VERSION 5.8 ;
BUSBITCHARS "[]" ;
DIVIDERCHAR "/" ;
UNITS
    DATABASE MICRONS 1000 ;
END UNITS

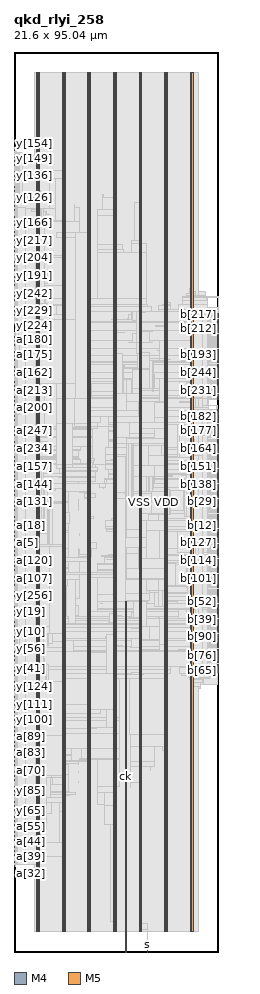
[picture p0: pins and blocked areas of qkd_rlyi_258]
MACRO qkd_rlyi_258
  FOREIGN qkd_rlyi_258 0 0 ;
  CLASS BLOCK ;
  SIZE 21.6 BY 95.04 ;
  PIN a[0]
    DIRECTION INPUT ;
    USE SIGNAL ;
    PORT
      LAYER M4 ;
        RECT  0 42.48 0.084 42.504 ;
    END
  END a[0]
  PIN a[100]
    DIRECTION INPUT ;
    USE SIGNAL ;
    PORT
      LAYER M4 ;
        RECT  0 38.448 0.084 38.472 ;
    END
  END a[100]
  PIN a[101]
    DIRECTION INPUT ;
    USE SIGNAL ;
    PORT
      LAYER M4 ;
        RECT  0 38.592 0.084 38.616 ;
    END
  END a[101]
  PIN a[102]
    DIRECTION INPUT ;
    USE SIGNAL ;
    PORT
      LAYER M4 ;
        RECT  0 38.736 0.084 38.76 ;
    END
  END a[102]
  PIN a[103]
    DIRECTION INPUT ;
    USE SIGNAL ;
    PORT
      LAYER M4 ;
        RECT  0 38.88 0.084 38.904 ;
    END
  END a[103]
  PIN a[104]
    DIRECTION INPUT ;
    USE SIGNAL ;
    PORT
      LAYER M4 ;
        RECT  0 39.024 0.084 39.048 ;
    END
  END a[104]
  PIN a[105]
    DIRECTION INPUT ;
    USE SIGNAL ;
    PORT
      LAYER M4 ;
        RECT  0 39.168 0.084 39.192 ;
    END
  END a[105]
  PIN a[106]
    DIRECTION INPUT ;
    USE SIGNAL ;
    PORT
      LAYER M4 ;
        RECT  0 39.312 0.084 39.336 ;
    END
  END a[106]
  PIN a[107]
    DIRECTION INPUT ;
    USE SIGNAL ;
    PORT
      LAYER M4 ;
        RECT  0 39.456 0.084 39.48 ;
    END
  END a[107]
  PIN a[108]
    DIRECTION INPUT ;
    USE SIGNAL ;
    PORT
      LAYER M4 ;
        RECT  0 39.6 0.084 39.624 ;
    END
  END a[108]
  PIN a[109]
    DIRECTION INPUT ;
    USE SIGNAL ;
    PORT
      LAYER M4 ;
        RECT  0 39.744 0.084 39.768 ;
    END
  END a[109]
  PIN a[10]
    DIRECTION INPUT ;
    USE SIGNAL ;
    PORT
      LAYER M4 ;
        RECT  0 43.92 0.084 43.944 ;
    END
  END a[10]
  PIN a[110]
    DIRECTION INPUT ;
    USE SIGNAL ;
    PORT
      LAYER M4 ;
        RECT  0 39.888 0.084 39.912 ;
    END
  END a[110]
  PIN a[111]
    DIRECTION INPUT ;
    USE SIGNAL ;
    PORT
      LAYER M4 ;
        RECT  0 40.032 0.084 40.056 ;
    END
  END a[111]
  PIN a[112]
    DIRECTION INPUT ;
    USE SIGNAL ;
    PORT
      LAYER M4 ;
        RECT  0 40.176 0.084 40.2 ;
    END
  END a[112]
  PIN a[113]
    DIRECTION INPUT ;
    USE SIGNAL ;
    PORT
      LAYER M4 ;
        RECT  0 40.32 0.084 40.344 ;
    END
  END a[113]
  PIN a[114]
    DIRECTION INPUT ;
    USE SIGNAL ;
    PORT
      LAYER M4 ;
        RECT  0 40.464 0.084 40.488 ;
    END
  END a[114]
  PIN a[115]
    DIRECTION INPUT ;
    USE SIGNAL ;
    PORT
      LAYER M4 ;
        RECT  0 40.608 0.084 40.632 ;
    END
  END a[115]
  PIN a[116]
    DIRECTION INPUT ;
    USE SIGNAL ;
    PORT
      LAYER M4 ;
        RECT  0 40.752 0.084 40.776 ;
    END
  END a[116]
  PIN a[117]
    DIRECTION INPUT ;
    USE SIGNAL ;
    PORT
      LAYER M4 ;
        RECT  0 40.896 0.084 40.92 ;
    END
  END a[117]
  PIN a[118]
    DIRECTION INPUT ;
    USE SIGNAL ;
    PORT
      LAYER M4 ;
        RECT  0 41.04 0.084 41.064 ;
    END
  END a[118]
  PIN a[119]
    DIRECTION INPUT ;
    USE SIGNAL ;
    PORT
      LAYER M4 ;
        RECT  0 41.184 0.084 41.208 ;
    END
  END a[119]
  PIN a[11]
    DIRECTION INPUT ;
    USE SIGNAL ;
    PORT
      LAYER M4 ;
        RECT  0 44.064 0.084 44.088 ;
    END
  END a[11]
  PIN a[120]
    DIRECTION INPUT ;
    USE SIGNAL ;
    PORT
      LAYER M4 ;
        RECT  0 41.328 0.084 41.352 ;
    END
  END a[120]
  PIN a[121]
    DIRECTION INPUT ;
    USE SIGNAL ;
    PORT
      LAYER M4 ;
        RECT  0 41.472 0.084 41.496 ;
    END
  END a[121]
  PIN a[122]
    DIRECTION INPUT ;
    USE SIGNAL ;
    PORT
      LAYER M4 ;
        RECT  0 41.616 0.084 41.64 ;
    END
  END a[122]
  PIN a[123]
    DIRECTION INPUT ;
    USE SIGNAL ;
    PORT
      LAYER M4 ;
        RECT  0 41.76 0.084 41.784 ;
    END
  END a[123]
  PIN a[124]
    DIRECTION INPUT ;
    USE SIGNAL ;
    PORT
      LAYER M4 ;
        RECT  0 41.904 0.084 41.928 ;
    END
  END a[124]
  PIN a[125]
    DIRECTION INPUT ;
    USE SIGNAL ;
    PORT
      LAYER M4 ;
        RECT  0 42.048 0.084 42.072 ;
    END
  END a[125]
  PIN a[126]
    DIRECTION INPUT ;
    USE SIGNAL ;
    PORT
      LAYER M4 ;
        RECT  0 42.192 0.084 42.216 ;
    END
  END a[126]
  PIN a[127]
    DIRECTION INPUT ;
    USE SIGNAL ;
    PORT
      LAYER M4 ;
        RECT  0 42.336 0.084 42.36 ;
    END
  END a[127]
  PIN a[128]
    DIRECTION INPUT ;
    USE SIGNAL ;
    PORT
      LAYER M4 ;
        RECT  0 47.088 0.084 47.112 ;
    END
  END a[128]
  PIN a[129]
    DIRECTION INPUT ;
    USE SIGNAL ;
    PORT
      LAYER M4 ;
        RECT  0 47.232 0.084 47.256 ;
    END
  END a[129]
  PIN a[12]
    DIRECTION INPUT ;
    USE SIGNAL ;
    PORT
      LAYER M4 ;
        RECT  0 44.208 0.084 44.232 ;
    END
  END a[12]
  PIN a[130]
    DIRECTION INPUT ;
    USE SIGNAL ;
    PORT
      LAYER M4 ;
        RECT  0 47.376 0.084 47.4 ;
    END
  END a[130]
  PIN a[131]
    DIRECTION INPUT ;
    USE SIGNAL ;
    PORT
      LAYER M4 ;
        RECT  0 47.52 0.084 47.544 ;
    END
  END a[131]
  PIN a[132]
    DIRECTION INPUT ;
    USE SIGNAL ;
    PORT
      LAYER M4 ;
        RECT  0 47.664 0.084 47.688 ;
    END
  END a[132]
  PIN a[133]
    DIRECTION INPUT ;
    USE SIGNAL ;
    PORT
      LAYER M4 ;
        RECT  0 47.808 0.084 47.832 ;
    END
  END a[133]
  PIN a[134]
    DIRECTION INPUT ;
    USE SIGNAL ;
    PORT
      LAYER M4 ;
        RECT  0 47.952 0.084 47.976 ;
    END
  END a[134]
  PIN a[135]
    DIRECTION INPUT ;
    USE SIGNAL ;
    PORT
      LAYER M4 ;
        RECT  0 48.096 0.084 48.12 ;
    END
  END a[135]
  PIN a[136]
    DIRECTION INPUT ;
    USE SIGNAL ;
    PORT
      LAYER M4 ;
        RECT  0 48.24 0.084 48.264 ;
    END
  END a[136]
  PIN a[137]
    DIRECTION INPUT ;
    USE SIGNAL ;
    PORT
      LAYER M4 ;
        RECT  0 48.384 0.084 48.408 ;
    END
  END a[137]
  PIN a[138]
    DIRECTION INPUT ;
    USE SIGNAL ;
    PORT
      LAYER M4 ;
        RECT  0 48.528 0.084 48.552 ;
    END
  END a[138]
  PIN a[139]
    DIRECTION INPUT ;
    USE SIGNAL ;
    PORT
      LAYER M4 ;
        RECT  0 48.672 0.084 48.696 ;
    END
  END a[139]
  PIN a[13]
    DIRECTION INPUT ;
    USE SIGNAL ;
    PORT
      LAYER M4 ;
        RECT  0 44.352 0.084 44.376 ;
    END
  END a[13]
  PIN a[140]
    DIRECTION INPUT ;
    USE SIGNAL ;
    PORT
      LAYER M4 ;
        RECT  0 48.816 0.084 48.84 ;
    END
  END a[140]
  PIN a[141]
    DIRECTION INPUT ;
    USE SIGNAL ;
    PORT
      LAYER M4 ;
        RECT  0 48.96 0.084 48.984 ;
    END
  END a[141]
  PIN a[142]
    DIRECTION INPUT ;
    USE SIGNAL ;
    PORT
      LAYER M4 ;
        RECT  0 49.104 0.084 49.128 ;
    END
  END a[142]
  PIN a[143]
    DIRECTION INPUT ;
    USE SIGNAL ;
    PORT
      LAYER M4 ;
        RECT  0 49.248 0.084 49.272 ;
    END
  END a[143]
  PIN a[144]
    DIRECTION INPUT ;
    USE SIGNAL ;
    PORT
      LAYER M4 ;
        RECT  0 49.392 0.084 49.416 ;
    END
  END a[144]
  PIN a[145]
    DIRECTION INPUT ;
    USE SIGNAL ;
    PORT
      LAYER M4 ;
        RECT  0 49.536 0.084 49.56 ;
    END
  END a[145]
  PIN a[146]
    DIRECTION INPUT ;
    USE SIGNAL ;
    PORT
      LAYER M4 ;
        RECT  0 49.68 0.084 49.704 ;
    END
  END a[146]
  PIN a[147]
    DIRECTION INPUT ;
    USE SIGNAL ;
    PORT
      LAYER M4 ;
        RECT  0 49.824 0.084 49.848 ;
    END
  END a[147]
  PIN a[148]
    DIRECTION INPUT ;
    USE SIGNAL ;
    PORT
      LAYER M4 ;
        RECT  0 49.968 0.084 49.992 ;
    END
  END a[148]
  PIN a[149]
    DIRECTION INPUT ;
    USE SIGNAL ;
    PORT
      LAYER M4 ;
        RECT  0 50.112 0.084 50.136 ;
    END
  END a[149]
  PIN a[14]
    DIRECTION INPUT ;
    USE SIGNAL ;
    PORT
      LAYER M4 ;
        RECT  0 44.496 0.084 44.52 ;
    END
  END a[14]
  PIN a[150]
    DIRECTION INPUT ;
    USE SIGNAL ;
    PORT
      LAYER M4 ;
        RECT  0 50.256 0.084 50.28 ;
    END
  END a[150]
  PIN a[151]
    DIRECTION INPUT ;
    USE SIGNAL ;
    PORT
      LAYER M4 ;
        RECT  0 50.4 0.084 50.424 ;
    END
  END a[151]
  PIN a[152]
    DIRECTION INPUT ;
    USE SIGNAL ;
    PORT
      LAYER M4 ;
        RECT  0 50.544 0.084 50.568 ;
    END
  END a[152]
  PIN a[153]
    DIRECTION INPUT ;
    USE SIGNAL ;
    PORT
      LAYER M4 ;
        RECT  0 50.688 0.084 50.712 ;
    END
  END a[153]
  PIN a[154]
    DIRECTION INPUT ;
    USE SIGNAL ;
    PORT
      LAYER M4 ;
        RECT  0 50.832 0.084 50.856 ;
    END
  END a[154]
  PIN a[155]
    DIRECTION INPUT ;
    USE SIGNAL ;
    PORT
      LAYER M4 ;
        RECT  0 50.976 0.084 51 ;
    END
  END a[155]
  PIN a[156]
    DIRECTION INPUT ;
    USE SIGNAL ;
    PORT
      LAYER M4 ;
        RECT  0 51.12 0.084 51.144 ;
    END
  END a[156]
  PIN a[157]
    DIRECTION INPUT ;
    USE SIGNAL ;
    PORT
      LAYER M4 ;
        RECT  0 51.264 0.084 51.288 ;
    END
  END a[157]
  PIN a[158]
    DIRECTION INPUT ;
    USE SIGNAL ;
    PORT
      LAYER M4 ;
        RECT  0 51.408 0.084 51.432 ;
    END
  END a[158]
  PIN a[159]
    DIRECTION INPUT ;
    USE SIGNAL ;
    PORT
      LAYER M4 ;
        RECT  0 51.552 0.084 51.576 ;
    END
  END a[159]
  PIN a[15]
    DIRECTION INPUT ;
    USE SIGNAL ;
    PORT
      LAYER M4 ;
        RECT  0 44.64 0.084 44.664 ;
    END
  END a[15]
  PIN a[160]
    DIRECTION INPUT ;
    USE SIGNAL ;
    PORT
      LAYER M4 ;
        RECT  0 60.912 0.084 60.936 ;
    END
  END a[160]
  PIN a[161]
    DIRECTION INPUT ;
    USE SIGNAL ;
    PORT
      LAYER M4 ;
        RECT  0 61.056 0.084 61.08 ;
    END
  END a[161]
  PIN a[162]
    DIRECTION INPUT ;
    USE SIGNAL ;
    PORT
      LAYER M4 ;
        RECT  0 61.2 0.084 61.224 ;
    END
  END a[162]
  PIN a[163]
    DIRECTION INPUT ;
    USE SIGNAL ;
    PORT
      LAYER M4 ;
        RECT  0 61.344 0.084 61.368 ;
    END
  END a[163]
  PIN a[164]
    DIRECTION INPUT ;
    USE SIGNAL ;
    PORT
      LAYER M4 ;
        RECT  0 61.488 0.084 61.512 ;
    END
  END a[164]
  PIN a[165]
    DIRECTION INPUT ;
    USE SIGNAL ;
    PORT
      LAYER M4 ;
        RECT  0 61.632 0.084 61.656 ;
    END
  END a[165]
  PIN a[166]
    DIRECTION INPUT ;
    USE SIGNAL ;
    PORT
      LAYER M4 ;
        RECT  0 61.776 0.084 61.8 ;
    END
  END a[166]
  PIN a[167]
    DIRECTION INPUT ;
    USE SIGNAL ;
    PORT
      LAYER M4 ;
        RECT  0 61.92 0.084 61.944 ;
    END
  END a[167]
  PIN a[168]
    DIRECTION INPUT ;
    USE SIGNAL ;
    PORT
      LAYER M4 ;
        RECT  0 62.064 0.084 62.088 ;
    END
  END a[168]
  PIN a[169]
    DIRECTION INPUT ;
    USE SIGNAL ;
    PORT
      LAYER M4 ;
        RECT  0 62.208 0.084 62.232 ;
    END
  END a[169]
  PIN a[16]
    DIRECTION INPUT ;
    USE SIGNAL ;
    PORT
      LAYER M4 ;
        RECT  0 44.784 0.084 44.808 ;
    END
  END a[16]
  PIN a[170]
    DIRECTION INPUT ;
    USE SIGNAL ;
    PORT
      LAYER M4 ;
        RECT  0 62.352 0.084 62.376 ;
    END
  END a[170]
  PIN a[171]
    DIRECTION INPUT ;
    USE SIGNAL ;
    PORT
      LAYER M4 ;
        RECT  0 62.496 0.084 62.52 ;
    END
  END a[171]
  PIN a[172]
    DIRECTION INPUT ;
    USE SIGNAL ;
    PORT
      LAYER M4 ;
        RECT  0 62.64 0.084 62.664 ;
    END
  END a[172]
  PIN a[173]
    DIRECTION INPUT ;
    USE SIGNAL ;
    PORT
      LAYER M4 ;
        RECT  0 62.784 0.084 62.808 ;
    END
  END a[173]
  PIN a[174]
    DIRECTION INPUT ;
    USE SIGNAL ;
    PORT
      LAYER M4 ;
        RECT  0 62.928 0.084 62.952 ;
    END
  END a[174]
  PIN a[175]
    DIRECTION INPUT ;
    USE SIGNAL ;
    PORT
      LAYER M4 ;
        RECT  0 63.072 0.084 63.096 ;
    END
  END a[175]
  PIN a[176]
    DIRECTION INPUT ;
    USE SIGNAL ;
    PORT
      LAYER M4 ;
        RECT  0 63.216 0.084 63.24 ;
    END
  END a[176]
  PIN a[177]
    DIRECTION INPUT ;
    USE SIGNAL ;
    PORT
      LAYER M4 ;
        RECT  0 63.36 0.084 63.384 ;
    END
  END a[177]
  PIN a[178]
    DIRECTION INPUT ;
    USE SIGNAL ;
    PORT
      LAYER M4 ;
        RECT  0 63.504 0.084 63.528 ;
    END
  END a[178]
  PIN a[179]
    DIRECTION INPUT ;
    USE SIGNAL ;
    PORT
      LAYER M4 ;
        RECT  0 63.648 0.084 63.672 ;
    END
  END a[179]
  PIN a[17]
    DIRECTION INPUT ;
    USE SIGNAL ;
    PORT
      LAYER M4 ;
        RECT  0 44.928 0.084 44.952 ;
    END
  END a[17]
  PIN a[180]
    DIRECTION INPUT ;
    USE SIGNAL ;
    PORT
      LAYER M4 ;
        RECT  0 63.792 0.084 63.816 ;
    END
  END a[180]
  PIN a[181]
    DIRECTION INPUT ;
    USE SIGNAL ;
    PORT
      LAYER M4 ;
        RECT  0 63.936 0.084 63.96 ;
    END
  END a[181]
  PIN a[182]
    DIRECTION INPUT ;
    USE SIGNAL ;
    PORT
      LAYER M4 ;
        RECT  0 64.08 0.084 64.104 ;
    END
  END a[182]
  PIN a[183]
    DIRECTION INPUT ;
    USE SIGNAL ;
    PORT
      LAYER M4 ;
        RECT  0 64.224 0.084 64.248 ;
    END
  END a[183]
  PIN a[184]
    DIRECTION INPUT ;
    USE SIGNAL ;
    PORT
      LAYER M4 ;
        RECT  0 64.368 0.084 64.392 ;
    END
  END a[184]
  PIN a[185]
    DIRECTION INPUT ;
    USE SIGNAL ;
    PORT
      LAYER M4 ;
        RECT  0 64.512 0.084 64.536 ;
    END
  END a[185]
  PIN a[186]
    DIRECTION INPUT ;
    USE SIGNAL ;
    PORT
      LAYER M4 ;
        RECT  0 64.656 0.084 64.68 ;
    END
  END a[186]
  PIN a[187]
    DIRECTION INPUT ;
    USE SIGNAL ;
    PORT
      LAYER M4 ;
        RECT  0 64.8 0.084 64.824 ;
    END
  END a[187]
  PIN a[188]
    DIRECTION INPUT ;
    USE SIGNAL ;
    PORT
      LAYER M4 ;
        RECT  0 64.944 0.084 64.968 ;
    END
  END a[188]
  PIN a[189]
    DIRECTION INPUT ;
    USE SIGNAL ;
    PORT
      LAYER M4 ;
        RECT  0 65.088 0.084 65.112 ;
    END
  END a[189]
  PIN a[18]
    DIRECTION INPUT ;
    USE SIGNAL ;
    PORT
      LAYER M4 ;
        RECT  0 45.072 0.084 45.096 ;
    END
  END a[18]
  PIN a[190]
    DIRECTION INPUT ;
    USE SIGNAL ;
    PORT
      LAYER M4 ;
        RECT  0 65.232 0.084 65.256 ;
    END
  END a[190]
  PIN a[191]
    DIRECTION INPUT ;
    USE SIGNAL ;
    PORT
      LAYER M4 ;
        RECT  0 65.376 0.084 65.4 ;
    END
  END a[191]
  PIN a[192]
    DIRECTION INPUT ;
    USE SIGNAL ;
    PORT
      LAYER M4 ;
        RECT  0 56.304 0.084 56.328 ;
    END
  END a[192]
  PIN a[193]
    DIRECTION INPUT ;
    USE SIGNAL ;
    PORT
      LAYER M4 ;
        RECT  0 56.448 0.084 56.472 ;
    END
  END a[193]
  PIN a[194]
    DIRECTION INPUT ;
    USE SIGNAL ;
    PORT
      LAYER M4 ;
        RECT  0 56.592 0.084 56.616 ;
    END
  END a[194]
  PIN a[195]
    DIRECTION INPUT ;
    USE SIGNAL ;
    PORT
      LAYER M4 ;
        RECT  0 56.736 0.084 56.76 ;
    END
  END a[195]
  PIN a[196]
    DIRECTION INPUT ;
    USE SIGNAL ;
    PORT
      LAYER M4 ;
        RECT  0 56.88 0.084 56.904 ;
    END
  END a[196]
  PIN a[197]
    DIRECTION INPUT ;
    USE SIGNAL ;
    PORT
      LAYER M4 ;
        RECT  0 57.024 0.084 57.048 ;
    END
  END a[197]
  PIN a[198]
    DIRECTION INPUT ;
    USE SIGNAL ;
    PORT
      LAYER M4 ;
        RECT  0 57.168 0.084 57.192 ;
    END
  END a[198]
  PIN a[199]
    DIRECTION INPUT ;
    USE SIGNAL ;
    PORT
      LAYER M4 ;
        RECT  0 57.312 0.084 57.336 ;
    END
  END a[199]
  PIN a[19]
    DIRECTION INPUT ;
    USE SIGNAL ;
    PORT
      LAYER M4 ;
        RECT  0 45.216 0.084 45.24 ;
    END
  END a[19]
  PIN a[1]
    DIRECTION INPUT ;
    USE SIGNAL ;
    PORT
      LAYER M4 ;
        RECT  0 42.624 0.084 42.648 ;
    END
  END a[1]
  PIN a[200]
    DIRECTION INPUT ;
    USE SIGNAL ;
    PORT
      LAYER M4 ;
        RECT  0 57.456 0.084 57.48 ;
    END
  END a[200]
  PIN a[201]
    DIRECTION INPUT ;
    USE SIGNAL ;
    PORT
      LAYER M4 ;
        RECT  0 57.6 0.084 57.624 ;
    END
  END a[201]
  PIN a[202]
    DIRECTION INPUT ;
    USE SIGNAL ;
    PORT
      LAYER M4 ;
        RECT  0 57.744 0.084 57.768 ;
    END
  END a[202]
  PIN a[203]
    DIRECTION INPUT ;
    USE SIGNAL ;
    PORT
      LAYER M4 ;
        RECT  0 57.888 0.084 57.912 ;
    END
  END a[203]
  PIN a[204]
    DIRECTION INPUT ;
    USE SIGNAL ;
    PORT
      LAYER M4 ;
        RECT  0 58.032 0.084 58.056 ;
    END
  END a[204]
  PIN a[205]
    DIRECTION INPUT ;
    USE SIGNAL ;
    PORT
      LAYER M4 ;
        RECT  0 58.176 0.084 58.2 ;
    END
  END a[205]
  PIN a[206]
    DIRECTION INPUT ;
    USE SIGNAL ;
    PORT
      LAYER M4 ;
        RECT  0 58.32 0.084 58.344 ;
    END
  END a[206]
  PIN a[207]
    DIRECTION INPUT ;
    USE SIGNAL ;
    PORT
      LAYER M4 ;
        RECT  0 58.464 0.084 58.488 ;
    END
  END a[207]
  PIN a[208]
    DIRECTION INPUT ;
    USE SIGNAL ;
    PORT
      LAYER M4 ;
        RECT  0 58.608 0.084 58.632 ;
    END
  END a[208]
  PIN a[209]
    DIRECTION INPUT ;
    USE SIGNAL ;
    PORT
      LAYER M4 ;
        RECT  0 58.752 0.084 58.776 ;
    END
  END a[209]
  PIN a[20]
    DIRECTION INPUT ;
    USE SIGNAL ;
    PORT
      LAYER M4 ;
        RECT  0 45.36 0.084 45.384 ;
    END
  END a[20]
  PIN a[210]
    DIRECTION INPUT ;
    USE SIGNAL ;
    PORT
      LAYER M4 ;
        RECT  0 58.896 0.084 58.92 ;
    END
  END a[210]
  PIN a[211]
    DIRECTION INPUT ;
    USE SIGNAL ;
    PORT
      LAYER M4 ;
        RECT  0 59.04 0.084 59.064 ;
    END
  END a[211]
  PIN a[212]
    DIRECTION INPUT ;
    USE SIGNAL ;
    PORT
      LAYER M4 ;
        RECT  0 59.184 0.084 59.208 ;
    END
  END a[212]
  PIN a[213]
    DIRECTION INPUT ;
    USE SIGNAL ;
    PORT
      LAYER M4 ;
        RECT  0 59.328 0.084 59.352 ;
    END
  END a[213]
  PIN a[214]
    DIRECTION INPUT ;
    USE SIGNAL ;
    PORT
      LAYER M4 ;
        RECT  0 59.472 0.084 59.496 ;
    END
  END a[214]
  PIN a[215]
    DIRECTION INPUT ;
    USE SIGNAL ;
    PORT
      LAYER M4 ;
        RECT  0 59.616 0.084 59.64 ;
    END
  END a[215]
  PIN a[216]
    DIRECTION INPUT ;
    USE SIGNAL ;
    PORT
      LAYER M4 ;
        RECT  0 59.76 0.084 59.784 ;
    END
  END a[216]
  PIN a[217]
    DIRECTION INPUT ;
    USE SIGNAL ;
    PORT
      LAYER M4 ;
        RECT  0 59.904 0.084 59.928 ;
    END
  END a[217]
  PIN a[218]
    DIRECTION INPUT ;
    USE SIGNAL ;
    PORT
      LAYER M4 ;
        RECT  0 60.048 0.084 60.072 ;
    END
  END a[218]
  PIN a[219]
    DIRECTION INPUT ;
    USE SIGNAL ;
    PORT
      LAYER M4 ;
        RECT  0 60.192 0.084 60.216 ;
    END
  END a[219]
  PIN a[21]
    DIRECTION INPUT ;
    USE SIGNAL ;
    PORT
      LAYER M4 ;
        RECT  0 45.504 0.084 45.528 ;
    END
  END a[21]
  PIN a[220]
    DIRECTION INPUT ;
    USE SIGNAL ;
    PORT
      LAYER M4 ;
        RECT  0 60.336 0.084 60.36 ;
    END
  END a[220]
  PIN a[221]
    DIRECTION INPUT ;
    USE SIGNAL ;
    PORT
      LAYER M4 ;
        RECT  0 60.48 0.084 60.504 ;
    END
  END a[221]
  PIN a[222]
    DIRECTION INPUT ;
    USE SIGNAL ;
    PORT
      LAYER M4 ;
        RECT  0 60.624 0.084 60.648 ;
    END
  END a[222]
  PIN a[223]
    DIRECTION INPUT ;
    USE SIGNAL ;
    PORT
      LAYER M4 ;
        RECT  0 60.768 0.084 60.792 ;
    END
  END a[223]
  PIN a[224]
    DIRECTION INPUT ;
    USE SIGNAL ;
    PORT
      LAYER M4 ;
        RECT  0 51.696 0.084 51.72 ;
    END
  END a[224]
  PIN a[225]
    DIRECTION INPUT ;
    USE SIGNAL ;
    PORT
      LAYER M4 ;
        RECT  0 51.84 0.084 51.864 ;
    END
  END a[225]
  PIN a[226]
    DIRECTION INPUT ;
    USE SIGNAL ;
    PORT
      LAYER M4 ;
        RECT  0 51.984 0.084 52.008 ;
    END
  END a[226]
  PIN a[227]
    DIRECTION INPUT ;
    USE SIGNAL ;
    PORT
      LAYER M4 ;
        RECT  0 52.128 0.084 52.152 ;
    END
  END a[227]
  PIN a[228]
    DIRECTION INPUT ;
    USE SIGNAL ;
    PORT
      LAYER M4 ;
        RECT  0 52.272 0.084 52.296 ;
    END
  END a[228]
  PIN a[229]
    DIRECTION INPUT ;
    USE SIGNAL ;
    PORT
      LAYER M4 ;
        RECT  0 52.416 0.084 52.44 ;
    END
  END a[229]
  PIN a[22]
    DIRECTION INPUT ;
    USE SIGNAL ;
    PORT
      LAYER M4 ;
        RECT  0 45.648 0.084 45.672 ;
    END
  END a[22]
  PIN a[230]
    DIRECTION INPUT ;
    USE SIGNAL ;
    PORT
      LAYER M4 ;
        RECT  0 52.56 0.084 52.584 ;
    END
  END a[230]
  PIN a[231]
    DIRECTION INPUT ;
    USE SIGNAL ;
    PORT
      LAYER M4 ;
        RECT  0 52.704 0.084 52.728 ;
    END
  END a[231]
  PIN a[232]
    DIRECTION INPUT ;
    USE SIGNAL ;
    PORT
      LAYER M4 ;
        RECT  0 52.848 0.084 52.872 ;
    END
  END a[232]
  PIN a[233]
    DIRECTION INPUT ;
    USE SIGNAL ;
    PORT
      LAYER M4 ;
        RECT  0 52.992 0.084 53.016 ;
    END
  END a[233]
  PIN a[234]
    DIRECTION INPUT ;
    USE SIGNAL ;
    PORT
      LAYER M4 ;
        RECT  0 53.136 0.084 53.16 ;
    END
  END a[234]
  PIN a[235]
    DIRECTION INPUT ;
    USE SIGNAL ;
    PORT
      LAYER M4 ;
        RECT  0 53.28 0.084 53.304 ;
    END
  END a[235]
  PIN a[236]
    DIRECTION INPUT ;
    USE SIGNAL ;
    PORT
      LAYER M4 ;
        RECT  0 53.424 0.084 53.448 ;
    END
  END a[236]
  PIN a[237]
    DIRECTION INPUT ;
    USE SIGNAL ;
    PORT
      LAYER M4 ;
        RECT  0 53.568 0.084 53.592 ;
    END
  END a[237]
  PIN a[238]
    DIRECTION INPUT ;
    USE SIGNAL ;
    PORT
      LAYER M4 ;
        RECT  0 53.712 0.084 53.736 ;
    END
  END a[238]
  PIN a[239]
    DIRECTION INPUT ;
    USE SIGNAL ;
    PORT
      LAYER M4 ;
        RECT  0 53.856 0.084 53.88 ;
    END
  END a[239]
  PIN a[23]
    DIRECTION INPUT ;
    USE SIGNAL ;
    PORT
      LAYER M4 ;
        RECT  0 45.792 0.084 45.816 ;
    END
  END a[23]
  PIN a[240]
    DIRECTION INPUT ;
    USE SIGNAL ;
    PORT
      LAYER M4 ;
        RECT  0 54 0.084 54.024 ;
    END
  END a[240]
  PIN a[241]
    DIRECTION INPUT ;
    USE SIGNAL ;
    PORT
      LAYER M4 ;
        RECT  0 54.144 0.084 54.168 ;
    END
  END a[241]
  PIN a[242]
    DIRECTION INPUT ;
    USE SIGNAL ;
    PORT
      LAYER M4 ;
        RECT  0 54.288 0.084 54.312 ;
    END
  END a[242]
  PIN a[243]
    DIRECTION INPUT ;
    USE SIGNAL ;
    PORT
      LAYER M4 ;
        RECT  0 54.432 0.084 54.456 ;
    END
  END a[243]
  PIN a[244]
    DIRECTION INPUT ;
    USE SIGNAL ;
    PORT
      LAYER M4 ;
        RECT  0 54.576 0.084 54.6 ;
    END
  END a[244]
  PIN a[245]
    DIRECTION INPUT ;
    USE SIGNAL ;
    PORT
      LAYER M4 ;
        RECT  0 54.72 0.084 54.744 ;
    END
  END a[245]
  PIN a[246]
    DIRECTION INPUT ;
    USE SIGNAL ;
    PORT
      LAYER M4 ;
        RECT  0 54.864 0.084 54.888 ;
    END
  END a[246]
  PIN a[247]
    DIRECTION INPUT ;
    USE SIGNAL ;
    PORT
      LAYER M4 ;
        RECT  0 55.008 0.084 55.032 ;
    END
  END a[247]
  PIN a[248]
    DIRECTION INPUT ;
    USE SIGNAL ;
    PORT
      LAYER M4 ;
        RECT  0 55.152 0.084 55.176 ;
    END
  END a[248]
  PIN a[249]
    DIRECTION INPUT ;
    USE SIGNAL ;
    PORT
      LAYER M4 ;
        RECT  0 55.296 0.084 55.32 ;
    END
  END a[249]
  PIN a[24]
    DIRECTION INPUT ;
    USE SIGNAL ;
    PORT
      LAYER M4 ;
        RECT  0 45.936 0.084 45.96 ;
    END
  END a[24]
  PIN a[250]
    DIRECTION INPUT ;
    USE SIGNAL ;
    PORT
      LAYER M4 ;
        RECT  0 55.44 0.084 55.464 ;
    END
  END a[250]
  PIN a[251]
    DIRECTION INPUT ;
    USE SIGNAL ;
    PORT
      LAYER M4 ;
        RECT  0 55.584 0.084 55.608 ;
    END
  END a[251]
  PIN a[252]
    DIRECTION INPUT ;
    USE SIGNAL ;
    PORT
      LAYER M4 ;
        RECT  0 55.728 0.084 55.752 ;
    END
  END a[252]
  PIN a[253]
    DIRECTION INPUT ;
    USE SIGNAL ;
    PORT
      LAYER M4 ;
        RECT  0 55.872 0.084 55.896 ;
    END
  END a[253]
  PIN a[254]
    DIRECTION INPUT ;
    USE SIGNAL ;
    PORT
      LAYER M4 ;
        RECT  0 56.016 0.084 56.04 ;
    END
  END a[254]
  PIN a[255]
    DIRECTION INPUT ;
    USE SIGNAL ;
    PORT
      LAYER M4 ;
        RECT  0 56.16 0.084 56.184 ;
    END
  END a[255]
  PIN a[256]
    DIRECTION INPUT ;
    USE SIGNAL ;
    PORT
      LAYER M4 ;
        RECT  0 32.112 0.084 32.136 ;
    END
  END a[256]
  PIN a[257]
    DIRECTION INPUT ;
    USE SIGNAL ;
    PORT
      LAYER M4 ;
        RECT  0 32.256 0.084 32.28 ;
    END
  END a[257]
  PIN a[25]
    DIRECTION INPUT ;
    USE SIGNAL ;
    PORT
      LAYER M4 ;
        RECT  0 46.08 0.084 46.104 ;
    END
  END a[25]
  PIN a[26]
    DIRECTION INPUT ;
    USE SIGNAL ;
    PORT
      LAYER M4 ;
        RECT  0 46.224 0.084 46.248 ;
    END
  END a[26]
  PIN a[27]
    DIRECTION INPUT ;
    USE SIGNAL ;
    PORT
      LAYER M4 ;
        RECT  0 46.368 0.084 46.392 ;
    END
  END a[27]
  PIN a[28]
    DIRECTION INPUT ;
    USE SIGNAL ;
    PORT
      LAYER M4 ;
        RECT  0 46.512 0.084 46.536 ;
    END
  END a[28]
  PIN a[29]
    DIRECTION INPUT ;
    USE SIGNAL ;
    PORT
      LAYER M4 ;
        RECT  0 46.656 0.084 46.68 ;
    END
  END a[29]
  PIN a[2]
    DIRECTION INPUT ;
    USE SIGNAL ;
    PORT
      LAYER M4 ;
        RECT  0 42.768 0.084 42.792 ;
    END
  END a[2]
  PIN a[30]
    DIRECTION INPUT ;
    USE SIGNAL ;
    PORT
      LAYER M4 ;
        RECT  0 46.8 0.084 46.824 ;
    END
  END a[30]
  PIN a[31]
    DIRECTION INPUT ;
    USE SIGNAL ;
    PORT
      LAYER M4 ;
        RECT  0 46.944 0.084 46.968 ;
    END
  END a[31]
  PIN a[32]
    DIRECTION INPUT ;
    USE SIGNAL ;
    PORT
      LAYER M4 ;
        RECT  0 9.072 0.084 9.096 ;
    END
  END a[32]
  PIN a[33]
    DIRECTION INPUT ;
    USE SIGNAL ;
    PORT
      LAYER M4 ;
        RECT  0 9.216 0.084 9.24 ;
    END
  END a[33]
  PIN a[34]
    DIRECTION INPUT ;
    USE SIGNAL ;
    PORT
      LAYER M4 ;
        RECT  0 9.36 0.084 9.384 ;
    END
  END a[34]
  PIN a[35]
    DIRECTION INPUT ;
    USE SIGNAL ;
    PORT
      LAYER M4 ;
        RECT  0 9.504 0.084 9.528 ;
    END
  END a[35]
  PIN a[36]
    DIRECTION INPUT ;
    USE SIGNAL ;
    PORT
      LAYER M4 ;
        RECT  0 9.648 0.084 9.672 ;
    END
  END a[36]
  PIN a[37]
    DIRECTION INPUT ;
    USE SIGNAL ;
    PORT
      LAYER M4 ;
        RECT  0 9.792 0.084 9.816 ;
    END
  END a[37]
  PIN a[38]
    DIRECTION INPUT ;
    USE SIGNAL ;
    PORT
      LAYER M4 ;
        RECT  0 9.936 0.084 9.96 ;
    END
  END a[38]
  PIN a[39]
    DIRECTION INPUT ;
    USE SIGNAL ;
    PORT
      LAYER M4 ;
        RECT  0 10.08 0.084 10.104 ;
    END
  END a[39]
  PIN a[3]
    DIRECTION INPUT ;
    USE SIGNAL ;
    PORT
      LAYER M4 ;
        RECT  0 42.912 0.084 42.936 ;
    END
  END a[3]
  PIN a[40]
    DIRECTION INPUT ;
    USE SIGNAL ;
    PORT
      LAYER M4 ;
        RECT  0 10.224 0.084 10.248 ;
    END
  END a[40]
  PIN a[41]
    DIRECTION INPUT ;
    USE SIGNAL ;
    PORT
      LAYER M4 ;
        RECT  0 10.368 0.084 10.392 ;
    END
  END a[41]
  PIN a[42]
    DIRECTION INPUT ;
    USE SIGNAL ;
    PORT
      LAYER M4 ;
        RECT  0 10.512 0.084 10.536 ;
    END
  END a[42]
  PIN a[43]
    DIRECTION INPUT ;
    USE SIGNAL ;
    PORT
      LAYER M4 ;
        RECT  0 10.656 0.084 10.68 ;
    END
  END a[43]
  PIN a[44]
    DIRECTION INPUT ;
    USE SIGNAL ;
    PORT
      LAYER M4 ;
        RECT  0 10.8 0.084 10.824 ;
    END
  END a[44]
  PIN a[45]
    DIRECTION INPUT ;
    USE SIGNAL ;
    PORT
      LAYER M4 ;
        RECT  0 10.944 0.084 10.968 ;
    END
  END a[45]
  PIN a[46]
    DIRECTION INPUT ;
    USE SIGNAL ;
    PORT
      LAYER M4 ;
        RECT  0 11.088 0.084 11.112 ;
    END
  END a[46]
  PIN a[47]
    DIRECTION INPUT ;
    USE SIGNAL ;
    PORT
      LAYER M4 ;
        RECT  0 11.232 0.084 11.256 ;
    END
  END a[47]
  PIN a[48]
    DIRECTION INPUT ;
    USE SIGNAL ;
    PORT
      LAYER M4 ;
        RECT  0 11.376 0.084 11.4 ;
    END
  END a[48]
  PIN a[49]
    DIRECTION INPUT ;
    USE SIGNAL ;
    PORT
      LAYER M4 ;
        RECT  0 11.52 0.084 11.544 ;
    END
  END a[49]
  PIN a[4]
    DIRECTION INPUT ;
    USE SIGNAL ;
    PORT
      LAYER M4 ;
        RECT  0 43.056 0.084 43.08 ;
    END
  END a[4]
  PIN a[50]
    DIRECTION INPUT ;
    USE SIGNAL ;
    PORT
      LAYER M4 ;
        RECT  0 11.664 0.084 11.688 ;
    END
  END a[50]
  PIN a[51]
    DIRECTION INPUT ;
    USE SIGNAL ;
    PORT
      LAYER M4 ;
        RECT  0 11.808 0.084 11.832 ;
    END
  END a[51]
  PIN a[52]
    DIRECTION INPUT ;
    USE SIGNAL ;
    PORT
      LAYER M4 ;
        RECT  0 11.952 0.084 11.976 ;
    END
  END a[52]
  PIN a[53]
    DIRECTION INPUT ;
    USE SIGNAL ;
    PORT
      LAYER M4 ;
        RECT  0 12.096 0.084 12.12 ;
    END
  END a[53]
  PIN a[54]
    DIRECTION INPUT ;
    USE SIGNAL ;
    PORT
      LAYER M4 ;
        RECT  0 12.24 0.084 12.264 ;
    END
  END a[54]
  PIN a[55]
    DIRECTION INPUT ;
    USE SIGNAL ;
    PORT
      LAYER M4 ;
        RECT  0 12.384 0.084 12.408 ;
    END
  END a[55]
  PIN a[56]
    DIRECTION INPUT ;
    USE SIGNAL ;
    PORT
      LAYER M4 ;
        RECT  0 12.528 0.084 12.552 ;
    END
  END a[56]
  PIN a[57]
    DIRECTION INPUT ;
    USE SIGNAL ;
    PORT
      LAYER M4 ;
        RECT  0 12.672 0.084 12.696 ;
    END
  END a[57]
  PIN a[58]
    DIRECTION INPUT ;
    USE SIGNAL ;
    PORT
      LAYER M4 ;
        RECT  0 12.816 0.084 12.84 ;
    END
  END a[58]
  PIN a[59]
    DIRECTION INPUT ;
    USE SIGNAL ;
    PORT
      LAYER M4 ;
        RECT  0 12.96 0.084 12.984 ;
    END
  END a[59]
  PIN a[5]
    DIRECTION INPUT ;
    USE SIGNAL ;
    PORT
      LAYER M4 ;
        RECT  0 43.2 0.084 43.224 ;
    END
  END a[5]
  PIN a[60]
    DIRECTION INPUT ;
    USE SIGNAL ;
    PORT
      LAYER M4 ;
        RECT  0 13.104 0.084 13.128 ;
    END
  END a[60]
  PIN a[61]
    DIRECTION INPUT ;
    USE SIGNAL ;
    PORT
      LAYER M4 ;
        RECT  0 13.248 0.084 13.272 ;
    END
  END a[61]
  PIN a[62]
    DIRECTION INPUT ;
    USE SIGNAL ;
    PORT
      LAYER M4 ;
        RECT  0 13.392 0.084 13.416 ;
    END
  END a[62]
  PIN a[63]
    DIRECTION INPUT ;
    USE SIGNAL ;
    PORT
      LAYER M4 ;
        RECT  0 13.536 0.084 13.56 ;
    END
  END a[63]
  PIN a[64]
    DIRECTION INPUT ;
    USE SIGNAL ;
    PORT
      LAYER M4 ;
        RECT  0 18.288 0.084 18.312 ;
    END
  END a[64]
  PIN a[65]
    DIRECTION INPUT ;
    USE SIGNAL ;
    PORT
      LAYER M4 ;
        RECT  0 18.432 0.084 18.456 ;
    END
  END a[65]
  PIN a[66]
    DIRECTION INPUT ;
    USE SIGNAL ;
    PORT
      LAYER M4 ;
        RECT  0 18.576 0.084 18.6 ;
    END
  END a[66]
  PIN a[67]
    DIRECTION INPUT ;
    USE SIGNAL ;
    PORT
      LAYER M4 ;
        RECT  0 18.72 0.084 18.744 ;
    END
  END a[67]
  PIN a[68]
    DIRECTION INPUT ;
    USE SIGNAL ;
    PORT
      LAYER M4 ;
        RECT  0 18.864 0.084 18.888 ;
    END
  END a[68]
  PIN a[69]
    DIRECTION INPUT ;
    USE SIGNAL ;
    PORT
      LAYER M4 ;
        RECT  0 19.008 0.084 19.032 ;
    END
  END a[69]
  PIN a[6]
    DIRECTION INPUT ;
    USE SIGNAL ;
    PORT
      LAYER M4 ;
        RECT  0 43.344 0.084 43.368 ;
    END
  END a[6]
  PIN a[70]
    DIRECTION INPUT ;
    USE SIGNAL ;
    PORT
      LAYER M4 ;
        RECT  0 19.152 0.084 19.176 ;
    END
  END a[70]
  PIN a[71]
    DIRECTION INPUT ;
    USE SIGNAL ;
    PORT
      LAYER M4 ;
        RECT  0 19.296 0.084 19.32 ;
    END
  END a[71]
  PIN a[72]
    DIRECTION INPUT ;
    USE SIGNAL ;
    PORT
      LAYER M4 ;
        RECT  0 19.44 0.084 19.464 ;
    END
  END a[72]
  PIN a[73]
    DIRECTION INPUT ;
    USE SIGNAL ;
    PORT
      LAYER M4 ;
        RECT  0 19.584 0.084 19.608 ;
    END
  END a[73]
  PIN a[74]
    DIRECTION INPUT ;
    USE SIGNAL ;
    PORT
      LAYER M4 ;
        RECT  0 19.728 0.084 19.752 ;
    END
  END a[74]
  PIN a[75]
    DIRECTION INPUT ;
    USE SIGNAL ;
    PORT
      LAYER M4 ;
        RECT  0 19.872 0.084 19.896 ;
    END
  END a[75]
  PIN a[76]
    DIRECTION INPUT ;
    USE SIGNAL ;
    PORT
      LAYER M4 ;
        RECT  0 20.016 0.084 20.04 ;
    END
  END a[76]
  PIN a[77]
    DIRECTION INPUT ;
    USE SIGNAL ;
    PORT
      LAYER M4 ;
        RECT  0 20.16 0.084 20.184 ;
    END
  END a[77]
  PIN a[78]
    DIRECTION INPUT ;
    USE SIGNAL ;
    PORT
      LAYER M4 ;
        RECT  0 20.304 0.084 20.328 ;
    END
  END a[78]
  PIN a[79]
    DIRECTION INPUT ;
    USE SIGNAL ;
    PORT
      LAYER M4 ;
        RECT  0 20.448 0.084 20.472 ;
    END
  END a[79]
  PIN a[7]
    DIRECTION INPUT ;
    USE SIGNAL ;
    PORT
      LAYER M4 ;
        RECT  0 43.488 0.084 43.512 ;
    END
  END a[7]
  PIN a[80]
    DIRECTION INPUT ;
    USE SIGNAL ;
    PORT
      LAYER M4 ;
        RECT  0 20.592 0.084 20.616 ;
    END
  END a[80]
  PIN a[81]
    DIRECTION INPUT ;
    USE SIGNAL ;
    PORT
      LAYER M4 ;
        RECT  0 20.736 0.084 20.76 ;
    END
  END a[81]
  PIN a[82]
    DIRECTION INPUT ;
    USE SIGNAL ;
    PORT
      LAYER M4 ;
        RECT  0 20.88 0.084 20.904 ;
    END
  END a[82]
  PIN a[83]
    DIRECTION INPUT ;
    USE SIGNAL ;
    PORT
      LAYER M4 ;
        RECT  0 21.024 0.084 21.048 ;
    END
  END a[83]
  PIN a[84]
    DIRECTION INPUT ;
    USE SIGNAL ;
    PORT
      LAYER M4 ;
        RECT  0 21.168 0.084 21.192 ;
    END
  END a[84]
  PIN a[85]
    DIRECTION INPUT ;
    USE SIGNAL ;
    PORT
      LAYER M4 ;
        RECT  0 21.312 0.084 21.336 ;
    END
  END a[85]
  PIN a[86]
    DIRECTION INPUT ;
    USE SIGNAL ;
    PORT
      LAYER M4 ;
        RECT  0 21.456 0.084 21.48 ;
    END
  END a[86]
  PIN a[87]
    DIRECTION INPUT ;
    USE SIGNAL ;
    PORT
      LAYER M4 ;
        RECT  0 21.6 0.084 21.624 ;
    END
  END a[87]
  PIN a[88]
    DIRECTION INPUT ;
    USE SIGNAL ;
    PORT
      LAYER M4 ;
        RECT  0 21.744 0.084 21.768 ;
    END
  END a[88]
  PIN a[89]
    DIRECTION INPUT ;
    USE SIGNAL ;
    PORT
      LAYER M4 ;
        RECT  0 21.888 0.084 21.912 ;
    END
  END a[89]
  PIN a[8]
    DIRECTION INPUT ;
    USE SIGNAL ;
    PORT
      LAYER M4 ;
        RECT  0 43.632 0.084 43.656 ;
    END
  END a[8]
  PIN a[90]
    DIRECTION INPUT ;
    USE SIGNAL ;
    PORT
      LAYER M4 ;
        RECT  0 22.032 0.084 22.056 ;
    END
  END a[90]
  PIN a[91]
    DIRECTION INPUT ;
    USE SIGNAL ;
    PORT
      LAYER M4 ;
        RECT  0 22.176 0.084 22.2 ;
    END
  END a[91]
  PIN a[92]
    DIRECTION INPUT ;
    USE SIGNAL ;
    PORT
      LAYER M4 ;
        RECT  0 22.32 0.084 22.344 ;
    END
  END a[92]
  PIN a[93]
    DIRECTION INPUT ;
    USE SIGNAL ;
    PORT
      LAYER M4 ;
        RECT  0 22.464 0.084 22.488 ;
    END
  END a[93]
  PIN a[94]
    DIRECTION INPUT ;
    USE SIGNAL ;
    PORT
      LAYER M4 ;
        RECT  0 22.608 0.084 22.632 ;
    END
  END a[94]
  PIN a[95]
    DIRECTION INPUT ;
    USE SIGNAL ;
    PORT
      LAYER M4 ;
        RECT  0 22.752 0.084 22.776 ;
    END
  END a[95]
  PIN a[96]
    DIRECTION INPUT ;
    USE SIGNAL ;
    PORT
      LAYER M4 ;
        RECT  0 37.872 0.084 37.896 ;
    END
  END a[96]
  PIN a[97]
    DIRECTION INPUT ;
    USE SIGNAL ;
    PORT
      LAYER M4 ;
        RECT  0 38.016 0.084 38.04 ;
    END
  END a[97]
  PIN a[98]
    DIRECTION INPUT ;
    USE SIGNAL ;
    PORT
      LAYER M4 ;
        RECT  0 38.16 0.084 38.184 ;
    END
  END a[98]
  PIN a[99]
    DIRECTION INPUT ;
    USE SIGNAL ;
    PORT
      LAYER M4 ;
        RECT  0 38.304 0.084 38.328 ;
    END
  END a[99]
  PIN a[9]
    DIRECTION INPUT ;
    USE SIGNAL ;
    PORT
      LAYER M4 ;
        RECT  0 43.776 0.084 43.8 ;
    END
  END a[9]
  PIN b[0]
    DIRECTION OUTPUT ;
    USE SIGNAL ;
    PORT
      LAYER M4 ;
        RECT  21.516 43.344 21.6 43.368 ;
    END
  END b[0]
  PIN b[100]
    DIRECTION OUTPUT ;
    USE SIGNAL ;
    PORT
      LAYER M4 ;
        RECT  21.516 39.312 21.6 39.336 ;
    END
  END b[100]
  PIN b[101]
    DIRECTION OUTPUT ;
    USE SIGNAL ;
    PORT
      LAYER M4 ;
        RECT  21.516 39.456 21.6 39.48 ;
    END
  END b[101]
  PIN b[102]
    DIRECTION OUTPUT ;
    USE SIGNAL ;
    PORT
      LAYER M4 ;
        RECT  21.516 39.6 21.6 39.624 ;
    END
  END b[102]
  PIN b[103]
    DIRECTION OUTPUT ;
    USE SIGNAL ;
    PORT
      LAYER M4 ;
        RECT  21.516 39.744 21.6 39.768 ;
    END
  END b[103]
  PIN b[104]
    DIRECTION OUTPUT ;
    USE SIGNAL ;
    PORT
      LAYER M4 ;
        RECT  21.516 39.888 21.6 39.912 ;
    END
  END b[104]
  PIN b[105]
    DIRECTION OUTPUT ;
    USE SIGNAL ;
    PORT
      LAYER M4 ;
        RECT  21.516 40.032 21.6 40.056 ;
    END
  END b[105]
  PIN b[106]
    DIRECTION OUTPUT ;
    USE SIGNAL ;
    PORT
      LAYER M4 ;
        RECT  21.516 40.176 21.6 40.2 ;
    END
  END b[106]
  PIN b[107]
    DIRECTION OUTPUT ;
    USE SIGNAL ;
    PORT
      LAYER M4 ;
        RECT  21.516 40.32 21.6 40.344 ;
    END
  END b[107]
  PIN b[108]
    DIRECTION OUTPUT ;
    USE SIGNAL ;
    PORT
      LAYER M4 ;
        RECT  21.516 40.464 21.6 40.488 ;
    END
  END b[108]
  PIN b[109]
    DIRECTION OUTPUT ;
    USE SIGNAL ;
    PORT
      LAYER M4 ;
        RECT  21.516 40.608 21.6 40.632 ;
    END
  END b[109]
  PIN b[10]
    DIRECTION OUTPUT ;
    USE SIGNAL ;
    PORT
      LAYER M4 ;
        RECT  21.516 44.784 21.6 44.808 ;
    END
  END b[10]
  PIN b[110]
    DIRECTION OUTPUT ;
    USE SIGNAL ;
    PORT
      LAYER M4 ;
        RECT  21.516 40.752 21.6 40.776 ;
    END
  END b[110]
  PIN b[111]
    DIRECTION OUTPUT ;
    USE SIGNAL ;
    PORT
      LAYER M4 ;
        RECT  21.516 40.896 21.6 40.92 ;
    END
  END b[111]
  PIN b[112]
    DIRECTION OUTPUT ;
    USE SIGNAL ;
    PORT
      LAYER M4 ;
        RECT  21.516 41.04 21.6 41.064 ;
    END
  END b[112]
  PIN b[113]
    DIRECTION OUTPUT ;
    USE SIGNAL ;
    PORT
      LAYER M4 ;
        RECT  21.516 41.184 21.6 41.208 ;
    END
  END b[113]
  PIN b[114]
    DIRECTION OUTPUT ;
    USE SIGNAL ;
    PORT
      LAYER M4 ;
        RECT  21.516 41.328 21.6 41.352 ;
    END
  END b[114]
  PIN b[115]
    DIRECTION OUTPUT ;
    USE SIGNAL ;
    PORT
      LAYER M4 ;
        RECT  21.516 41.472 21.6 41.496 ;
    END
  END b[115]
  PIN b[116]
    DIRECTION OUTPUT ;
    USE SIGNAL ;
    PORT
      LAYER M4 ;
        RECT  21.516 41.616 21.6 41.64 ;
    END
  END b[116]
  PIN b[117]
    DIRECTION OUTPUT ;
    USE SIGNAL ;
    PORT
      LAYER M4 ;
        RECT  21.516 41.76 21.6 41.784 ;
    END
  END b[117]
  PIN b[118]
    DIRECTION OUTPUT ;
    USE SIGNAL ;
    PORT
      LAYER M4 ;
        RECT  21.516 41.904 21.6 41.928 ;
    END
  END b[118]
  PIN b[119]
    DIRECTION OUTPUT ;
    USE SIGNAL ;
    PORT
      LAYER M4 ;
        RECT  21.516 42.048 21.6 42.072 ;
    END
  END b[119]
  PIN b[11]
    DIRECTION OUTPUT ;
    USE SIGNAL ;
    PORT
      LAYER M4 ;
        RECT  21.516 44.928 21.6 44.952 ;
    END
  END b[11]
  PIN b[120]
    DIRECTION OUTPUT ;
    USE SIGNAL ;
    PORT
      LAYER M4 ;
        RECT  21.516 42.192 21.6 42.216 ;
    END
  END b[120]
  PIN b[121]
    DIRECTION OUTPUT ;
    USE SIGNAL ;
    PORT
      LAYER M4 ;
        RECT  21.516 42.336 21.6 42.36 ;
    END
  END b[121]
  PIN b[122]
    DIRECTION OUTPUT ;
    USE SIGNAL ;
    PORT
      LAYER M4 ;
        RECT  21.516 42.48 21.6 42.504 ;
    END
  END b[122]
  PIN b[123]
    DIRECTION OUTPUT ;
    USE SIGNAL ;
    PORT
      LAYER M4 ;
        RECT  21.516 42.624 21.6 42.648 ;
    END
  END b[123]
  PIN b[124]
    DIRECTION OUTPUT ;
    USE SIGNAL ;
    PORT
      LAYER M4 ;
        RECT  21.516 42.768 21.6 42.792 ;
    END
  END b[124]
  PIN b[125]
    DIRECTION OUTPUT ;
    USE SIGNAL ;
    PORT
      LAYER M4 ;
        RECT  21.516 42.912 21.6 42.936 ;
    END
  END b[125]
  PIN b[126]
    DIRECTION OUTPUT ;
    USE SIGNAL ;
    PORT
      LAYER M4 ;
        RECT  21.516 43.056 21.6 43.08 ;
    END
  END b[126]
  PIN b[127]
    DIRECTION OUTPUT ;
    USE SIGNAL ;
    PORT
      LAYER M4 ;
        RECT  21.516 43.2 21.6 43.224 ;
    END
  END b[127]
  PIN b[128]
    DIRECTION OUTPUT ;
    USE SIGNAL ;
    PORT
      LAYER M4 ;
        RECT  21.516 47.952 21.6 47.976 ;
    END
  END b[128]
  PIN b[129]
    DIRECTION OUTPUT ;
    USE SIGNAL ;
    PORT
      LAYER M4 ;
        RECT  21.516 48.096 21.6 48.12 ;
    END
  END b[129]
  PIN b[12]
    DIRECTION OUTPUT ;
    USE SIGNAL ;
    PORT
      LAYER M4 ;
        RECT  21.516 45.072 21.6 45.096 ;
    END
  END b[12]
  PIN b[130]
    DIRECTION OUTPUT ;
    USE SIGNAL ;
    PORT
      LAYER M4 ;
        RECT  21.516 48.24 21.6 48.264 ;
    END
  END b[130]
  PIN b[131]
    DIRECTION OUTPUT ;
    USE SIGNAL ;
    PORT
      LAYER M4 ;
        RECT  21.516 48.384 21.6 48.408 ;
    END
  END b[131]
  PIN b[132]
    DIRECTION OUTPUT ;
    USE SIGNAL ;
    PORT
      LAYER M4 ;
        RECT  21.516 48.528 21.6 48.552 ;
    END
  END b[132]
  PIN b[133]
    DIRECTION OUTPUT ;
    USE SIGNAL ;
    PORT
      LAYER M4 ;
        RECT  21.516 48.672 21.6 48.696 ;
    END
  END b[133]
  PIN b[134]
    DIRECTION OUTPUT ;
    USE SIGNAL ;
    PORT
      LAYER M4 ;
        RECT  21.516 48.816 21.6 48.84 ;
    END
  END b[134]
  PIN b[135]
    DIRECTION OUTPUT ;
    USE SIGNAL ;
    PORT
      LAYER M4 ;
        RECT  21.516 48.96 21.6 48.984 ;
    END
  END b[135]
  PIN b[136]
    DIRECTION OUTPUT ;
    USE SIGNAL ;
    PORT
      LAYER M4 ;
        RECT  21.516 49.104 21.6 49.128 ;
    END
  END b[136]
  PIN b[137]
    DIRECTION OUTPUT ;
    USE SIGNAL ;
    PORT
      LAYER M4 ;
        RECT  21.516 49.248 21.6 49.272 ;
    END
  END b[137]
  PIN b[138]
    DIRECTION OUTPUT ;
    USE SIGNAL ;
    PORT
      LAYER M4 ;
        RECT  21.516 49.392 21.6 49.416 ;
    END
  END b[138]
  PIN b[139]
    DIRECTION OUTPUT ;
    USE SIGNAL ;
    PORT
      LAYER M4 ;
        RECT  21.516 49.536 21.6 49.56 ;
    END
  END b[139]
  PIN b[13]
    DIRECTION OUTPUT ;
    USE SIGNAL ;
    PORT
      LAYER M4 ;
        RECT  21.516 45.216 21.6 45.24 ;
    END
  END b[13]
  PIN b[140]
    DIRECTION OUTPUT ;
    USE SIGNAL ;
    PORT
      LAYER M4 ;
        RECT  21.516 49.68 21.6 49.704 ;
    END
  END b[140]
  PIN b[141]
    DIRECTION OUTPUT ;
    USE SIGNAL ;
    PORT
      LAYER M4 ;
        RECT  21.516 49.824 21.6 49.848 ;
    END
  END b[141]
  PIN b[142]
    DIRECTION OUTPUT ;
    USE SIGNAL ;
    PORT
      LAYER M4 ;
        RECT  21.516 49.968 21.6 49.992 ;
    END
  END b[142]
  PIN b[143]
    DIRECTION OUTPUT ;
    USE SIGNAL ;
    PORT
      LAYER M4 ;
        RECT  21.516 50.112 21.6 50.136 ;
    END
  END b[143]
  PIN b[144]
    DIRECTION OUTPUT ;
    USE SIGNAL ;
    PORT
      LAYER M4 ;
        RECT  21.516 50.256 21.6 50.28 ;
    END
  END b[144]
  PIN b[145]
    DIRECTION OUTPUT ;
    USE SIGNAL ;
    PORT
      LAYER M4 ;
        RECT  21.516 50.4 21.6 50.424 ;
    END
  END b[145]
  PIN b[146]
    DIRECTION OUTPUT ;
    USE SIGNAL ;
    PORT
      LAYER M4 ;
        RECT  21.516 50.544 21.6 50.568 ;
    END
  END b[146]
  PIN b[147]
    DIRECTION OUTPUT ;
    USE SIGNAL ;
    PORT
      LAYER M4 ;
        RECT  21.516 50.688 21.6 50.712 ;
    END
  END b[147]
  PIN b[148]
    DIRECTION OUTPUT ;
    USE SIGNAL ;
    PORT
      LAYER M4 ;
        RECT  21.516 50.832 21.6 50.856 ;
    END
  END b[148]
  PIN b[149]
    DIRECTION OUTPUT ;
    USE SIGNAL ;
    PORT
      LAYER M4 ;
        RECT  21.516 50.976 21.6 51 ;
    END
  END b[149]
  PIN b[14]
    DIRECTION OUTPUT ;
    USE SIGNAL ;
    PORT
      LAYER M4 ;
        RECT  21.516 45.36 21.6 45.384 ;
    END
  END b[14]
  PIN b[150]
    DIRECTION OUTPUT ;
    USE SIGNAL ;
    PORT
      LAYER M4 ;
        RECT  21.516 51.12 21.6 51.144 ;
    END
  END b[150]
  PIN b[151]
    DIRECTION OUTPUT ;
    USE SIGNAL ;
    PORT
      LAYER M4 ;
        RECT  21.516 51.264 21.6 51.288 ;
    END
  END b[151]
  PIN b[152]
    DIRECTION OUTPUT ;
    USE SIGNAL ;
    PORT
      LAYER M4 ;
        RECT  21.516 51.408 21.6 51.432 ;
    END
  END b[152]
  PIN b[153]
    DIRECTION OUTPUT ;
    USE SIGNAL ;
    PORT
      LAYER M4 ;
        RECT  21.516 51.552 21.6 51.576 ;
    END
  END b[153]
  PIN b[154]
    DIRECTION OUTPUT ;
    USE SIGNAL ;
    PORT
      LAYER M4 ;
        RECT  21.516 51.696 21.6 51.72 ;
    END
  END b[154]
  PIN b[155]
    DIRECTION OUTPUT ;
    USE SIGNAL ;
    PORT
      LAYER M4 ;
        RECT  21.516 51.84 21.6 51.864 ;
    END
  END b[155]
  PIN b[156]
    DIRECTION OUTPUT ;
    USE SIGNAL ;
    PORT
      LAYER M4 ;
        RECT  21.516 51.984 21.6 52.008 ;
    END
  END b[156]
  PIN b[157]
    DIRECTION OUTPUT ;
    USE SIGNAL ;
    PORT
      LAYER M4 ;
        RECT  21.516 52.128 21.6 52.152 ;
    END
  END b[157]
  PIN b[158]
    DIRECTION OUTPUT ;
    USE SIGNAL ;
    PORT
      LAYER M4 ;
        RECT  21.516 52.272 21.6 52.296 ;
    END
  END b[158]
  PIN b[159]
    DIRECTION OUTPUT ;
    USE SIGNAL ;
    PORT
      LAYER M4 ;
        RECT  21.516 52.416 21.6 52.44 ;
    END
  END b[159]
  PIN b[15]
    DIRECTION OUTPUT ;
    USE SIGNAL ;
    PORT
      LAYER M4 ;
        RECT  21.516 45.504 21.6 45.528 ;
    END
  END b[15]
  PIN b[160]
    DIRECTION OUTPUT ;
    USE SIGNAL ;
    PORT
      LAYER M4 ;
        RECT  21.516 52.56 21.6 52.584 ;
    END
  END b[160]
  PIN b[161]
    DIRECTION OUTPUT ;
    USE SIGNAL ;
    PORT
      LAYER M4 ;
        RECT  21.516 52.704 21.6 52.728 ;
    END
  END b[161]
  PIN b[162]
    DIRECTION OUTPUT ;
    USE SIGNAL ;
    PORT
      LAYER M4 ;
        RECT  21.516 52.848 21.6 52.872 ;
    END
  END b[162]
  PIN b[163]
    DIRECTION OUTPUT ;
    USE SIGNAL ;
    PORT
      LAYER M4 ;
        RECT  21.516 52.992 21.6 53.016 ;
    END
  END b[163]
  PIN b[164]
    DIRECTION OUTPUT ;
    USE SIGNAL ;
    PORT
      LAYER M4 ;
        RECT  21.516 53.136 21.6 53.16 ;
    END
  END b[164]
  PIN b[165]
    DIRECTION OUTPUT ;
    USE SIGNAL ;
    PORT
      LAYER M4 ;
        RECT  21.516 53.28 21.6 53.304 ;
    END
  END b[165]
  PIN b[166]
    DIRECTION OUTPUT ;
    USE SIGNAL ;
    PORT
      LAYER M4 ;
        RECT  21.516 53.424 21.6 53.448 ;
    END
  END b[166]
  PIN b[167]
    DIRECTION OUTPUT ;
    USE SIGNAL ;
    PORT
      LAYER M4 ;
        RECT  21.516 53.568 21.6 53.592 ;
    END
  END b[167]
  PIN b[168]
    DIRECTION OUTPUT ;
    USE SIGNAL ;
    PORT
      LAYER M4 ;
        RECT  21.516 53.712 21.6 53.736 ;
    END
  END b[168]
  PIN b[169]
    DIRECTION OUTPUT ;
    USE SIGNAL ;
    PORT
      LAYER M4 ;
        RECT  21.516 53.856 21.6 53.88 ;
    END
  END b[169]
  PIN b[16]
    DIRECTION OUTPUT ;
    USE SIGNAL ;
    PORT
      LAYER M4 ;
        RECT  21.516 45.648 21.6 45.672 ;
    END
  END b[16]
  PIN b[170]
    DIRECTION OUTPUT ;
    USE SIGNAL ;
    PORT
      LAYER M4 ;
        RECT  21.516 54 21.6 54.024 ;
    END
  END b[170]
  PIN b[171]
    DIRECTION OUTPUT ;
    USE SIGNAL ;
    PORT
      LAYER M4 ;
        RECT  21.516 54.144 21.6 54.168 ;
    END
  END b[171]
  PIN b[172]
    DIRECTION OUTPUT ;
    USE SIGNAL ;
    PORT
      LAYER M4 ;
        RECT  21.516 54.288 21.6 54.312 ;
    END
  END b[172]
  PIN b[173]
    DIRECTION OUTPUT ;
    USE SIGNAL ;
    PORT
      LAYER M4 ;
        RECT  21.516 54.432 21.6 54.456 ;
    END
  END b[173]
  PIN b[174]
    DIRECTION OUTPUT ;
    USE SIGNAL ;
    PORT
      LAYER M4 ;
        RECT  21.516 54.576 21.6 54.6 ;
    END
  END b[174]
  PIN b[175]
    DIRECTION OUTPUT ;
    USE SIGNAL ;
    PORT
      LAYER M4 ;
        RECT  21.516 54.72 21.6 54.744 ;
    END
  END b[175]
  PIN b[176]
    DIRECTION OUTPUT ;
    USE SIGNAL ;
    PORT
      LAYER M4 ;
        RECT  21.516 54.864 21.6 54.888 ;
    END
  END b[176]
  PIN b[177]
    DIRECTION OUTPUT ;
    USE SIGNAL ;
    PORT
      LAYER M4 ;
        RECT  21.516 55.008 21.6 55.032 ;
    END
  END b[177]
  PIN b[178]
    DIRECTION OUTPUT ;
    USE SIGNAL ;
    PORT
      LAYER M4 ;
        RECT  21.516 55.152 21.6 55.176 ;
    END
  END b[178]
  PIN b[179]
    DIRECTION OUTPUT ;
    USE SIGNAL ;
    PORT
      LAYER M4 ;
        RECT  21.516 55.296 21.6 55.32 ;
    END
  END b[179]
  PIN b[17]
    DIRECTION OUTPUT ;
    USE SIGNAL ;
    PORT
      LAYER M4 ;
        RECT  21.516 45.792 21.6 45.816 ;
    END
  END b[17]
  PIN b[180]
    DIRECTION OUTPUT ;
    USE SIGNAL ;
    PORT
      LAYER M4 ;
        RECT  21.516 55.44 21.6 55.464 ;
    END
  END b[180]
  PIN b[181]
    DIRECTION OUTPUT ;
    USE SIGNAL ;
    PORT
      LAYER M4 ;
        RECT  21.516 55.584 21.6 55.608 ;
    END
  END b[181]
  PIN b[182]
    DIRECTION OUTPUT ;
    USE SIGNAL ;
    PORT
      LAYER M4 ;
        RECT  21.516 55.728 21.6 55.752 ;
    END
  END b[182]
  PIN b[183]
    DIRECTION OUTPUT ;
    USE SIGNAL ;
    PORT
      LAYER M4 ;
        RECT  21.516 55.872 21.6 55.896 ;
    END
  END b[183]
  PIN b[184]
    DIRECTION OUTPUT ;
    USE SIGNAL ;
    PORT
      LAYER M4 ;
        RECT  21.516 56.016 21.6 56.04 ;
    END
  END b[184]
  PIN b[185]
    DIRECTION OUTPUT ;
    USE SIGNAL ;
    PORT
      LAYER M4 ;
        RECT  21.516 56.16 21.6 56.184 ;
    END
  END b[185]
  PIN b[186]
    DIRECTION OUTPUT ;
    USE SIGNAL ;
    PORT
      LAYER M4 ;
        RECT  21.516 56.304 21.6 56.328 ;
    END
  END b[186]
  PIN b[187]
    DIRECTION OUTPUT ;
    USE SIGNAL ;
    PORT
      LAYER M4 ;
        RECT  21.516 56.448 21.6 56.472 ;
    END
  END b[187]
  PIN b[188]
    DIRECTION OUTPUT ;
    USE SIGNAL ;
    PORT
      LAYER M4 ;
        RECT  21.516 56.592 21.6 56.616 ;
    END
  END b[188]
  PIN b[189]
    DIRECTION OUTPUT ;
    USE SIGNAL ;
    PORT
      LAYER M4 ;
        RECT  21.516 56.736 21.6 56.76 ;
    END
  END b[189]
  PIN b[18]
    DIRECTION OUTPUT ;
    USE SIGNAL ;
    PORT
      LAYER M4 ;
        RECT  21.516 45.936 21.6 45.96 ;
    END
  END b[18]
  PIN b[190]
    DIRECTION OUTPUT ;
    USE SIGNAL ;
    PORT
      LAYER M4 ;
        RECT  21.516 56.88 21.6 56.904 ;
    END
  END b[190]
  PIN b[191]
    DIRECTION OUTPUT ;
    USE SIGNAL ;
    PORT
      LAYER M4 ;
        RECT  21.516 57.024 21.6 57.048 ;
    END
  END b[191]
  PIN b[192]
    DIRECTION OUTPUT ;
    USE SIGNAL ;
    PORT
      LAYER M4 ;
        RECT  21.516 62.928 21.6 62.952 ;
    END
  END b[192]
  PIN b[193]
    DIRECTION OUTPUT ;
    USE SIGNAL ;
    PORT
      LAYER M4 ;
        RECT  21.516 63.072 21.6 63.096 ;
    END
  END b[193]
  PIN b[194]
    DIRECTION OUTPUT ;
    USE SIGNAL ;
    PORT
      LAYER M4 ;
        RECT  21.516 63.216 21.6 63.24 ;
    END
  END b[194]
  PIN b[195]
    DIRECTION OUTPUT ;
    USE SIGNAL ;
    PORT
      LAYER M4 ;
        RECT  21.516 63.36 21.6 63.384 ;
    END
  END b[195]
  PIN b[196]
    DIRECTION OUTPUT ;
    USE SIGNAL ;
    PORT
      LAYER M4 ;
        RECT  21.516 63.504 21.6 63.528 ;
    END
  END b[196]
  PIN b[197]
    DIRECTION OUTPUT ;
    USE SIGNAL ;
    PORT
      LAYER M4 ;
        RECT  21.516 63.648 21.6 63.672 ;
    END
  END b[197]
  PIN b[198]
    DIRECTION OUTPUT ;
    USE SIGNAL ;
    PORT
      LAYER M4 ;
        RECT  21.516 63.792 21.6 63.816 ;
    END
  END b[198]
  PIN b[199]
    DIRECTION OUTPUT ;
    USE SIGNAL ;
    PORT
      LAYER M4 ;
        RECT  21.516 63.936 21.6 63.96 ;
    END
  END b[199]
  PIN b[19]
    DIRECTION OUTPUT ;
    USE SIGNAL ;
    PORT
      LAYER M4 ;
        RECT  21.516 46.08 21.6 46.104 ;
    END
  END b[19]
  PIN b[1]
    DIRECTION OUTPUT ;
    USE SIGNAL ;
    PORT
      LAYER M4 ;
        RECT  21.516 43.488 21.6 43.512 ;
    END
  END b[1]
  PIN b[200]
    DIRECTION OUTPUT ;
    USE SIGNAL ;
    PORT
      LAYER M4 ;
        RECT  21.516 64.08 21.6 64.104 ;
    END
  END b[200]
  PIN b[201]
    DIRECTION OUTPUT ;
    USE SIGNAL ;
    PORT
      LAYER M4 ;
        RECT  21.516 64.224 21.6 64.248 ;
    END
  END b[201]
  PIN b[202]
    DIRECTION OUTPUT ;
    USE SIGNAL ;
    PORT
      LAYER M4 ;
        RECT  21.516 64.368 21.6 64.392 ;
    END
  END b[202]
  PIN b[203]
    DIRECTION OUTPUT ;
    USE SIGNAL ;
    PORT
      LAYER M4 ;
        RECT  21.516 64.512 21.6 64.536 ;
    END
  END b[203]
  PIN b[204]
    DIRECTION OUTPUT ;
    USE SIGNAL ;
    PORT
      LAYER M4 ;
        RECT  21.516 64.656 21.6 64.68 ;
    END
  END b[204]
  PIN b[205]
    DIRECTION OUTPUT ;
    USE SIGNAL ;
    PORT
      LAYER M4 ;
        RECT  21.516 64.8 21.6 64.824 ;
    END
  END b[205]
  PIN b[206]
    DIRECTION OUTPUT ;
    USE SIGNAL ;
    PORT
      LAYER M4 ;
        RECT  21.516 64.944 21.6 64.968 ;
    END
  END b[206]
  PIN b[207]
    DIRECTION OUTPUT ;
    USE SIGNAL ;
    PORT
      LAYER M4 ;
        RECT  21.516 65.088 21.6 65.112 ;
    END
  END b[207]
  PIN b[208]
    DIRECTION OUTPUT ;
    USE SIGNAL ;
    PORT
      LAYER M4 ;
        RECT  21.516 65.232 21.6 65.256 ;
    END
  END b[208]
  PIN b[209]
    DIRECTION OUTPUT ;
    USE SIGNAL ;
    PORT
      LAYER M4 ;
        RECT  21.516 65.376 21.6 65.4 ;
    END
  END b[209]
  PIN b[20]
    DIRECTION OUTPUT ;
    USE SIGNAL ;
    PORT
      LAYER M4 ;
        RECT  21.516 46.224 21.6 46.248 ;
    END
  END b[20]
  PIN b[210]
    DIRECTION OUTPUT ;
    USE SIGNAL ;
    PORT
      LAYER M4 ;
        RECT  21.516 65.52 21.6 65.544 ;
    END
  END b[210]
  PIN b[211]
    DIRECTION OUTPUT ;
    USE SIGNAL ;
    PORT
      LAYER M4 ;
        RECT  21.516 65.664 21.6 65.688 ;
    END
  END b[211]
  PIN b[212]
    DIRECTION OUTPUT ;
    USE SIGNAL ;
    PORT
      LAYER M4 ;
        RECT  21.516 65.808 21.6 65.832 ;
    END
  END b[212]
  PIN b[213]
    DIRECTION OUTPUT ;
    USE SIGNAL ;
    PORT
      LAYER M4 ;
        RECT  21.516 65.952 21.6 65.976 ;
    END
  END b[213]
  PIN b[214]
    DIRECTION OUTPUT ;
    USE SIGNAL ;
    PORT
      LAYER M4 ;
        RECT  21.516 66.096 21.6 66.12 ;
    END
  END b[214]
  PIN b[215]
    DIRECTION OUTPUT ;
    USE SIGNAL ;
    PORT
      LAYER M4 ;
        RECT  21.516 66.24 21.6 66.264 ;
    END
  END b[215]
  PIN b[216]
    DIRECTION OUTPUT ;
    USE SIGNAL ;
    PORT
      LAYER M4 ;
        RECT  21.516 66.384 21.6 66.408 ;
    END
  END b[216]
  PIN b[217]
    DIRECTION OUTPUT ;
    USE SIGNAL ;
    PORT
      LAYER M4 ;
        RECT  21.516 66.528 21.6 66.552 ;
    END
  END b[217]
  PIN b[218]
    DIRECTION OUTPUT ;
    USE SIGNAL ;
    PORT
      LAYER M4 ;
        RECT  21.516 66.672 21.6 66.696 ;
    END
  END b[218]
  PIN b[219]
    DIRECTION OUTPUT ;
    USE SIGNAL ;
    PORT
      LAYER M4 ;
        RECT  21.516 66.816 21.6 66.84 ;
    END
  END b[219]
  PIN b[21]
    DIRECTION OUTPUT ;
    USE SIGNAL ;
    PORT
      LAYER M4 ;
        RECT  21.516 46.368 21.6 46.392 ;
    END
  END b[21]
  PIN b[220]
    DIRECTION OUTPUT ;
    USE SIGNAL ;
    PORT
      LAYER M4 ;
        RECT  21.516 66.96 21.6 66.984 ;
    END
  END b[220]
  PIN b[221]
    DIRECTION OUTPUT ;
    USE SIGNAL ;
    PORT
      LAYER M4 ;
        RECT  21.516 67.104 21.6 67.128 ;
    END
  END b[221]
  PIN b[222]
    DIRECTION OUTPUT ;
    USE SIGNAL ;
    PORT
      LAYER M4 ;
        RECT  21.516 67.248 21.6 67.272 ;
    END
  END b[222]
  PIN b[223]
    DIRECTION OUTPUT ;
    USE SIGNAL ;
    PORT
      LAYER M4 ;
        RECT  21.516 67.392 21.6 67.416 ;
    END
  END b[223]
  PIN b[224]
    DIRECTION OUTPUT ;
    USE SIGNAL ;
    PORT
      LAYER M4 ;
        RECT  21.516 58.32 21.6 58.344 ;
    END
  END b[224]
  PIN b[225]
    DIRECTION OUTPUT ;
    USE SIGNAL ;
    PORT
      LAYER M4 ;
        RECT  21.516 58.464 21.6 58.488 ;
    END
  END b[225]
  PIN b[226]
    DIRECTION OUTPUT ;
    USE SIGNAL ;
    PORT
      LAYER M4 ;
        RECT  21.516 58.608 21.6 58.632 ;
    END
  END b[226]
  PIN b[227]
    DIRECTION OUTPUT ;
    USE SIGNAL ;
    PORT
      LAYER M4 ;
        RECT  21.516 58.752 21.6 58.776 ;
    END
  END b[227]
  PIN b[228]
    DIRECTION OUTPUT ;
    USE SIGNAL ;
    PORT
      LAYER M4 ;
        RECT  21.516 58.896 21.6 58.92 ;
    END
  END b[228]
  PIN b[229]
    DIRECTION OUTPUT ;
    USE SIGNAL ;
    PORT
      LAYER M4 ;
        RECT  21.516 59.04 21.6 59.064 ;
    END
  END b[229]
  PIN b[22]
    DIRECTION OUTPUT ;
    USE SIGNAL ;
    PORT
      LAYER M4 ;
        RECT  21.516 46.512 21.6 46.536 ;
    END
  END b[22]
  PIN b[230]
    DIRECTION OUTPUT ;
    USE SIGNAL ;
    PORT
      LAYER M4 ;
        RECT  21.516 59.184 21.6 59.208 ;
    END
  END b[230]
  PIN b[231]
    DIRECTION OUTPUT ;
    USE SIGNAL ;
    PORT
      LAYER M4 ;
        RECT  21.516 59.328 21.6 59.352 ;
    END
  END b[231]
  PIN b[232]
    DIRECTION OUTPUT ;
    USE SIGNAL ;
    PORT
      LAYER M4 ;
        RECT  21.516 59.472 21.6 59.496 ;
    END
  END b[232]
  PIN b[233]
    DIRECTION OUTPUT ;
    USE SIGNAL ;
    PORT
      LAYER M4 ;
        RECT  21.516 59.616 21.6 59.64 ;
    END
  END b[233]
  PIN b[234]
    DIRECTION OUTPUT ;
    USE SIGNAL ;
    PORT
      LAYER M4 ;
        RECT  21.516 59.76 21.6 59.784 ;
    END
  END b[234]
  PIN b[235]
    DIRECTION OUTPUT ;
    USE SIGNAL ;
    PORT
      LAYER M4 ;
        RECT  21.516 59.904 21.6 59.928 ;
    END
  END b[235]
  PIN b[236]
    DIRECTION OUTPUT ;
    USE SIGNAL ;
    PORT
      LAYER M4 ;
        RECT  21.516 60.048 21.6 60.072 ;
    END
  END b[236]
  PIN b[237]
    DIRECTION OUTPUT ;
    USE SIGNAL ;
    PORT
      LAYER M4 ;
        RECT  21.516 60.192 21.6 60.216 ;
    END
  END b[237]
  PIN b[238]
    DIRECTION OUTPUT ;
    USE SIGNAL ;
    PORT
      LAYER M4 ;
        RECT  21.516 60.336 21.6 60.36 ;
    END
  END b[238]
  PIN b[239]
    DIRECTION OUTPUT ;
    USE SIGNAL ;
    PORT
      LAYER M4 ;
        RECT  21.516 60.48 21.6 60.504 ;
    END
  END b[239]
  PIN b[23]
    DIRECTION OUTPUT ;
    USE SIGNAL ;
    PORT
      LAYER M4 ;
        RECT  21.516 46.656 21.6 46.68 ;
    END
  END b[23]
  PIN b[240]
    DIRECTION OUTPUT ;
    USE SIGNAL ;
    PORT
      LAYER M4 ;
        RECT  21.516 60.624 21.6 60.648 ;
    END
  END b[240]
  PIN b[241]
    DIRECTION OUTPUT ;
    USE SIGNAL ;
    PORT
      LAYER M4 ;
        RECT  21.516 60.768 21.6 60.792 ;
    END
  END b[241]
  PIN b[242]
    DIRECTION OUTPUT ;
    USE SIGNAL ;
    PORT
      LAYER M4 ;
        RECT  21.516 60.912 21.6 60.936 ;
    END
  END b[242]
  PIN b[243]
    DIRECTION OUTPUT ;
    USE SIGNAL ;
    PORT
      LAYER M4 ;
        RECT  21.516 61.056 21.6 61.08 ;
    END
  END b[243]
  PIN b[244]
    DIRECTION OUTPUT ;
    USE SIGNAL ;
    PORT
      LAYER M4 ;
        RECT  21.516 61.2 21.6 61.224 ;
    END
  END b[244]
  PIN b[245]
    DIRECTION OUTPUT ;
    USE SIGNAL ;
    PORT
      LAYER M4 ;
        RECT  21.516 61.344 21.6 61.368 ;
    END
  END b[245]
  PIN b[246]
    DIRECTION OUTPUT ;
    USE SIGNAL ;
    PORT
      LAYER M4 ;
        RECT  21.516 61.488 21.6 61.512 ;
    END
  END b[246]
  PIN b[247]
    DIRECTION OUTPUT ;
    USE SIGNAL ;
    PORT
      LAYER M4 ;
        RECT  21.516 61.632 21.6 61.656 ;
    END
  END b[247]
  PIN b[248]
    DIRECTION OUTPUT ;
    USE SIGNAL ;
    PORT
      LAYER M4 ;
        RECT  21.516 61.776 21.6 61.8 ;
    END
  END b[248]
  PIN b[249]
    DIRECTION OUTPUT ;
    USE SIGNAL ;
    PORT
      LAYER M4 ;
        RECT  21.516 61.92 21.6 61.944 ;
    END
  END b[249]
  PIN b[24]
    DIRECTION OUTPUT ;
    USE SIGNAL ;
    PORT
      LAYER M4 ;
        RECT  21.516 46.8 21.6 46.824 ;
    END
  END b[24]
  PIN b[250]
    DIRECTION OUTPUT ;
    USE SIGNAL ;
    PORT
      LAYER M4 ;
        RECT  21.516 62.064 21.6 62.088 ;
    END
  END b[250]
  PIN b[251]
    DIRECTION OUTPUT ;
    USE SIGNAL ;
    PORT
      LAYER M4 ;
        RECT  21.516 62.208 21.6 62.232 ;
    END
  END b[251]
  PIN b[252]
    DIRECTION OUTPUT ;
    USE SIGNAL ;
    PORT
      LAYER M4 ;
        RECT  21.516 62.352 21.6 62.376 ;
    END
  END b[252]
  PIN b[253]
    DIRECTION OUTPUT ;
    USE SIGNAL ;
    PORT
      LAYER M4 ;
        RECT  21.516 62.496 21.6 62.52 ;
    END
  END b[253]
  PIN b[254]
    DIRECTION OUTPUT ;
    USE SIGNAL ;
    PORT
      LAYER M4 ;
        RECT  21.516 62.64 21.6 62.664 ;
    END
  END b[254]
  PIN b[255]
    DIRECTION OUTPUT ;
    USE SIGNAL ;
    PORT
      LAYER M4 ;
        RECT  21.516 62.784 21.6 62.808 ;
    END
  END b[255]
  PIN b[256]
    DIRECTION OUTPUT ;
    USE SIGNAL ;
    PORT
      LAYER M4 ;
        RECT  21.516 57.168 21.6 57.192 ;
    END
  END b[256]
  PIN b[257]
    DIRECTION OUTPUT ;
    USE SIGNAL ;
    PORT
      LAYER M4 ;
        RECT  21.516 57.312 21.6 57.336 ;
    END
  END b[257]
  PIN b[25]
    DIRECTION OUTPUT ;
    USE SIGNAL ;
    PORT
      LAYER M4 ;
        RECT  21.516 46.944 21.6 46.968 ;
    END
  END b[25]
  PIN b[26]
    DIRECTION OUTPUT ;
    USE SIGNAL ;
    PORT
      LAYER M4 ;
        RECT  21.516 47.088 21.6 47.112 ;
    END
  END b[26]
  PIN b[27]
    DIRECTION OUTPUT ;
    USE SIGNAL ;
    PORT
      LAYER M4 ;
        RECT  21.516 47.232 21.6 47.256 ;
    END
  END b[27]
  PIN b[28]
    DIRECTION OUTPUT ;
    USE SIGNAL ;
    PORT
      LAYER M4 ;
        RECT  21.516 47.376 21.6 47.4 ;
    END
  END b[28]
  PIN b[29]
    DIRECTION OUTPUT ;
    USE SIGNAL ;
    PORT
      LAYER M4 ;
        RECT  21.516 47.52 21.6 47.544 ;
    END
  END b[29]
  PIN b[2]
    DIRECTION OUTPUT ;
    USE SIGNAL ;
    PORT
      LAYER M4 ;
        RECT  21.516 43.632 21.6 43.656 ;
    END
  END b[2]
  PIN b[30]
    DIRECTION OUTPUT ;
    USE SIGNAL ;
    PORT
      LAYER M4 ;
        RECT  21.516 47.664 21.6 47.688 ;
    END
  END b[30]
  PIN b[31]
    DIRECTION OUTPUT ;
    USE SIGNAL ;
    PORT
      LAYER M4 ;
        RECT  21.516 47.808 21.6 47.832 ;
    END
  END b[31]
  PIN b[32]
    DIRECTION OUTPUT ;
    USE SIGNAL ;
    PORT
      LAYER M4 ;
        RECT  21.516 34.128 21.6 34.152 ;
    END
  END b[32]
  PIN b[33]
    DIRECTION OUTPUT ;
    USE SIGNAL ;
    PORT
      LAYER M4 ;
        RECT  21.516 34.272 21.6 34.296 ;
    END
  END b[33]
  PIN b[34]
    DIRECTION OUTPUT ;
    USE SIGNAL ;
    PORT
      LAYER M4 ;
        RECT  21.516 34.416 21.6 34.44 ;
    END
  END b[34]
  PIN b[35]
    DIRECTION OUTPUT ;
    USE SIGNAL ;
    PORT
      LAYER M4 ;
        RECT  21.516 34.56 21.6 34.584 ;
    END
  END b[35]
  PIN b[36]
    DIRECTION OUTPUT ;
    USE SIGNAL ;
    PORT
      LAYER M4 ;
        RECT  21.516 34.704 21.6 34.728 ;
    END
  END b[36]
  PIN b[37]
    DIRECTION OUTPUT ;
    USE SIGNAL ;
    PORT
      LAYER M4 ;
        RECT  21.516 34.848 21.6 34.872 ;
    END
  END b[37]
  PIN b[38]
    DIRECTION OUTPUT ;
    USE SIGNAL ;
    PORT
      LAYER M4 ;
        RECT  21.516 34.992 21.6 35.016 ;
    END
  END b[38]
  PIN b[39]
    DIRECTION OUTPUT ;
    USE SIGNAL ;
    PORT
      LAYER M4 ;
        RECT  21.516 35.136 21.6 35.16 ;
    END
  END b[39]
  PIN b[3]
    DIRECTION OUTPUT ;
    USE SIGNAL ;
    PORT
      LAYER M4 ;
        RECT  21.516 43.776 21.6 43.8 ;
    END
  END b[3]
  PIN b[40]
    DIRECTION OUTPUT ;
    USE SIGNAL ;
    PORT
      LAYER M4 ;
        RECT  21.516 35.28 21.6 35.304 ;
    END
  END b[40]
  PIN b[41]
    DIRECTION OUTPUT ;
    USE SIGNAL ;
    PORT
      LAYER M4 ;
        RECT  21.516 35.424 21.6 35.448 ;
    END
  END b[41]
  PIN b[42]
    DIRECTION OUTPUT ;
    USE SIGNAL ;
    PORT
      LAYER M4 ;
        RECT  21.516 35.568 21.6 35.592 ;
    END
  END b[42]
  PIN b[43]
    DIRECTION OUTPUT ;
    USE SIGNAL ;
    PORT
      LAYER M4 ;
        RECT  21.516 35.712 21.6 35.736 ;
    END
  END b[43]
  PIN b[44]
    DIRECTION OUTPUT ;
    USE SIGNAL ;
    PORT
      LAYER M4 ;
        RECT  21.516 35.856 21.6 35.88 ;
    END
  END b[44]
  PIN b[45]
    DIRECTION OUTPUT ;
    USE SIGNAL ;
    PORT
      LAYER M4 ;
        RECT  21.516 36 21.6 36.024 ;
    END
  END b[45]
  PIN b[46]
    DIRECTION OUTPUT ;
    USE SIGNAL ;
    PORT
      LAYER M4 ;
        RECT  21.516 36.144 21.6 36.168 ;
    END
  END b[46]
  PIN b[47]
    DIRECTION OUTPUT ;
    USE SIGNAL ;
    PORT
      LAYER M4 ;
        RECT  21.516 36.288 21.6 36.312 ;
    END
  END b[47]
  PIN b[48]
    DIRECTION OUTPUT ;
    USE SIGNAL ;
    PORT
      LAYER M4 ;
        RECT  21.516 36.432 21.6 36.456 ;
    END
  END b[48]
  PIN b[49]
    DIRECTION OUTPUT ;
    USE SIGNAL ;
    PORT
      LAYER M4 ;
        RECT  21.516 36.576 21.6 36.6 ;
    END
  END b[49]
  PIN b[4]
    DIRECTION OUTPUT ;
    USE SIGNAL ;
    PORT
      LAYER M4 ;
        RECT  21.516 43.92 21.6 43.944 ;
    END
  END b[4]
  PIN b[50]
    DIRECTION OUTPUT ;
    USE SIGNAL ;
    PORT
      LAYER M4 ;
        RECT  21.516 36.72 21.6 36.744 ;
    END
  END b[50]
  PIN b[51]
    DIRECTION OUTPUT ;
    USE SIGNAL ;
    PORT
      LAYER M4 ;
        RECT  21.516 36.864 21.6 36.888 ;
    END
  END b[51]
  PIN b[52]
    DIRECTION OUTPUT ;
    USE SIGNAL ;
    PORT
      LAYER M4 ;
        RECT  21.516 37.008 21.6 37.032 ;
    END
  END b[52]
  PIN b[53]
    DIRECTION OUTPUT ;
    USE SIGNAL ;
    PORT
      LAYER M4 ;
        RECT  21.516 37.152 21.6 37.176 ;
    END
  END b[53]
  PIN b[54]
    DIRECTION OUTPUT ;
    USE SIGNAL ;
    PORT
      LAYER M4 ;
        RECT  21.516 37.296 21.6 37.32 ;
    END
  END b[54]
  PIN b[55]
    DIRECTION OUTPUT ;
    USE SIGNAL ;
    PORT
      LAYER M4 ;
        RECT  21.516 37.44 21.6 37.464 ;
    END
  END b[55]
  PIN b[56]
    DIRECTION OUTPUT ;
    USE SIGNAL ;
    PORT
      LAYER M4 ;
        RECT  21.516 37.584 21.6 37.608 ;
    END
  END b[56]
  PIN b[57]
    DIRECTION OUTPUT ;
    USE SIGNAL ;
    PORT
      LAYER M4 ;
        RECT  21.516 37.728 21.6 37.752 ;
    END
  END b[57]
  PIN b[58]
    DIRECTION OUTPUT ;
    USE SIGNAL ;
    PORT
      LAYER M4 ;
        RECT  21.516 37.872 21.6 37.896 ;
    END
  END b[58]
  PIN b[59]
    DIRECTION OUTPUT ;
    USE SIGNAL ;
    PORT
      LAYER M4 ;
        RECT  21.516 38.016 21.6 38.04 ;
    END
  END b[59]
  PIN b[5]
    DIRECTION OUTPUT ;
    USE SIGNAL ;
    PORT
      LAYER M4 ;
        RECT  21.516 44.064 21.6 44.088 ;
    END
  END b[5]
  PIN b[60]
    DIRECTION OUTPUT ;
    USE SIGNAL ;
    PORT
      LAYER M4 ;
        RECT  21.516 38.16 21.6 38.184 ;
    END
  END b[60]
  PIN b[61]
    DIRECTION OUTPUT ;
    USE SIGNAL ;
    PORT
      LAYER M4 ;
        RECT  21.516 38.304 21.6 38.328 ;
    END
  END b[61]
  PIN b[62]
    DIRECTION OUTPUT ;
    USE SIGNAL ;
    PORT
      LAYER M4 ;
        RECT  21.516 38.448 21.6 38.472 ;
    END
  END b[62]
  PIN b[63]
    DIRECTION OUTPUT ;
    USE SIGNAL ;
    PORT
      LAYER M4 ;
        RECT  21.516 38.592 21.6 38.616 ;
    END
  END b[63]
  PIN b[64]
    DIRECTION OUTPUT ;
    USE SIGNAL ;
    PORT
      LAYER M4 ;
        RECT  21.516 29.52 21.6 29.544 ;
    END
  END b[64]
  PIN b[65]
    DIRECTION OUTPUT ;
    USE SIGNAL ;
    PORT
      LAYER M4 ;
        RECT  21.516 29.664 21.6 29.688 ;
    END
  END b[65]
  PIN b[66]
    DIRECTION OUTPUT ;
    USE SIGNAL ;
    PORT
      LAYER M4 ;
        RECT  21.516 29.808 21.6 29.832 ;
    END
  END b[66]
  PIN b[67]
    DIRECTION OUTPUT ;
    USE SIGNAL ;
    PORT
      LAYER M4 ;
        RECT  21.516 29.952 21.6 29.976 ;
    END
  END b[67]
  PIN b[68]
    DIRECTION OUTPUT ;
    USE SIGNAL ;
    PORT
      LAYER M4 ;
        RECT  21.516 30.096 21.6 30.12 ;
    END
  END b[68]
  PIN b[69]
    DIRECTION OUTPUT ;
    USE SIGNAL ;
    PORT
      LAYER M4 ;
        RECT  21.516 30.24 21.6 30.264 ;
    END
  END b[69]
  PIN b[6]
    DIRECTION OUTPUT ;
    USE SIGNAL ;
    PORT
      LAYER M4 ;
        RECT  21.516 44.208 21.6 44.232 ;
    END
  END b[6]
  PIN b[70]
    DIRECTION OUTPUT ;
    USE SIGNAL ;
    PORT
      LAYER M4 ;
        RECT  21.516 30.384 21.6 30.408 ;
    END
  END b[70]
  PIN b[71]
    DIRECTION OUTPUT ;
    USE SIGNAL ;
    PORT
      LAYER M4 ;
        RECT  21.516 30.528 21.6 30.552 ;
    END
  END b[71]
  PIN b[72]
    DIRECTION OUTPUT ;
    USE SIGNAL ;
    PORT
      LAYER M4 ;
        RECT  21.516 30.672 21.6 30.696 ;
    END
  END b[72]
  PIN b[73]
    DIRECTION OUTPUT ;
    USE SIGNAL ;
    PORT
      LAYER M4 ;
        RECT  21.516 30.816 21.6 30.84 ;
    END
  END b[73]
  PIN b[74]
    DIRECTION OUTPUT ;
    USE SIGNAL ;
    PORT
      LAYER M4 ;
        RECT  21.516 30.96 21.6 30.984 ;
    END
  END b[74]
  PIN b[75]
    DIRECTION OUTPUT ;
    USE SIGNAL ;
    PORT
      LAYER M4 ;
        RECT  21.516 31.104 21.6 31.128 ;
    END
  END b[75]
  PIN b[76]
    DIRECTION OUTPUT ;
    USE SIGNAL ;
    PORT
      LAYER M4 ;
        RECT  21.516 31.248 21.6 31.272 ;
    END
  END b[76]
  PIN b[77]
    DIRECTION OUTPUT ;
    USE SIGNAL ;
    PORT
      LAYER M4 ;
        RECT  21.516 31.392 21.6 31.416 ;
    END
  END b[77]
  PIN b[78]
    DIRECTION OUTPUT ;
    USE SIGNAL ;
    PORT
      LAYER M4 ;
        RECT  21.516 31.536 21.6 31.56 ;
    END
  END b[78]
  PIN b[79]
    DIRECTION OUTPUT ;
    USE SIGNAL ;
    PORT
      LAYER M4 ;
        RECT  21.516 31.68 21.6 31.704 ;
    END
  END b[79]
  PIN b[7]
    DIRECTION OUTPUT ;
    USE SIGNAL ;
    PORT
      LAYER M4 ;
        RECT  21.516 44.352 21.6 44.376 ;
    END
  END b[7]
  PIN b[80]
    DIRECTION OUTPUT ;
    USE SIGNAL ;
    PORT
      LAYER M4 ;
        RECT  21.516 31.824 21.6 31.848 ;
    END
  END b[80]
  PIN b[81]
    DIRECTION OUTPUT ;
    USE SIGNAL ;
    PORT
      LAYER M4 ;
        RECT  21.516 31.968 21.6 31.992 ;
    END
  END b[81]
  PIN b[82]
    DIRECTION OUTPUT ;
    USE SIGNAL ;
    PORT
      LAYER M4 ;
        RECT  21.516 32.112 21.6 32.136 ;
    END
  END b[82]
  PIN b[83]
    DIRECTION OUTPUT ;
    USE SIGNAL ;
    PORT
      LAYER M4 ;
        RECT  21.516 32.256 21.6 32.28 ;
    END
  END b[83]
  PIN b[84]
    DIRECTION OUTPUT ;
    USE SIGNAL ;
    PORT
      LAYER M4 ;
        RECT  21.516 32.4 21.6 32.424 ;
    END
  END b[84]
  PIN b[85]
    DIRECTION OUTPUT ;
    USE SIGNAL ;
    PORT
      LAYER M4 ;
        RECT  21.516 32.544 21.6 32.568 ;
    END
  END b[85]
  PIN b[86]
    DIRECTION OUTPUT ;
    USE SIGNAL ;
    PORT
      LAYER M4 ;
        RECT  21.516 32.688 21.6 32.712 ;
    END
  END b[86]
  PIN b[87]
    DIRECTION OUTPUT ;
    USE SIGNAL ;
    PORT
      LAYER M4 ;
        RECT  21.516 32.832 21.6 32.856 ;
    END
  END b[87]
  PIN b[88]
    DIRECTION OUTPUT ;
    USE SIGNAL ;
    PORT
      LAYER M4 ;
        RECT  21.516 32.976 21.6 33 ;
    END
  END b[88]
  PIN b[89]
    DIRECTION OUTPUT ;
    USE SIGNAL ;
    PORT
      LAYER M4 ;
        RECT  21.516 33.12 21.6 33.144 ;
    END
  END b[89]
  PIN b[8]
    DIRECTION OUTPUT ;
    USE SIGNAL ;
    PORT
      LAYER M4 ;
        RECT  21.516 44.496 21.6 44.52 ;
    END
  END b[8]
  PIN b[90]
    DIRECTION OUTPUT ;
    USE SIGNAL ;
    PORT
      LAYER M4 ;
        RECT  21.516 33.264 21.6 33.288 ;
    END
  END b[90]
  PIN b[91]
    DIRECTION OUTPUT ;
    USE SIGNAL ;
    PORT
      LAYER M4 ;
        RECT  21.516 33.408 21.6 33.432 ;
    END
  END b[91]
  PIN b[92]
    DIRECTION OUTPUT ;
    USE SIGNAL ;
    PORT
      LAYER M4 ;
        RECT  21.516 33.552 21.6 33.576 ;
    END
  END b[92]
  PIN b[93]
    DIRECTION OUTPUT ;
    USE SIGNAL ;
    PORT
      LAYER M4 ;
        RECT  21.516 33.696 21.6 33.72 ;
    END
  END b[93]
  PIN b[94]
    DIRECTION OUTPUT ;
    USE SIGNAL ;
    PORT
      LAYER M4 ;
        RECT  21.516 33.84 21.6 33.864 ;
    END
  END b[94]
  PIN b[95]
    DIRECTION OUTPUT ;
    USE SIGNAL ;
    PORT
      LAYER M4 ;
        RECT  21.516 33.984 21.6 34.008 ;
    END
  END b[95]
  PIN b[96]
    DIRECTION OUTPUT ;
    USE SIGNAL ;
    PORT
      LAYER M4 ;
        RECT  21.516 38.736 21.6 38.76 ;
    END
  END b[96]
  PIN b[97]
    DIRECTION OUTPUT ;
    USE SIGNAL ;
    PORT
      LAYER M4 ;
        RECT  21.516 38.88 21.6 38.904 ;
    END
  END b[97]
  PIN b[98]
    DIRECTION OUTPUT ;
    USE SIGNAL ;
    PORT
      LAYER M4 ;
        RECT  21.516 39.024 21.6 39.048 ;
    END
  END b[98]
  PIN b[99]
    DIRECTION OUTPUT ;
    USE SIGNAL ;
    PORT
      LAYER M4 ;
        RECT  21.516 39.168 21.6 39.192 ;
    END
  END b[99]
  PIN b[9]
    DIRECTION OUTPUT ;
    USE SIGNAL ;
    PORT
      LAYER M4 ;
        RECT  21.516 44.64 21.6 44.664 ;
    END
  END b[9]
  PIN ck
    DIRECTION INPUT ;
    USE SIGNAL ;
    PORT
      LAYER M5 ;
        RECT  11.808 0 11.832 0.084 ;
    END
    PORT
      LAYER M5 ;
        RECT  11.808 0.016 11.832 36.997 ;
    END
  END ck
  PIN s
    DIRECTION INPUT ;
    USE SIGNAL ;
    PORT
      LAYER M5 ;
        RECT  14.112 0 14.136 0.084 ;
    END
    PORT
      LAYER M5 ;
        RECT  14.112 0.016 14.136 0.563 ;
    END
  END s
  PIN y[0]
    DIRECTION INPUT ;
    USE SIGNAL ;
    PORT
      LAYER M4 ;
        RECT  0 32.4 0.084 32.424 ;
    END
  END y[0]
  PIN y[100]
    DIRECTION INPUT ;
    USE SIGNAL ;
    PORT
      LAYER M4 ;
        RECT  0 23.76 0.084 23.784 ;
    END
  END y[100]
  PIN y[101]
    DIRECTION INPUT ;
    USE SIGNAL ;
    PORT
      LAYER M4 ;
        RECT  0 23.904 0.084 23.928 ;
    END
  END y[101]
  PIN y[102]
    DIRECTION INPUT ;
    USE SIGNAL ;
    PORT
      LAYER M4 ;
        RECT  0 24.048 0.084 24.072 ;
    END
  END y[102]
  PIN y[103]
    DIRECTION INPUT ;
    USE SIGNAL ;
    PORT
      LAYER M4 ;
        RECT  0 24.192 0.084 24.216 ;
    END
  END y[103]
  PIN y[104]
    DIRECTION INPUT ;
    USE SIGNAL ;
    PORT
      LAYER M4 ;
        RECT  0 24.336 0.084 24.36 ;
    END
  END y[104]
  PIN y[105]
    DIRECTION INPUT ;
    USE SIGNAL ;
    PORT
      LAYER M4 ;
        RECT  0 24.48 0.084 24.504 ;
    END
  END y[105]
  PIN y[106]
    DIRECTION INPUT ;
    USE SIGNAL ;
    PORT
      LAYER M4 ;
        RECT  0 24.624 0.084 24.648 ;
    END
  END y[106]
  PIN y[107]
    DIRECTION INPUT ;
    USE SIGNAL ;
    PORT
      LAYER M4 ;
        RECT  0 24.768 0.084 24.792 ;
    END
  END y[107]
  PIN y[108]
    DIRECTION INPUT ;
    USE SIGNAL ;
    PORT
      LAYER M4 ;
        RECT  0 24.912 0.084 24.936 ;
    END
  END y[108]
  PIN y[109]
    DIRECTION INPUT ;
    USE SIGNAL ;
    PORT
      LAYER M4 ;
        RECT  0 25.056 0.084 25.08 ;
    END
  END y[109]
  PIN y[10]
    DIRECTION INPUT ;
    USE SIGNAL ;
    PORT
      LAYER M4 ;
        RECT  0 33.84 0.084 33.864 ;
    END
  END y[10]
  PIN y[110]
    DIRECTION INPUT ;
    USE SIGNAL ;
    PORT
      LAYER M4 ;
        RECT  0 25.2 0.084 25.224 ;
    END
  END y[110]
  PIN y[111]
    DIRECTION INPUT ;
    USE SIGNAL ;
    PORT
      LAYER M4 ;
        RECT  0 25.344 0.084 25.368 ;
    END
  END y[111]
  PIN y[112]
    DIRECTION INPUT ;
    USE SIGNAL ;
    PORT
      LAYER M4 ;
        RECT  0 25.488 0.084 25.512 ;
    END
  END y[112]
  PIN y[113]
    DIRECTION INPUT ;
    USE SIGNAL ;
    PORT
      LAYER M4 ;
        RECT  0 25.632 0.084 25.656 ;
    END
  END y[113]
  PIN y[114]
    DIRECTION INPUT ;
    USE SIGNAL ;
    PORT
      LAYER M4 ;
        RECT  0 25.776 0.084 25.8 ;
    END
  END y[114]
  PIN y[115]
    DIRECTION INPUT ;
    USE SIGNAL ;
    PORT
      LAYER M4 ;
        RECT  0 25.92 0.084 25.944 ;
    END
  END y[115]
  PIN y[116]
    DIRECTION INPUT ;
    USE SIGNAL ;
    PORT
      LAYER M4 ;
        RECT  0 26.064 0.084 26.088 ;
    END
  END y[116]
  PIN y[117]
    DIRECTION INPUT ;
    USE SIGNAL ;
    PORT
      LAYER M4 ;
        RECT  0 26.208 0.084 26.232 ;
    END
  END y[117]
  PIN y[118]
    DIRECTION INPUT ;
    USE SIGNAL ;
    PORT
      LAYER M4 ;
        RECT  0 26.352 0.084 26.376 ;
    END
  END y[118]
  PIN y[119]
    DIRECTION INPUT ;
    USE SIGNAL ;
    PORT
      LAYER M4 ;
        RECT  0 26.496 0.084 26.52 ;
    END
  END y[119]
  PIN y[11]
    DIRECTION INPUT ;
    USE SIGNAL ;
    PORT
      LAYER M4 ;
        RECT  0 33.984 0.084 34.008 ;
    END
  END y[11]
  PIN y[120]
    DIRECTION INPUT ;
    USE SIGNAL ;
    PORT
      LAYER M4 ;
        RECT  0 26.64 0.084 26.664 ;
    END
  END y[120]
  PIN y[121]
    DIRECTION INPUT ;
    USE SIGNAL ;
    PORT
      LAYER M4 ;
        RECT  0 26.784 0.084 26.808 ;
    END
  END y[121]
  PIN y[122]
    DIRECTION INPUT ;
    USE SIGNAL ;
    PORT
      LAYER M4 ;
        RECT  0 26.928 0.084 26.952 ;
    END
  END y[122]
  PIN y[123]
    DIRECTION INPUT ;
    USE SIGNAL ;
    PORT
      LAYER M4 ;
        RECT  0 27.072 0.084 27.096 ;
    END
  END y[123]
  PIN y[124]
    DIRECTION INPUT ;
    USE SIGNAL ;
    PORT
      LAYER M4 ;
        RECT  0 27.216 0.084 27.24 ;
    END
  END y[124]
  PIN y[125]
    DIRECTION INPUT ;
    USE SIGNAL ;
    PORT
      LAYER M4 ;
        RECT  0 27.36 0.084 27.384 ;
    END
  END y[125]
  PIN y[126]
    DIRECTION INPUT ;
    USE SIGNAL ;
    PORT
      LAYER M4 ;
        RECT  0 80.496 0.084 80.52 ;
    END
  END y[126]
  PIN y[127]
    DIRECTION INPUT ;
    USE SIGNAL ;
    PORT
      LAYER M4 ;
        RECT  0 80.64 0.084 80.664 ;
    END
  END y[127]
  PIN y[128]
    DIRECTION INPUT ;
    USE SIGNAL ;
    PORT
      LAYER M4 ;
        RECT  0 80.784 0.084 80.808 ;
    END
  END y[128]
  PIN y[129]
    DIRECTION INPUT ;
    USE SIGNAL ;
    PORT
      LAYER M4 ;
        RECT  0 80.928 0.084 80.952 ;
    END
  END y[129]
  PIN y[12]
    DIRECTION INPUT ;
    USE SIGNAL ;
    PORT
      LAYER M4 ;
        RECT  0 34.128 0.084 34.152 ;
    END
  END y[12]
  PIN y[130]
    DIRECTION INPUT ;
    USE SIGNAL ;
    PORT
      LAYER M4 ;
        RECT  0 81.072 0.084 81.096 ;
    END
  END y[130]
  PIN y[131]
    DIRECTION INPUT ;
    USE SIGNAL ;
    PORT
      LAYER M4 ;
        RECT  0 81.216 0.084 81.24 ;
    END
  END y[131]
  PIN y[132]
    DIRECTION INPUT ;
    USE SIGNAL ;
    PORT
      LAYER M4 ;
        RECT  0 81.36 0.084 81.384 ;
    END
  END y[132]
  PIN y[133]
    DIRECTION INPUT ;
    USE SIGNAL ;
    PORT
      LAYER M4 ;
        RECT  0 81.504 0.084 81.528 ;
    END
  END y[133]
  PIN y[134]
    DIRECTION INPUT ;
    USE SIGNAL ;
    PORT
      LAYER M4 ;
        RECT  0 81.648 0.084 81.672 ;
    END
  END y[134]
  PIN y[135]
    DIRECTION INPUT ;
    USE SIGNAL ;
    PORT
      LAYER M4 ;
        RECT  0 81.792 0.084 81.816 ;
    END
  END y[135]
  PIN y[136]
    DIRECTION INPUT ;
    USE SIGNAL ;
    PORT
      LAYER M4 ;
        RECT  0 81.936 0.084 81.96 ;
    END
  END y[136]
  PIN y[137]
    DIRECTION INPUT ;
    USE SIGNAL ;
    PORT
      LAYER M4 ;
        RECT  0 82.08 0.084 82.104 ;
    END
  END y[137]
  PIN y[138]
    DIRECTION INPUT ;
    USE SIGNAL ;
    PORT
      LAYER M4 ;
        RECT  0 82.224 0.084 82.248 ;
    END
  END y[138]
  PIN y[139]
    DIRECTION INPUT ;
    USE SIGNAL ;
    PORT
      LAYER M4 ;
        RECT  0 82.368 0.084 82.392 ;
    END
  END y[139]
  PIN y[13]
    DIRECTION INPUT ;
    USE SIGNAL ;
    PORT
      LAYER M4 ;
        RECT  0 34.272 0.084 34.296 ;
    END
  END y[13]
  PIN y[140]
    DIRECTION INPUT ;
    USE SIGNAL ;
    PORT
      LAYER M4 ;
        RECT  0 82.512 0.084 82.536 ;
    END
  END y[140]
  PIN y[141]
    DIRECTION INPUT ;
    USE SIGNAL ;
    PORT
      LAYER M4 ;
        RECT  0 82.656 0.084 82.68 ;
    END
  END y[141]
  PIN y[142]
    DIRECTION INPUT ;
    USE SIGNAL ;
    PORT
      LAYER M4 ;
        RECT  0 82.8 0.084 82.824 ;
    END
  END y[142]
  PIN y[143]
    DIRECTION INPUT ;
    USE SIGNAL ;
    PORT
      LAYER M4 ;
        RECT  0 82.944 0.084 82.968 ;
    END
  END y[143]
  PIN y[144]
    DIRECTION INPUT ;
    USE SIGNAL ;
    PORT
      LAYER M4 ;
        RECT  0 83.088 0.084 83.112 ;
    END
  END y[144]
  PIN y[145]
    DIRECTION INPUT ;
    USE SIGNAL ;
    PORT
      LAYER M4 ;
        RECT  0 83.232 0.084 83.256 ;
    END
  END y[145]
  PIN y[146]
    DIRECTION INPUT ;
    USE SIGNAL ;
    PORT
      LAYER M4 ;
        RECT  0 83.376 0.084 83.4 ;
    END
  END y[146]
  PIN y[147]
    DIRECTION INPUT ;
    USE SIGNAL ;
    PORT
      LAYER M4 ;
        RECT  0 83.52 0.084 83.544 ;
    END
  END y[147]
  PIN y[148]
    DIRECTION INPUT ;
    USE SIGNAL ;
    PORT
      LAYER M4 ;
        RECT  0 83.664 0.084 83.688 ;
    END
  END y[148]
  PIN y[149]
    DIRECTION INPUT ;
    USE SIGNAL ;
    PORT
      LAYER M4 ;
        RECT  0 83.808 0.084 83.832 ;
    END
  END y[149]
  PIN y[14]
    DIRECTION INPUT ;
    USE SIGNAL ;
    PORT
      LAYER M4 ;
        RECT  0 34.416 0.084 34.44 ;
    END
  END y[14]
  PIN y[150]
    DIRECTION INPUT ;
    USE SIGNAL ;
    PORT
      LAYER M4 ;
        RECT  0 83.952 0.084 83.976 ;
    END
  END y[150]
  PIN y[151]
    DIRECTION INPUT ;
    USE SIGNAL ;
    PORT
      LAYER M4 ;
        RECT  0 84.096 0.084 84.12 ;
    END
  END y[151]
  PIN y[152]
    DIRECTION INPUT ;
    USE SIGNAL ;
    PORT
      LAYER M4 ;
        RECT  0 84.24 0.084 84.264 ;
    END
  END y[152]
  PIN y[153]
    DIRECTION INPUT ;
    USE SIGNAL ;
    PORT
      LAYER M4 ;
        RECT  0 84.384 0.084 84.408 ;
    END
  END y[153]
  PIN y[154]
    DIRECTION INPUT ;
    USE SIGNAL ;
    PORT
      LAYER M4 ;
        RECT  0 84.528 0.084 84.552 ;
    END
  END y[154]
  PIN y[155]
    DIRECTION INPUT ;
    USE SIGNAL ;
    PORT
      LAYER M4 ;
        RECT  0 84.672 0.084 84.696 ;
    END
  END y[155]
  PIN y[156]
    DIRECTION INPUT ;
    USE SIGNAL ;
    PORT
      LAYER M4 ;
        RECT  0 84.816 0.084 84.84 ;
    END
  END y[156]
  PIN y[157]
    DIRECTION INPUT ;
    USE SIGNAL ;
    PORT
      LAYER M4 ;
        RECT  0 84.96 0.084 84.984 ;
    END
  END y[157]
  PIN y[158]
    DIRECTION INPUT ;
    USE SIGNAL ;
    PORT
      LAYER M4 ;
        RECT  0 75.888 0.084 75.912 ;
    END
  END y[158]
  PIN y[159]
    DIRECTION INPUT ;
    USE SIGNAL ;
    PORT
      LAYER M4 ;
        RECT  0 76.032 0.084 76.056 ;
    END
  END y[159]
  PIN y[15]
    DIRECTION INPUT ;
    USE SIGNAL ;
    PORT
      LAYER M4 ;
        RECT  0 34.56 0.084 34.584 ;
    END
  END y[15]
  PIN y[160]
    DIRECTION INPUT ;
    USE SIGNAL ;
    PORT
      LAYER M4 ;
        RECT  0 76.176 0.084 76.2 ;
    END
  END y[160]
  PIN y[161]
    DIRECTION INPUT ;
    USE SIGNAL ;
    PORT
      LAYER M4 ;
        RECT  0 76.32 0.084 76.344 ;
    END
  END y[161]
  PIN y[162]
    DIRECTION INPUT ;
    USE SIGNAL ;
    PORT
      LAYER M4 ;
        RECT  0 76.464 0.084 76.488 ;
    END
  END y[162]
  PIN y[163]
    DIRECTION INPUT ;
    USE SIGNAL ;
    PORT
      LAYER M4 ;
        RECT  0 76.608 0.084 76.632 ;
    END
  END y[163]
  PIN y[164]
    DIRECTION INPUT ;
    USE SIGNAL ;
    PORT
      LAYER M4 ;
        RECT  0 76.752 0.084 76.776 ;
    END
  END y[164]
  PIN y[165]
    DIRECTION INPUT ;
    USE SIGNAL ;
    PORT
      LAYER M4 ;
        RECT  0 76.896 0.084 76.92 ;
    END
  END y[165]
  PIN y[166]
    DIRECTION INPUT ;
    USE SIGNAL ;
    PORT
      LAYER M4 ;
        RECT  0 77.04 0.084 77.064 ;
    END
  END y[166]
  PIN y[167]
    DIRECTION INPUT ;
    USE SIGNAL ;
    PORT
      LAYER M4 ;
        RECT  0 77.184 0.084 77.208 ;
    END
  END y[167]
  PIN y[168]
    DIRECTION INPUT ;
    USE SIGNAL ;
    PORT
      LAYER M4 ;
        RECT  0 77.328 0.084 77.352 ;
    END
  END y[168]
  PIN y[169]
    DIRECTION INPUT ;
    USE SIGNAL ;
    PORT
      LAYER M4 ;
        RECT  0 77.472 0.084 77.496 ;
    END
  END y[169]
  PIN y[16]
    DIRECTION INPUT ;
    USE SIGNAL ;
    PORT
      LAYER M4 ;
        RECT  0 34.704 0.084 34.728 ;
    END
  END y[16]
  PIN y[170]
    DIRECTION INPUT ;
    USE SIGNAL ;
    PORT
      LAYER M4 ;
        RECT  0 77.616 0.084 77.64 ;
    END
  END y[170]
  PIN y[171]
    DIRECTION INPUT ;
    USE SIGNAL ;
    PORT
      LAYER M4 ;
        RECT  0 77.76 0.084 77.784 ;
    END
  END y[171]
  PIN y[172]
    DIRECTION INPUT ;
    USE SIGNAL ;
    PORT
      LAYER M4 ;
        RECT  0 77.904 0.084 77.928 ;
    END
  END y[172]
  PIN y[173]
    DIRECTION INPUT ;
    USE SIGNAL ;
    PORT
      LAYER M4 ;
        RECT  0 78.048 0.084 78.072 ;
    END
  END y[173]
  PIN y[174]
    DIRECTION INPUT ;
    USE SIGNAL ;
    PORT
      LAYER M4 ;
        RECT  0 78.192 0.084 78.216 ;
    END
  END y[174]
  PIN y[175]
    DIRECTION INPUT ;
    USE SIGNAL ;
    PORT
      LAYER M4 ;
        RECT  0 78.336 0.084 78.36 ;
    END
  END y[175]
  PIN y[176]
    DIRECTION INPUT ;
    USE SIGNAL ;
    PORT
      LAYER M4 ;
        RECT  0 78.48 0.084 78.504 ;
    END
  END y[176]
  PIN y[177]
    DIRECTION INPUT ;
    USE SIGNAL ;
    PORT
      LAYER M4 ;
        RECT  0 78.624 0.084 78.648 ;
    END
  END y[177]
  PIN y[178]
    DIRECTION INPUT ;
    USE SIGNAL ;
    PORT
      LAYER M4 ;
        RECT  0 78.768 0.084 78.792 ;
    END
  END y[178]
  PIN y[179]
    DIRECTION INPUT ;
    USE SIGNAL ;
    PORT
      LAYER M4 ;
        RECT  0 78.912 0.084 78.936 ;
    END
  END y[179]
  PIN y[17]
    DIRECTION INPUT ;
    USE SIGNAL ;
    PORT
      LAYER M4 ;
        RECT  0 34.848 0.084 34.872 ;
    END
  END y[17]
  PIN y[180]
    DIRECTION INPUT ;
    USE SIGNAL ;
    PORT
      LAYER M4 ;
        RECT  0 79.056 0.084 79.08 ;
    END
  END y[180]
  PIN y[181]
    DIRECTION INPUT ;
    USE SIGNAL ;
    PORT
      LAYER M4 ;
        RECT  0 79.2 0.084 79.224 ;
    END
  END y[181]
  PIN y[182]
    DIRECTION INPUT ;
    USE SIGNAL ;
    PORT
      LAYER M4 ;
        RECT  0 79.344 0.084 79.368 ;
    END
  END y[182]
  PIN y[183]
    DIRECTION INPUT ;
    USE SIGNAL ;
    PORT
      LAYER M4 ;
        RECT  0 79.488 0.084 79.512 ;
    END
  END y[183]
  PIN y[184]
    DIRECTION INPUT ;
    USE SIGNAL ;
    PORT
      LAYER M4 ;
        RECT  0 79.632 0.084 79.656 ;
    END
  END y[184]
  PIN y[185]
    DIRECTION INPUT ;
    USE SIGNAL ;
    PORT
      LAYER M4 ;
        RECT  0 79.776 0.084 79.8 ;
    END
  END y[185]
  PIN y[186]
    DIRECTION INPUT ;
    USE SIGNAL ;
    PORT
      LAYER M4 ;
        RECT  0 79.92 0.084 79.944 ;
    END
  END y[186]
  PIN y[187]
    DIRECTION INPUT ;
    USE SIGNAL ;
    PORT
      LAYER M4 ;
        RECT  0 80.064 0.084 80.088 ;
    END
  END y[187]
  PIN y[188]
    DIRECTION INPUT ;
    USE SIGNAL ;
    PORT
      LAYER M4 ;
        RECT  0 80.208 0.084 80.232 ;
    END
  END y[188]
  PIN y[189]
    DIRECTION INPUT ;
    USE SIGNAL ;
    PORT
      LAYER M4 ;
        RECT  0 80.352 0.084 80.376 ;
    END
  END y[189]
  PIN y[18]
    DIRECTION INPUT ;
    USE SIGNAL ;
    PORT
      LAYER M4 ;
        RECT  0 34.992 0.084 35.016 ;
    END
  END y[18]
  PIN y[190]
    DIRECTION INPUT ;
    USE SIGNAL ;
    PORT
      LAYER M4 ;
        RECT  0 71.28 0.084 71.304 ;
    END
  END y[190]
  PIN y[191]
    DIRECTION INPUT ;
    USE SIGNAL ;
    PORT
      LAYER M4 ;
        RECT  0 71.424 0.084 71.448 ;
    END
  END y[191]
  PIN y[192]
    DIRECTION INPUT ;
    USE SIGNAL ;
    PORT
      LAYER M4 ;
        RECT  0 71.568 0.084 71.592 ;
    END
  END y[192]
  PIN y[193]
    DIRECTION INPUT ;
    USE SIGNAL ;
    PORT
      LAYER M4 ;
        RECT  0 71.712 0.084 71.736 ;
    END
  END y[193]
  PIN y[194]
    DIRECTION INPUT ;
    USE SIGNAL ;
    PORT
      LAYER M4 ;
        RECT  0 71.856 0.084 71.88 ;
    END
  END y[194]
  PIN y[195]
    DIRECTION INPUT ;
    USE SIGNAL ;
    PORT
      LAYER M4 ;
        RECT  0 72 0.084 72.024 ;
    END
  END y[195]
  PIN y[196]
    DIRECTION INPUT ;
    USE SIGNAL ;
    PORT
      LAYER M4 ;
        RECT  0 72.144 0.084 72.168 ;
    END
  END y[196]
  PIN y[197]
    DIRECTION INPUT ;
    USE SIGNAL ;
    PORT
      LAYER M4 ;
        RECT  0 72.288 0.084 72.312 ;
    END
  END y[197]
  PIN y[198]
    DIRECTION INPUT ;
    USE SIGNAL ;
    PORT
      LAYER M4 ;
        RECT  0 72.432 0.084 72.456 ;
    END
  END y[198]
  PIN y[199]
    DIRECTION INPUT ;
    USE SIGNAL ;
    PORT
      LAYER M4 ;
        RECT  0 72.576 0.084 72.6 ;
    END
  END y[199]
  PIN y[19]
    DIRECTION INPUT ;
    USE SIGNAL ;
    PORT
      LAYER M4 ;
        RECT  0 35.136 0.084 35.16 ;
    END
  END y[19]
  PIN y[1]
    DIRECTION INPUT ;
    USE SIGNAL ;
    PORT
      LAYER M4 ;
        RECT  0 32.544 0.084 32.568 ;
    END
  END y[1]
  PIN y[200]
    DIRECTION INPUT ;
    USE SIGNAL ;
    PORT
      LAYER M4 ;
        RECT  0 72.72 0.084 72.744 ;
    END
  END y[200]
  PIN y[201]
    DIRECTION INPUT ;
    USE SIGNAL ;
    PORT
      LAYER M4 ;
        RECT  0 72.864 0.084 72.888 ;
    END
  END y[201]
  PIN y[202]
    DIRECTION INPUT ;
    USE SIGNAL ;
    PORT
      LAYER M4 ;
        RECT  0 73.008 0.084 73.032 ;
    END
  END y[202]
  PIN y[203]
    DIRECTION INPUT ;
    USE SIGNAL ;
    PORT
      LAYER M4 ;
        RECT  0 73.152 0.084 73.176 ;
    END
  END y[203]
  PIN y[204]
    DIRECTION INPUT ;
    USE SIGNAL ;
    PORT
      LAYER M4 ;
        RECT  0 73.296 0.084 73.32 ;
    END
  END y[204]
  PIN y[205]
    DIRECTION INPUT ;
    USE SIGNAL ;
    PORT
      LAYER M4 ;
        RECT  0 73.44 0.084 73.464 ;
    END
  END y[205]
  PIN y[206]
    DIRECTION INPUT ;
    USE SIGNAL ;
    PORT
      LAYER M4 ;
        RECT  0 73.584 0.084 73.608 ;
    END
  END y[206]
  PIN y[207]
    DIRECTION INPUT ;
    USE SIGNAL ;
    PORT
      LAYER M4 ;
        RECT  0 73.728 0.084 73.752 ;
    END
  END y[207]
  PIN y[208]
    DIRECTION INPUT ;
    USE SIGNAL ;
    PORT
      LAYER M4 ;
        RECT  0 73.872 0.084 73.896 ;
    END
  END y[208]
  PIN y[209]
    DIRECTION INPUT ;
    USE SIGNAL ;
    PORT
      LAYER M4 ;
        RECT  0 74.016 0.084 74.04 ;
    END
  END y[209]
  PIN y[20]
    DIRECTION INPUT ;
    USE SIGNAL ;
    PORT
      LAYER M4 ;
        RECT  0 35.28 0.084 35.304 ;
    END
  END y[20]
  PIN y[210]
    DIRECTION INPUT ;
    USE SIGNAL ;
    PORT
      LAYER M4 ;
        RECT  0 74.16 0.084 74.184 ;
    END
  END y[210]
  PIN y[211]
    DIRECTION INPUT ;
    USE SIGNAL ;
    PORT
      LAYER M4 ;
        RECT  0 74.304 0.084 74.328 ;
    END
  END y[211]
  PIN y[212]
    DIRECTION INPUT ;
    USE SIGNAL ;
    PORT
      LAYER M4 ;
        RECT  0 74.448 0.084 74.472 ;
    END
  END y[212]
  PIN y[213]
    DIRECTION INPUT ;
    USE SIGNAL ;
    PORT
      LAYER M4 ;
        RECT  0 74.592 0.084 74.616 ;
    END
  END y[213]
  PIN y[214]
    DIRECTION INPUT ;
    USE SIGNAL ;
    PORT
      LAYER M4 ;
        RECT  0 74.736 0.084 74.76 ;
    END
  END y[214]
  PIN y[215]
    DIRECTION INPUT ;
    USE SIGNAL ;
    PORT
      LAYER M4 ;
        RECT  0 74.88 0.084 74.904 ;
    END
  END y[215]
  PIN y[216]
    DIRECTION INPUT ;
    USE SIGNAL ;
    PORT
      LAYER M4 ;
        RECT  0 75.024 0.084 75.048 ;
    END
  END y[216]
  PIN y[217]
    DIRECTION INPUT ;
    USE SIGNAL ;
    PORT
      LAYER M4 ;
        RECT  0 75.168 0.084 75.192 ;
    END
  END y[217]
  PIN y[218]
    DIRECTION INPUT ;
    USE SIGNAL ;
    PORT
      LAYER M4 ;
        RECT  0 75.312 0.084 75.336 ;
    END
  END y[218]
  PIN y[219]
    DIRECTION INPUT ;
    USE SIGNAL ;
    PORT
      LAYER M4 ;
        RECT  0 75.456 0.084 75.48 ;
    END
  END y[219]
  PIN y[21]
    DIRECTION INPUT ;
    USE SIGNAL ;
    PORT
      LAYER M4 ;
        RECT  0 35.424 0.084 35.448 ;
    END
  END y[21]
  PIN y[220]
    DIRECTION INPUT ;
    USE SIGNAL ;
    PORT
      LAYER M4 ;
        RECT  0 75.6 0.084 75.624 ;
    END
  END y[220]
  PIN y[221]
    DIRECTION INPUT ;
    USE SIGNAL ;
    PORT
      LAYER M4 ;
        RECT  0 75.744 0.084 75.768 ;
    END
  END y[221]
  PIN y[222]
    DIRECTION INPUT ;
    USE SIGNAL ;
    PORT
      LAYER M4 ;
        RECT  0 66.672 0.084 66.696 ;
    END
  END y[222]
  PIN y[223]
    DIRECTION INPUT ;
    USE SIGNAL ;
    PORT
      LAYER M4 ;
        RECT  0 66.816 0.084 66.84 ;
    END
  END y[223]
  PIN y[224]
    DIRECTION INPUT ;
    USE SIGNAL ;
    PORT
      LAYER M4 ;
        RECT  0 66.96 0.084 66.984 ;
    END
  END y[224]
  PIN y[225]
    DIRECTION INPUT ;
    USE SIGNAL ;
    PORT
      LAYER M4 ;
        RECT  0 67.104 0.084 67.128 ;
    END
  END y[225]
  PIN y[226]
    DIRECTION INPUT ;
    USE SIGNAL ;
    PORT
      LAYER M4 ;
        RECT  0 67.248 0.084 67.272 ;
    END
  END y[226]
  PIN y[227]
    DIRECTION INPUT ;
    USE SIGNAL ;
    PORT
      LAYER M4 ;
        RECT  0 67.392 0.084 67.416 ;
    END
  END y[227]
  PIN y[228]
    DIRECTION INPUT ;
    USE SIGNAL ;
    PORT
      LAYER M4 ;
        RECT  0 67.536 0.084 67.56 ;
    END
  END y[228]
  PIN y[229]
    DIRECTION INPUT ;
    USE SIGNAL ;
    PORT
      LAYER M4 ;
        RECT  0 67.68 0.084 67.704 ;
    END
  END y[229]
  PIN y[22]
    DIRECTION INPUT ;
    USE SIGNAL ;
    PORT
      LAYER M4 ;
        RECT  0 35.568 0.084 35.592 ;
    END
  END y[22]
  PIN y[230]
    DIRECTION INPUT ;
    USE SIGNAL ;
    PORT
      LAYER M4 ;
        RECT  0 67.824 0.084 67.848 ;
    END
  END y[230]
  PIN y[231]
    DIRECTION INPUT ;
    USE SIGNAL ;
    PORT
      LAYER M4 ;
        RECT  0 67.968 0.084 67.992 ;
    END
  END y[231]
  PIN y[232]
    DIRECTION INPUT ;
    USE SIGNAL ;
    PORT
      LAYER M4 ;
        RECT  0 68.112 0.084 68.136 ;
    END
  END y[232]
  PIN y[233]
    DIRECTION INPUT ;
    USE SIGNAL ;
    PORT
      LAYER M4 ;
        RECT  0 68.256 0.084 68.28 ;
    END
  END y[233]
  PIN y[234]
    DIRECTION INPUT ;
    USE SIGNAL ;
    PORT
      LAYER M4 ;
        RECT  0 68.4 0.084 68.424 ;
    END
  END y[234]
  PIN y[235]
    DIRECTION INPUT ;
    USE SIGNAL ;
    PORT
      LAYER M4 ;
        RECT  0 68.544 0.084 68.568 ;
    END
  END y[235]
  PIN y[236]
    DIRECTION INPUT ;
    USE SIGNAL ;
    PORT
      LAYER M4 ;
        RECT  0 68.688 0.084 68.712 ;
    END
  END y[236]
  PIN y[237]
    DIRECTION INPUT ;
    USE SIGNAL ;
    PORT
      LAYER M4 ;
        RECT  0 68.832 0.084 68.856 ;
    END
  END y[237]
  PIN y[238]
    DIRECTION INPUT ;
    USE SIGNAL ;
    PORT
      LAYER M4 ;
        RECT  0 68.976 0.084 69 ;
    END
  END y[238]
  PIN y[239]
    DIRECTION INPUT ;
    USE SIGNAL ;
    PORT
      LAYER M4 ;
        RECT  0 69.12 0.084 69.144 ;
    END
  END y[239]
  PIN y[23]
    DIRECTION INPUT ;
    USE SIGNAL ;
    PORT
      LAYER M4 ;
        RECT  0 35.712 0.084 35.736 ;
    END
  END y[23]
  PIN y[240]
    DIRECTION INPUT ;
    USE SIGNAL ;
    PORT
      LAYER M4 ;
        RECT  0 69.264 0.084 69.288 ;
    END
  END y[240]
  PIN y[241]
    DIRECTION INPUT ;
    USE SIGNAL ;
    PORT
      LAYER M4 ;
        RECT  0 69.408 0.084 69.432 ;
    END
  END y[241]
  PIN y[242]
    DIRECTION INPUT ;
    USE SIGNAL ;
    PORT
      LAYER M4 ;
        RECT  0 69.552 0.084 69.576 ;
    END
  END y[242]
  PIN y[243]
    DIRECTION INPUT ;
    USE SIGNAL ;
    PORT
      LAYER M4 ;
        RECT  0 69.696 0.084 69.72 ;
    END
  END y[243]
  PIN y[244]
    DIRECTION INPUT ;
    USE SIGNAL ;
    PORT
      LAYER M4 ;
        RECT  0 69.84 0.084 69.864 ;
    END
  END y[244]
  PIN y[245]
    DIRECTION INPUT ;
    USE SIGNAL ;
    PORT
      LAYER M4 ;
        RECT  0 69.984 0.084 70.008 ;
    END
  END y[245]
  PIN y[246]
    DIRECTION INPUT ;
    USE SIGNAL ;
    PORT
      LAYER M4 ;
        RECT  0 70.128 0.084 70.152 ;
    END
  END y[246]
  PIN y[247]
    DIRECTION INPUT ;
    USE SIGNAL ;
    PORT
      LAYER M4 ;
        RECT  0 70.272 0.084 70.296 ;
    END
  END y[247]
  PIN y[248]
    DIRECTION INPUT ;
    USE SIGNAL ;
    PORT
      LAYER M4 ;
        RECT  0 70.416 0.084 70.44 ;
    END
  END y[248]
  PIN y[249]
    DIRECTION INPUT ;
    USE SIGNAL ;
    PORT
      LAYER M4 ;
        RECT  0 70.56 0.084 70.584 ;
    END
  END y[249]
  PIN y[24]
    DIRECTION INPUT ;
    USE SIGNAL ;
    PORT
      LAYER M4 ;
        RECT  0 35.856 0.084 35.88 ;
    END
  END y[24]
  PIN y[250]
    DIRECTION INPUT ;
    USE SIGNAL ;
    PORT
      LAYER M4 ;
        RECT  0 70.704 0.084 70.728 ;
    END
  END y[250]
  PIN y[251]
    DIRECTION INPUT ;
    USE SIGNAL ;
    PORT
      LAYER M4 ;
        RECT  0 70.848 0.084 70.872 ;
    END
  END y[251]
  PIN y[252]
    DIRECTION INPUT ;
    USE SIGNAL ;
    PORT
      LAYER M4 ;
        RECT  0 70.992 0.084 71.016 ;
    END
  END y[252]
  PIN y[253]
    DIRECTION INPUT ;
    USE SIGNAL ;
    PORT
      LAYER M4 ;
        RECT  0 71.136 0.084 71.16 ;
    END
  END y[253]
  PIN y[254]
    DIRECTION INPUT ;
    USE SIGNAL ;
    PORT
      LAYER M4 ;
        RECT  0 37.296 0.084 37.32 ;
    END
  END y[254]
  PIN y[255]
    DIRECTION INPUT ;
    USE SIGNAL ;
    PORT
      LAYER M4 ;
        RECT  0 37.44 0.084 37.464 ;
    END
  END y[255]
  PIN y[256]
    DIRECTION INPUT ;
    USE SIGNAL ;
    PORT
      LAYER M4 ;
        RECT  0 37.584 0.084 37.608 ;
    END
  END y[256]
  PIN y[257]
    DIRECTION INPUT ;
    USE SIGNAL ;
    PORT
      LAYER M4 ;
        RECT  0 37.728 0.084 37.752 ;
    END
  END y[257]
  PIN y[25]
    DIRECTION INPUT ;
    USE SIGNAL ;
    PORT
      LAYER M4 ;
        RECT  0 36 0.084 36.024 ;
    END
  END y[25]
  PIN y[26]
    DIRECTION INPUT ;
    USE SIGNAL ;
    PORT
      LAYER M4 ;
        RECT  0 36.144 0.084 36.168 ;
    END
  END y[26]
  PIN y[27]
    DIRECTION INPUT ;
    USE SIGNAL ;
    PORT
      LAYER M4 ;
        RECT  0 36.288 0.084 36.312 ;
    END
  END y[27]
  PIN y[28]
    DIRECTION INPUT ;
    USE SIGNAL ;
    PORT
      LAYER M4 ;
        RECT  0 36.432 0.084 36.456 ;
    END
  END y[28]
  PIN y[29]
    DIRECTION INPUT ;
    USE SIGNAL ;
    PORT
      LAYER M4 ;
        RECT  0 36.576 0.084 36.6 ;
    END
  END y[29]
  PIN y[2]
    DIRECTION INPUT ;
    USE SIGNAL ;
    PORT
      LAYER M4 ;
        RECT  0 32.688 0.084 32.712 ;
    END
  END y[2]
  PIN y[30]
    DIRECTION INPUT ;
    USE SIGNAL ;
    PORT
      LAYER M4 ;
        RECT  0 27.504 0.084 27.528 ;
    END
  END y[30]
  PIN y[31]
    DIRECTION INPUT ;
    USE SIGNAL ;
    PORT
      LAYER M4 ;
        RECT  0 27.648 0.084 27.672 ;
    END
  END y[31]
  PIN y[32]
    DIRECTION INPUT ;
    USE SIGNAL ;
    PORT
      LAYER M4 ;
        RECT  0 27.792 0.084 27.816 ;
    END
  END y[32]
  PIN y[33]
    DIRECTION INPUT ;
    USE SIGNAL ;
    PORT
      LAYER M4 ;
        RECT  0 27.936 0.084 27.96 ;
    END
  END y[33]
  PIN y[34]
    DIRECTION INPUT ;
    USE SIGNAL ;
    PORT
      LAYER M4 ;
        RECT  0 28.08 0.084 28.104 ;
    END
  END y[34]
  PIN y[35]
    DIRECTION INPUT ;
    USE SIGNAL ;
    PORT
      LAYER M4 ;
        RECT  0 28.224 0.084 28.248 ;
    END
  END y[35]
  PIN y[36]
    DIRECTION INPUT ;
    USE SIGNAL ;
    PORT
      LAYER M4 ;
        RECT  0 28.368 0.084 28.392 ;
    END
  END y[36]
  PIN y[37]
    DIRECTION INPUT ;
    USE SIGNAL ;
    PORT
      LAYER M4 ;
        RECT  0 28.512 0.084 28.536 ;
    END
  END y[37]
  PIN y[38]
    DIRECTION INPUT ;
    USE SIGNAL ;
    PORT
      LAYER M4 ;
        RECT  0 28.656 0.084 28.68 ;
    END
  END y[38]
  PIN y[39]
    DIRECTION INPUT ;
    USE SIGNAL ;
    PORT
      LAYER M4 ;
        RECT  0 28.8 0.084 28.824 ;
    END
  END y[39]
  PIN y[3]
    DIRECTION INPUT ;
    USE SIGNAL ;
    PORT
      LAYER M4 ;
        RECT  0 32.832 0.084 32.856 ;
    END
  END y[3]
  PIN y[40]
    DIRECTION INPUT ;
    USE SIGNAL ;
    PORT
      LAYER M4 ;
        RECT  0 28.944 0.084 28.968 ;
    END
  END y[40]
  PIN y[41]
    DIRECTION INPUT ;
    USE SIGNAL ;
    PORT
      LAYER M4 ;
        RECT  0 29.088 0.084 29.112 ;
    END
  END y[41]
  PIN y[42]
    DIRECTION INPUT ;
    USE SIGNAL ;
    PORT
      LAYER M4 ;
        RECT  0 29.232 0.084 29.256 ;
    END
  END y[42]
  PIN y[43]
    DIRECTION INPUT ;
    USE SIGNAL ;
    PORT
      LAYER M4 ;
        RECT  0 29.376 0.084 29.4 ;
    END
  END y[43]
  PIN y[44]
    DIRECTION INPUT ;
    USE SIGNAL ;
    PORT
      LAYER M4 ;
        RECT  0 29.52 0.084 29.544 ;
    END
  END y[44]
  PIN y[45]
    DIRECTION INPUT ;
    USE SIGNAL ;
    PORT
      LAYER M4 ;
        RECT  0 29.664 0.084 29.688 ;
    END
  END y[45]
  PIN y[46]
    DIRECTION INPUT ;
    USE SIGNAL ;
    PORT
      LAYER M4 ;
        RECT  0 29.808 0.084 29.832 ;
    END
  END y[46]
  PIN y[47]
    DIRECTION INPUT ;
    USE SIGNAL ;
    PORT
      LAYER M4 ;
        RECT  0 29.952 0.084 29.976 ;
    END
  END y[47]
  PIN y[48]
    DIRECTION INPUT ;
    USE SIGNAL ;
    PORT
      LAYER M4 ;
        RECT  0 30.096 0.084 30.12 ;
    END
  END y[48]
  PIN y[49]
    DIRECTION INPUT ;
    USE SIGNAL ;
    PORT
      LAYER M4 ;
        RECT  0 30.24 0.084 30.264 ;
    END
  END y[49]
  PIN y[4]
    DIRECTION INPUT ;
    USE SIGNAL ;
    PORT
      LAYER M4 ;
        RECT  0 32.976 0.084 33 ;
    END
  END y[4]
  PIN y[50]
    DIRECTION INPUT ;
    USE SIGNAL ;
    PORT
      LAYER M4 ;
        RECT  0 30.384 0.084 30.408 ;
    END
  END y[50]
  PIN y[51]
    DIRECTION INPUT ;
    USE SIGNAL ;
    PORT
      LAYER M4 ;
        RECT  0 30.528 0.084 30.552 ;
    END
  END y[51]
  PIN y[52]
    DIRECTION INPUT ;
    USE SIGNAL ;
    PORT
      LAYER M4 ;
        RECT  0 30.672 0.084 30.696 ;
    END
  END y[52]
  PIN y[53]
    DIRECTION INPUT ;
    USE SIGNAL ;
    PORT
      LAYER M4 ;
        RECT  0 30.816 0.084 30.84 ;
    END
  END y[53]
  PIN y[54]
    DIRECTION INPUT ;
    USE SIGNAL ;
    PORT
      LAYER M4 ;
        RECT  0 30.96 0.084 30.984 ;
    END
  END y[54]
  PIN y[55]
    DIRECTION INPUT ;
    USE SIGNAL ;
    PORT
      LAYER M4 ;
        RECT  0 31.104 0.084 31.128 ;
    END
  END y[55]
  PIN y[56]
    DIRECTION INPUT ;
    USE SIGNAL ;
    PORT
      LAYER M4 ;
        RECT  0 31.248 0.084 31.272 ;
    END
  END y[56]
  PIN y[57]
    DIRECTION INPUT ;
    USE SIGNAL ;
    PORT
      LAYER M4 ;
        RECT  0 31.392 0.084 31.416 ;
    END
  END y[57]
  PIN y[58]
    DIRECTION INPUT ;
    USE SIGNAL ;
    PORT
      LAYER M4 ;
        RECT  0 31.536 0.084 31.56 ;
    END
  END y[58]
  PIN y[59]
    DIRECTION INPUT ;
    USE SIGNAL ;
    PORT
      LAYER M4 ;
        RECT  0 31.68 0.084 31.704 ;
    END
  END y[59]
  PIN y[5]
    DIRECTION INPUT ;
    USE SIGNAL ;
    PORT
      LAYER M4 ;
        RECT  0 33.12 0.084 33.144 ;
    END
  END y[5]
  PIN y[60]
    DIRECTION INPUT ;
    USE SIGNAL ;
    PORT
      LAYER M4 ;
        RECT  0 31.824 0.084 31.848 ;
    END
  END y[60]
  PIN y[61]
    DIRECTION INPUT ;
    USE SIGNAL ;
    PORT
      LAYER M4 ;
        RECT  0 31.968 0.084 31.992 ;
    END
  END y[61]
  PIN y[62]
    DIRECTION INPUT ;
    USE SIGNAL ;
    PORT
      LAYER M4 ;
        RECT  0 13.68 0.084 13.704 ;
    END
  END y[62]
  PIN y[63]
    DIRECTION INPUT ;
    USE SIGNAL ;
    PORT
      LAYER M4 ;
        RECT  0 13.824 0.084 13.848 ;
    END
  END y[63]
  PIN y[64]
    DIRECTION INPUT ;
    USE SIGNAL ;
    PORT
      LAYER M4 ;
        RECT  0 13.968 0.084 13.992 ;
    END
  END y[64]
  PIN y[65]
    DIRECTION INPUT ;
    USE SIGNAL ;
    PORT
      LAYER M4 ;
        RECT  0 14.112 0.084 14.136 ;
    END
  END y[65]
  PIN y[66]
    DIRECTION INPUT ;
    USE SIGNAL ;
    PORT
      LAYER M4 ;
        RECT  0 14.256 0.084 14.28 ;
    END
  END y[66]
  PIN y[67]
    DIRECTION INPUT ;
    USE SIGNAL ;
    PORT
      LAYER M4 ;
        RECT  0 14.4 0.084 14.424 ;
    END
  END y[67]
  PIN y[68]
    DIRECTION INPUT ;
    USE SIGNAL ;
    PORT
      LAYER M4 ;
        RECT  0 14.544 0.084 14.568 ;
    END
  END y[68]
  PIN y[69]
    DIRECTION INPUT ;
    USE SIGNAL ;
    PORT
      LAYER M4 ;
        RECT  0 14.688 0.084 14.712 ;
    END
  END y[69]
  PIN y[6]
    DIRECTION INPUT ;
    USE SIGNAL ;
    PORT
      LAYER M4 ;
        RECT  0 33.264 0.084 33.288 ;
    END
  END y[6]
  PIN y[70]
    DIRECTION INPUT ;
    USE SIGNAL ;
    PORT
      LAYER M4 ;
        RECT  0 14.832 0.084 14.856 ;
    END
  END y[70]
  PIN y[71]
    DIRECTION INPUT ;
    USE SIGNAL ;
    PORT
      LAYER M4 ;
        RECT  0 14.976 0.084 15 ;
    END
  END y[71]
  PIN y[72]
    DIRECTION INPUT ;
    USE SIGNAL ;
    PORT
      LAYER M4 ;
        RECT  0 15.12 0.084 15.144 ;
    END
  END y[72]
  PIN y[73]
    DIRECTION INPUT ;
    USE SIGNAL ;
    PORT
      LAYER M4 ;
        RECT  0 15.264 0.084 15.288 ;
    END
  END y[73]
  PIN y[74]
    DIRECTION INPUT ;
    USE SIGNAL ;
    PORT
      LAYER M4 ;
        RECT  0 15.408 0.084 15.432 ;
    END
  END y[74]
  PIN y[75]
    DIRECTION INPUT ;
    USE SIGNAL ;
    PORT
      LAYER M4 ;
        RECT  0 15.552 0.084 15.576 ;
    END
  END y[75]
  PIN y[76]
    DIRECTION INPUT ;
    USE SIGNAL ;
    PORT
      LAYER M4 ;
        RECT  0 15.696 0.084 15.72 ;
    END
  END y[76]
  PIN y[77]
    DIRECTION INPUT ;
    USE SIGNAL ;
    PORT
      LAYER M4 ;
        RECT  0 15.84 0.084 15.864 ;
    END
  END y[77]
  PIN y[78]
    DIRECTION INPUT ;
    USE SIGNAL ;
    PORT
      LAYER M4 ;
        RECT  0 15.984 0.084 16.008 ;
    END
  END y[78]
  PIN y[79]
    DIRECTION INPUT ;
    USE SIGNAL ;
    PORT
      LAYER M4 ;
        RECT  0 16.128 0.084 16.152 ;
    END
  END y[79]
  PIN y[7]
    DIRECTION INPUT ;
    USE SIGNAL ;
    PORT
      LAYER M4 ;
        RECT  0 33.408 0.084 33.432 ;
    END
  END y[7]
  PIN y[80]
    DIRECTION INPUT ;
    USE SIGNAL ;
    PORT
      LAYER M4 ;
        RECT  0 16.272 0.084 16.296 ;
    END
  END y[80]
  PIN y[81]
    DIRECTION INPUT ;
    USE SIGNAL ;
    PORT
      LAYER M4 ;
        RECT  0 16.416 0.084 16.44 ;
    END
  END y[81]
  PIN y[82]
    DIRECTION INPUT ;
    USE SIGNAL ;
    PORT
      LAYER M4 ;
        RECT  0 16.56 0.084 16.584 ;
    END
  END y[82]
  PIN y[83]
    DIRECTION INPUT ;
    USE SIGNAL ;
    PORT
      LAYER M4 ;
        RECT  0 16.704 0.084 16.728 ;
    END
  END y[83]
  PIN y[84]
    DIRECTION INPUT ;
    USE SIGNAL ;
    PORT
      LAYER M4 ;
        RECT  0 16.848 0.084 16.872 ;
    END
  END y[84]
  PIN y[85]
    DIRECTION INPUT ;
    USE SIGNAL ;
    PORT
      LAYER M4 ;
        RECT  0 16.992 0.084 17.016 ;
    END
  END y[85]
  PIN y[86]
    DIRECTION INPUT ;
    USE SIGNAL ;
    PORT
      LAYER M4 ;
        RECT  0 17.136 0.084 17.16 ;
    END
  END y[86]
  PIN y[87]
    DIRECTION INPUT ;
    USE SIGNAL ;
    PORT
      LAYER M4 ;
        RECT  0 17.28 0.084 17.304 ;
    END
  END y[87]
  PIN y[88]
    DIRECTION INPUT ;
    USE SIGNAL ;
    PORT
      LAYER M4 ;
        RECT  0 17.424 0.084 17.448 ;
    END
  END y[88]
  PIN y[89]
    DIRECTION INPUT ;
    USE SIGNAL ;
    PORT
      LAYER M4 ;
        RECT  0 17.568 0.084 17.592 ;
    END
  END y[89]
  PIN y[8]
    DIRECTION INPUT ;
    USE SIGNAL ;
    PORT
      LAYER M4 ;
        RECT  0 33.552 0.084 33.576 ;
    END
  END y[8]
  PIN y[90]
    DIRECTION INPUT ;
    USE SIGNAL ;
    PORT
      LAYER M4 ;
        RECT  0 17.712 0.084 17.736 ;
    END
  END y[90]
  PIN y[91]
    DIRECTION INPUT ;
    USE SIGNAL ;
    PORT
      LAYER M4 ;
        RECT  0 17.856 0.084 17.88 ;
    END
  END y[91]
  PIN y[92]
    DIRECTION INPUT ;
    USE SIGNAL ;
    PORT
      LAYER M4 ;
        RECT  0 18 0.084 18.024 ;
    END
  END y[92]
  PIN y[93]
    DIRECTION INPUT ;
    USE SIGNAL ;
    PORT
      LAYER M4 ;
        RECT  0 18.144 0.084 18.168 ;
    END
  END y[93]
  PIN y[94]
    DIRECTION INPUT ;
    USE SIGNAL ;
    PORT
      LAYER M4 ;
        RECT  0 22.896 0.084 22.92 ;
    END
  END y[94]
  PIN y[95]
    DIRECTION INPUT ;
    USE SIGNAL ;
    PORT
      LAYER M4 ;
        RECT  0 23.04 0.084 23.064 ;
    END
  END y[95]
  PIN y[96]
    DIRECTION INPUT ;
    USE SIGNAL ;
    PORT
      LAYER M4 ;
        RECT  0 23.184 0.084 23.208 ;
    END
  END y[96]
  PIN y[97]
    DIRECTION INPUT ;
    USE SIGNAL ;
    PORT
      LAYER M4 ;
        RECT  0 23.328 0.084 23.352 ;
    END
  END y[97]
  PIN y[98]
    DIRECTION INPUT ;
    USE SIGNAL ;
    PORT
      LAYER M4 ;
        RECT  0 23.472 0.084 23.496 ;
    END
  END y[98]
  PIN y[99]
    DIRECTION INPUT ;
    USE SIGNAL ;
    PORT
      LAYER M4 ;
        RECT  0 23.616 0.084 23.64 ;
    END
  END y[99]
  PIN y[9]
    DIRECTION INPUT ;
    USE SIGNAL ;
    PORT
      LAYER M4 ;
        RECT  0 33.696 0.084 33.72 ;
    END
  END y[9]
  PIN VDD
    DIRECTION INOUT ;
    USE POWER ;
    PORT
      LAYER M5 ;
        RECT  18.792 2.151 18.912 92.889 ;
        RECT  16.092 2.151 16.212 92.889 ;
        RECT  13.392 2.151 13.512 92.889 ;
        RECT  10.692 2.151 10.812 92.889 ;
        RECT  7.992 2.151 8.112 92.889 ;
        RECT  5.292 2.151 5.412 92.889 ;
        RECT  2.592 2.151 2.712 92.889 ;
    END
  END VDD
  PIN VSS
    DIRECTION INOUT ;
    USE GROUND ;
    PORT
      LAYER M5 ;
        RECT  18.6 2.137 18.72 92.903 ;
        RECT  15.9 2.137 16.02 92.903 ;
        RECT  13.2 2.137 13.32 92.903 ;
        RECT  10.5 2.137 10.62 92.903 ;
        RECT  7.8 2.137 7.92 92.903 ;
        RECT  5.1 2.137 5.22 92.903 ;
        RECT  2.4 2.137 2.52 92.903 ;
    END
  END VSS
  # OT_OBS_CLOSED layer=M5 d_um=1.536 added=48
  OBS
    LAYER RVTN ;
     RECT  2.16 2.16 19.44 2.295 ;
     RECT  2.16 2.565 19.44 2.835 ;
     RECT  2.16 3.105 19.44 3.375 ;
     RECT  2.16 3.645 19.44 3.915 ;
     RECT  2.16 4.185 19.44 4.455 ;
     RECT  2.16 4.725 19.44 4.995 ;
     RECT  2.16 5.265 19.44 5.535 ;
     RECT  2.16 5.805 19.44 6.075 ;
     RECT  2.16 6.345 19.44 6.615 ;
     RECT  2.16 6.885 19.44 7.155 ;
     RECT  2.16 7.425 19.44 7.695 ;
     RECT  2.16 7.965 19.44 8.235 ;
     RECT  2.16 8.505 19.44 8.775 ;
     RECT  2.16 9.045 19.44 9.315 ;
     RECT  2.16 9.585 19.44 9.855 ;
     RECT  2.16 10.125 19.44 10.395 ;
     RECT  2.16 10.665 19.44 10.935 ;
     RECT  2.16 11.205 19.44 11.475 ;
     RECT  2.16 11.745 19.44 12.015 ;
     RECT  2.16 12.285 19.44 12.555 ;
     RECT  2.16 12.825 19.44 13.095 ;
     RECT  2.16 13.365 19.44 13.635 ;
     RECT  2.16 13.905 19.44 14.175 ;
     RECT  2.16 14.445 19.44 14.715 ;
     RECT  2.16 14.985 19.44 15.255 ;
     RECT  2.16 15.525 19.44 15.795 ;
     RECT  2.16 16.065 19.44 16.335 ;
     RECT  2.16 16.605 19.44 16.875 ;
     RECT  2.16 17.145 19.44 17.415 ;
     RECT  2.16 17.685 19.44 17.955 ;
     RECT  2.16 18.225 19.44 18.495 ;
     RECT  2.16 18.765 19.44 19.035 ;
     RECT  2.16 19.305 19.44 19.575 ;
     RECT  2.16 19.845 19.44 20.115 ;
     RECT  2.16 20.385 19.44 20.655 ;
     RECT  2.16 20.925 19.44 21.195 ;
     RECT  2.16 21.465 19.44 21.735 ;
     RECT  2.16 22.005 19.44 22.275 ;
     RECT  2.16 22.545 19.44 22.815 ;
     RECT  2.16 23.085 19.44 23.355 ;
     RECT  2.16 23.625 19.44 23.895 ;
     RECT  2.16 24.165 19.44 24.435 ;
     RECT  2.16 24.705 19.44 24.975 ;
     RECT  2.16 25.245 19.44 25.515 ;
     RECT  2.16 25.785 19.44 26.055 ;
     RECT  2.16 26.325 19.44 26.595 ;
     RECT  2.16 26.865 19.44 27.135 ;
     RECT  2.16 27.405 19.44 27.675 ;
     RECT  2.16 27.945 19.44 28.215 ;
     RECT  2.16 28.485 19.44 28.755 ;
     RECT  2.16 29.025 19.44 29.295 ;
     RECT  2.16 29.565 19.44 29.835 ;
     RECT  2.16 30.105 19.44 30.375 ;
     RECT  2.16 30.645 19.44 30.915 ;
     RECT  2.16 31.185 19.44 31.455 ;
     RECT  2.16 31.725 19.44 31.995 ;
     RECT  2.16 32.265 19.44 32.535 ;
     RECT  2.16 32.805 19.44 33.075 ;
     RECT  2.16 33.345 19.44 33.615 ;
     RECT  2.16 33.885 19.44 34.155 ;
     RECT  2.16 34.425 19.44 34.695 ;
     RECT  2.16 34.965 19.44 35.235 ;
     RECT  2.16 35.505 19.44 35.775 ;
     RECT  2.16 36.045 19.44 36.315 ;
     RECT  2.16 36.585 19.44 36.855 ;
     RECT  2.16 37.125 19.44 37.395 ;
     RECT  2.16 37.665 19.44 37.935 ;
     RECT  2.16 38.205 19.44 38.475 ;
     RECT  2.16 38.745 19.44 39.015 ;
     RECT  2.16 39.285 19.44 39.555 ;
     RECT  2.16 39.825 19.44 40.095 ;
     RECT  2.16 40.365 19.44 40.635 ;
     RECT  2.16 40.905 19.44 41.175 ;
     RECT  2.16 41.445 19.44 41.715 ;
     RECT  2.16 41.985 19.44 42.255 ;
     RECT  2.16 42.525 19.44 42.795 ;
     RECT  2.16 43.065 19.44 43.335 ;
     RECT  2.16 43.605 19.44 43.875 ;
     RECT  2.16 44.145 19.44 44.415 ;
     RECT  2.16 44.685 19.44 44.955 ;
     RECT  2.16 45.225 19.44 45.495 ;
     RECT  2.16 45.765 19.44 46.035 ;
     RECT  2.16 46.305 19.44 46.575 ;
     RECT  2.16 46.845 19.44 47.115 ;
     RECT  2.16 47.385 19.44 47.655 ;
     RECT  2.16 47.925 19.44 48.195 ;
     RECT  2.16 48.465 19.44 48.735 ;
     RECT  2.16 49.005 19.44 49.275 ;
     RECT  2.16 49.545 19.44 49.815 ;
     RECT  2.16 50.085 19.44 50.355 ;
     RECT  2.16 50.625 19.44 50.895 ;
     RECT  2.16 51.165 19.44 51.435 ;
     RECT  2.16 51.705 19.44 51.975 ;
     RECT  2.16 52.245 19.44 52.515 ;
     RECT  2.16 52.785 19.44 53.055 ;
     RECT  2.16 53.325 19.44 53.595 ;
     RECT  2.16 53.865 19.44 54.135 ;
     RECT  2.16 54.405 19.44 54.675 ;
     RECT  2.16 54.945 19.44 55.215 ;
     RECT  2.16 55.485 19.44 55.755 ;
     RECT  2.16 56.025 19.44 56.295 ;
     RECT  2.16 56.565 19.44 56.835 ;
     RECT  2.16 57.105 19.44 57.375 ;
     RECT  2.16 57.645 19.44 57.915 ;
     RECT  2.16 58.185 19.44 58.455 ;
     RECT  2.16 58.725 19.44 58.995 ;
     RECT  2.16 59.265 19.44 59.535 ;
     RECT  2.16 59.805 19.44 60.075 ;
     RECT  2.16 60.345 19.44 60.615 ;
     RECT  2.16 60.885 19.44 61.155 ;
     RECT  2.16 61.425 19.44 61.695 ;
     RECT  2.16 61.965 19.44 62.235 ;
     RECT  2.16 62.505 19.44 62.775 ;
     RECT  2.16 63.045 19.44 63.315 ;
     RECT  2.16 63.585 19.44 63.855 ;
     RECT  2.16 64.125 19.44 64.395 ;
     RECT  2.16 64.665 19.44 64.935 ;
     RECT  2.16 65.205 19.44 65.475 ;
     RECT  2.16 65.745 19.44 66.015 ;
     RECT  2.16 66.285 19.44 66.555 ;
     RECT  2.16 66.825 19.44 67.095 ;
     RECT  2.16 67.365 19.44 67.635 ;
     RECT  2.16 67.905 19.44 68.175 ;
     RECT  2.16 68.445 19.44 68.715 ;
     RECT  2.16 68.985 19.44 69.255 ;
     RECT  2.16 69.525 19.44 69.795 ;
     RECT  2.16 70.065 19.44 70.335 ;
     RECT  2.16 70.605 19.44 70.875 ;
     RECT  2.16 71.145 19.44 71.415 ;
     RECT  2.16 71.685 19.44 71.955 ;
     RECT  2.16 72.225 19.44 72.495 ;
     RECT  2.16 72.765 19.44 73.035 ;
     RECT  2.16 73.305 19.44 73.575 ;
     RECT  2.16 73.845 19.44 74.115 ;
     RECT  2.16 74.385 19.44 74.655 ;
     RECT  2.16 74.925 19.44 75.195 ;
     RECT  2.16 75.465 19.44 75.735 ;
     RECT  2.16 76.005 19.44 76.275 ;
     RECT  2.16 76.545 19.44 76.815 ;
     RECT  2.16 77.085 19.44 77.355 ;
     RECT  2.16 77.625 19.44 77.895 ;
     RECT  2.16 78.165 19.44 78.435 ;
     RECT  2.16 78.705 19.44 78.975 ;
     RECT  2.16 79.245 19.44 79.515 ;
     RECT  2.16 79.785 19.44 80.055 ;
     RECT  2.16 80.325 19.44 80.595 ;
     RECT  2.16 80.865 19.44 81.135 ;
     RECT  2.16 81.405 19.44 81.675 ;
     RECT  2.16 81.945 19.44 82.215 ;
     RECT  2.16 82.485 19.44 82.755 ;
     RECT  2.16 83.025 19.44 83.295 ;
     RECT  2.16 83.565 19.44 83.835 ;
     RECT  2.16 84.105 19.44 84.375 ;
     RECT  2.16 84.645 19.44 84.915 ;
     RECT  2.16 85.185 19.44 85.455 ;
     RECT  2.16 85.725 19.44 85.995 ;
     RECT  2.16 86.265 19.44 86.535 ;
     RECT  2.16 86.805 19.44 87.075 ;
     RECT  2.16 87.345 19.44 87.615 ;
     RECT  2.16 87.885 19.44 88.155 ;
     RECT  2.16 88.425 19.44 88.695 ;
     RECT  2.16 88.965 19.44 89.235 ;
     RECT  2.16 89.505 19.44 89.775 ;
     RECT  2.16 90.045 19.44 90.315 ;
     RECT  2.16 90.585 19.44 90.855 ;
     RECT  2.16 91.125 19.44 91.395 ;
     RECT  2.16 91.665 19.44 91.935 ;
     RECT  2.16 92.205 19.44 92.475 ;
     RECT  2.16 92.745 19.44 92.88 ;
    LAYER RVTP ;
     RECT  2.16 2.295 19.44 2.565 ;
     RECT  2.16 2.835 19.44 3.105 ;
     RECT  2.16 3.375 19.44 3.645 ;
     RECT  2.16 3.915 19.44 4.185 ;
     RECT  2.16 4.455 19.44 4.725 ;
     RECT  2.16 4.995 19.44 5.265 ;
     RECT  2.16 5.535 19.44 5.805 ;
     RECT  2.16 6.075 19.44 6.345 ;
     RECT  2.16 6.615 19.44 6.885 ;
     RECT  2.16 7.155 19.44 7.425 ;
     RECT  2.16 7.695 19.44 7.965 ;
     RECT  2.16 8.235 19.44 8.505 ;
     RECT  2.16 8.775 19.44 9.045 ;
     RECT  2.16 9.315 19.44 9.585 ;
     RECT  2.16 9.855 19.44 10.125 ;
     RECT  2.16 10.395 19.44 10.665 ;
     RECT  2.16 10.935 19.44 11.205 ;
     RECT  2.16 11.475 19.44 11.745 ;
     RECT  2.16 12.015 19.44 12.285 ;
     RECT  2.16 12.555 19.44 12.825 ;
     RECT  2.16 13.095 19.44 13.365 ;
     RECT  2.16 13.635 19.44 13.905 ;
     RECT  2.16 14.175 19.44 14.445 ;
     RECT  2.16 14.715 19.44 14.985 ;
     RECT  2.16 15.255 19.44 15.525 ;
     RECT  2.16 15.795 19.44 16.065 ;
     RECT  2.16 16.335 19.44 16.605 ;
     RECT  2.16 16.875 19.44 17.145 ;
     RECT  2.16 17.415 19.44 17.685 ;
     RECT  2.16 17.955 19.44 18.225 ;
     RECT  2.16 18.495 19.44 18.765 ;
     RECT  2.16 19.035 19.44 19.305 ;
     RECT  2.16 19.575 19.44 19.845 ;
     RECT  2.16 20.115 19.44 20.385 ;
     RECT  2.16 20.655 19.44 20.925 ;
     RECT  2.16 21.195 19.44 21.465 ;
     RECT  2.16 21.735 19.44 22.005 ;
     RECT  2.16 22.275 19.44 22.545 ;
     RECT  2.16 22.815 19.44 23.085 ;
     RECT  2.16 23.355 19.44 23.625 ;
     RECT  2.16 23.895 19.44 24.165 ;
     RECT  2.16 24.435 19.44 24.705 ;
     RECT  2.16 24.975 19.44 25.245 ;
     RECT  2.16 25.515 19.44 25.785 ;
     RECT  2.16 26.055 19.44 26.325 ;
     RECT  2.16 26.595 19.44 26.865 ;
     RECT  2.16 27.135 19.44 27.405 ;
     RECT  2.16 27.675 19.44 27.945 ;
     RECT  2.16 28.215 19.44 28.485 ;
     RECT  2.16 28.755 19.44 29.025 ;
     RECT  2.16 29.295 19.44 29.565 ;
     RECT  2.16 29.835 19.44 30.105 ;
     RECT  2.16 30.375 19.44 30.645 ;
     RECT  2.16 30.915 19.44 31.185 ;
     RECT  2.16 31.455 19.44 31.725 ;
     RECT  2.16 31.995 19.44 32.265 ;
     RECT  2.16 32.535 19.44 32.805 ;
     RECT  2.16 33.075 19.44 33.345 ;
     RECT  2.16 33.615 19.44 33.885 ;
     RECT  2.16 34.155 19.44 34.425 ;
     RECT  2.16 34.695 19.44 34.965 ;
     RECT  2.16 35.235 19.44 35.505 ;
     RECT  2.16 35.775 19.44 36.045 ;
     RECT  2.16 36.315 19.44 36.585 ;
     RECT  2.16 36.855 19.44 37.125 ;
     RECT  2.16 37.395 19.44 37.665 ;
     RECT  2.16 37.935 19.44 38.205 ;
     RECT  2.16 38.475 19.44 38.745 ;
     RECT  2.16 39.015 19.44 39.285 ;
     RECT  2.16 39.555 19.44 39.825 ;
     RECT  2.16 40.095 19.44 40.365 ;
     RECT  2.16 40.635 19.44 40.905 ;
     RECT  2.16 41.175 19.44 41.445 ;
     RECT  2.16 41.715 19.44 41.985 ;
     RECT  2.16 42.255 19.44 42.525 ;
     RECT  2.16 42.795 19.44 43.065 ;
     RECT  2.16 43.335 19.44 43.605 ;
     RECT  2.16 43.875 19.44 44.145 ;
     RECT  2.16 44.415 19.44 44.685 ;
     RECT  2.16 44.955 19.44 45.225 ;
     RECT  2.16 45.495 19.44 45.765 ;
     RECT  2.16 46.035 19.44 46.305 ;
     RECT  2.16 46.575 19.44 46.845 ;
     RECT  2.16 47.115 19.44 47.385 ;
     RECT  2.16 47.655 19.44 47.925 ;
     RECT  2.16 48.195 19.44 48.465 ;
     RECT  2.16 48.735 19.44 49.005 ;
     RECT  2.16 49.275 19.44 49.545 ;
     RECT  2.16 49.815 19.44 50.085 ;
     RECT  2.16 50.355 19.44 50.625 ;
     RECT  2.16 50.895 19.44 51.165 ;
     RECT  2.16 51.435 19.44 51.705 ;
     RECT  2.16 51.975 19.44 52.245 ;
     RECT  2.16 52.515 19.44 52.785 ;
     RECT  2.16 53.055 19.44 53.325 ;
     RECT  2.16 53.595 19.44 53.865 ;
     RECT  2.16 54.135 19.44 54.405 ;
     RECT  2.16 54.675 19.44 54.945 ;
     RECT  2.16 55.215 19.44 55.485 ;
     RECT  2.16 55.755 19.44 56.025 ;
     RECT  2.16 56.295 19.44 56.565 ;
     RECT  2.16 56.835 19.44 57.105 ;
     RECT  2.16 57.375 19.44 57.645 ;
     RECT  2.16 57.915 19.44 58.185 ;
     RECT  2.16 58.455 19.44 58.725 ;
     RECT  2.16 58.995 19.44 59.265 ;
     RECT  2.16 59.535 19.44 59.805 ;
     RECT  2.16 60.075 19.44 60.345 ;
     RECT  2.16 60.615 19.44 60.885 ;
     RECT  2.16 61.155 19.44 61.425 ;
     RECT  2.16 61.695 19.44 61.965 ;
     RECT  2.16 62.235 19.44 62.505 ;
     RECT  2.16 62.775 19.44 63.045 ;
     RECT  2.16 63.315 19.44 63.585 ;
     RECT  2.16 63.855 19.44 64.125 ;
     RECT  2.16 64.395 19.44 64.665 ;
     RECT  2.16 64.935 19.44 65.205 ;
     RECT  2.16 65.475 19.44 65.745 ;
     RECT  2.16 66.015 19.44 66.285 ;
     RECT  2.16 66.555 19.44 66.825 ;
     RECT  2.16 67.095 19.44 67.365 ;
     RECT  2.16 67.635 19.44 67.905 ;
     RECT  2.16 68.175 19.44 68.445 ;
     RECT  2.16 68.715 19.44 68.985 ;
     RECT  2.16 69.255 19.44 69.525 ;
     RECT  2.16 69.795 19.44 70.065 ;
     RECT  2.16 70.335 19.44 70.605 ;
     RECT  2.16 70.875 19.44 71.145 ;
     RECT  2.16 71.415 19.44 71.685 ;
     RECT  2.16 71.955 19.44 72.225 ;
     RECT  2.16 72.495 19.44 72.765 ;
     RECT  2.16 73.035 19.44 73.305 ;
     RECT  2.16 73.575 19.44 73.845 ;
     RECT  2.16 74.115 19.44 74.385 ;
     RECT  2.16 74.655 19.44 74.925 ;
     RECT  2.16 75.195 19.44 75.465 ;
     RECT  2.16 75.735 19.44 76.005 ;
     RECT  2.16 76.275 19.44 76.545 ;
     RECT  2.16 76.815 19.44 77.085 ;
     RECT  2.16 77.355 19.44 77.625 ;
     RECT  2.16 77.895 19.44 78.165 ;
     RECT  2.16 78.435 19.44 78.705 ;
     RECT  2.16 78.975 19.44 79.245 ;
     RECT  2.16 79.515 19.44 79.785 ;
     RECT  2.16 80.055 19.44 80.325 ;
     RECT  2.16 80.595 19.44 80.865 ;
     RECT  2.16 81.135 19.44 81.405 ;
     RECT  2.16 81.675 19.44 81.945 ;
     RECT  2.16 82.215 19.44 82.485 ;
     RECT  2.16 82.755 19.44 83.025 ;
     RECT  2.16 83.295 19.44 83.565 ;
     RECT  2.16 83.835 19.44 84.105 ;
     RECT  2.16 84.375 19.44 84.645 ;
     RECT  2.16 84.915 19.44 85.185 ;
     RECT  2.16 85.455 19.44 85.725 ;
     RECT  2.16 85.995 19.44 86.265 ;
     RECT  2.16 86.535 19.44 86.805 ;
     RECT  2.16 87.075 19.44 87.345 ;
     RECT  2.16 87.615 19.44 87.885 ;
     RECT  2.16 88.155 19.44 88.425 ;
     RECT  2.16 88.695 19.44 88.965 ;
     RECT  2.16 89.235 19.44 89.505 ;
     RECT  2.16 89.775 19.44 90.045 ;
     RECT  2.16 90.315 19.44 90.585 ;
     RECT  2.16 90.855 19.44 91.125 ;
     RECT  2.16 91.395 19.44 91.665 ;
     RECT  2.16 91.935 19.44 92.205 ;
     RECT  2.16 92.475 19.44 92.745 ;
    LAYER M1 ;
     RECT  2.16 2.151 19.44 92.889 ;
    LAYER M2 ;
     RECT  0.031 60.552 0.067 60.57 ;
     RECT  0.031 66.636 0.067 66.654 ;
     RECT  0.067 12.996 0.103 13.014 ;
     RECT  0.031 18.774 0.103 18.792 ;
     RECT  0.067 19.656 0.103 19.674 ;
     RECT  0.031 20.862 0.103 20.88 ;
     RECT  0.031 58.734 0.103 58.752 ;
     RECT  0.067 60.471 0.103 60.57 ;
     RECT  0.031 63.756 0.131 63.774 ;
     RECT  0.031 84.618 0.131 84.636 ;
     RECT  0.103 12.636 0.139 13.014 ;
     RECT  0.103 60.39 0.139 61.218 ;
     RECT  0.103 62.982 0.139 63 ;
     RECT  0.067 66.528 0.139 66.654 ;
     RECT  0.139 12.564 0.167 13.014 ;
     RECT  0.067 79.911 0.167 79.929 ;
     RECT  0.139 28.458 0.175 28.476 ;
     RECT  0.103 29.772 0.175 29.79 ;
     RECT  0.067 57.348 0.203 57.366 ;
     RECT  0.139 62.55 0.211 63 ;
     RECT  0.139 66.528 0.211 66.888 ;
     RECT  0.139 75.816 0.211 75.834 ;
     RECT  0.139 76.86 0.211 76.878 ;
     RECT  0.139 78.408 0.211 79.038 ;
     RECT  0.211 74.592 0.239 76.878 ;
     RECT  0.139 82.611 0.239 82.629 ;
     RECT  0.211 69.462 0.247 70.596 ;
     RECT  0.167 12.564 0.275 12.816 ;
     RECT  0.139 60.39 0.283 61.488 ;
     RECT  0.211 65.952 0.283 66.888 ;
     RECT  0.239 76.131 0.311 76.878 ;
     RECT  0.031 55.926 0.319 55.944 ;
     RECT  0.211 62.514 0.319 63 ;
     RECT  0.319 55.926 0.355 56.394 ;
     RECT  0.283 65.952 0.355 67.05 ;
     RECT  0.211 73.08 0.355 73.098 ;
     RECT  0.103 58.734 0.419 58.95 ;
     RECT  0.247 69.066 0.427 70.596 ;
     RECT  0.211 72.234 0.427 72.252 ;
     RECT  0.355 73.044 0.427 73.134 ;
     RECT  0.427 72.234 0.491 73.134 ;
     RECT  0.427 37.566 0.499 37.584 ;
     RECT  0.211 38.682 0.499 38.7 ;
     RECT  0.491 72.234 0.527 73.098 ;
     RECT  0.175 28.458 0.535 29.79 ;
     RECT  0.499 30.69 0.535 30.708 ;
     RECT  0.499 37.566 0.535 38.7 ;
     RECT  0.499 44.352 0.535 44.37 ;
     RECT  0.283 60.354 0.535 61.488 ;
     RECT  0.319 62.514 0.535 63.342 ;
     RECT  0.355 65.952 0.535 67.428 ;
     RECT  0.427 68.724 0.535 70.596 ;
     RECT  0.239 74.592 0.535 75.15 ;
     RECT  0.211 78.408 0.535 79.776 ;
     RECT  0.103 20.781 0.823 20.88 ;
     RECT  0.103 35.172 0.823 35.19 ;
     RECT  0.247 36.252 0.823 36.27 ;
     RECT  0.103 54.45 0.823 54.468 ;
     RECT  0.823 20.781 0.859 21.024 ;
     RECT  0.823 35.172 0.859 36.27 ;
     RECT  0.535 41.22 0.859 41.238 ;
     RECT  0.823 54.45 0.859 54.774 ;
     RECT  0.859 20.781 0.931 21.528 ;
     RECT  0.859 34.506 0.931 36.27 ;
     RECT  0.535 60.354 0.931 63.342 ;
     RECT  0.275 12.564 0.959 12.654 ;
     RECT  0.535 28.458 0.959 30.978 ;
     RECT  0.859 54.306 0.967 54.774 ;
     RECT  0.355 55.926 0.967 56.934 ;
     RECT  0.103 18.162 1.147 19.674 ;
     RECT  0.419 58.932 1.147 58.95 ;
     RECT  0.931 59.814 1.147 63.342 ;
     RECT  0.103 15.966 1.175 15.984 ;
     RECT  0.967 54.306 1.183 56.934 ;
     RECT  1.183 54.306 1.219 57.438 ;
     RECT  1.147 58.392 1.219 63.342 ;
     RECT  0.103 22.788 1.291 22.806 ;
     RECT  1.219 54.306 1.327 63.342 ;
     RECT  1.147 18.162 1.399 19.908 ;
     RECT  0.931 20.664 1.399 21.528 ;
     RECT  0.895 53.37 1.399 53.388 ;
     RECT  0.931 34.506 1.435 36.612 ;
     RECT  0.139 32.544 1.471 32.562 ;
     RECT  0.859 40.572 1.471 41.238 ;
     RECT  0.355 17.118 1.507 17.136 ;
     RECT  1.399 18.162 1.507 21.528 ;
     RECT  1.471 32.544 1.507 33.3 ;
     RECT  1.435 34.47 1.507 36.612 ;
     RECT  1.327 54.306 1.507 63.414 ;
     RECT  1.507 17.118 1.579 21.528 ;
     RECT  0.959 28.458 1.579 28.476 ;
     RECT  1.507 32.544 1.579 36.612 ;
     RECT  0.535 65.952 1.579 70.596 ;
     RECT  1.579 16.812 1.651 21.528 ;
     RECT  1.291 22.788 1.723 23.112 ;
     RECT  0.535 42.57 1.723 43.29 ;
     RECT  0.535 44.19 1.723 44.37 ;
     RECT  0.535 47.862 1.723 47.88 ;
     RECT  0.319 71.352 1.723 71.37 ;
     RECT  0.527 72.234 1.723 72.252 ;
     RECT  0.527 73.08 1.723 73.098 ;
     RECT  0.311 76.86 1.723 76.878 ;
     RECT  1.723 71.352 1.759 72.252 ;
     RECT  1.723 73.08 1.759 73.368 ;
     RECT  0.535 51.48 1.903 51.498 ;
     RECT  1.471 40.302 1.939 41.238 ;
     RECT  1.759 71.352 1.939 73.53 ;
     RECT  0.535 74.43 1.939 75.15 ;
     RECT  1.723 22.788 1.975 23.58 ;
     RECT  1.939 39.834 1.975 41.238 ;
     RECT  1.903 50.904 1.975 51.498 ;
     RECT  0.823 52.254 1.975 52.272 ;
     RECT  1.651 16.542 2.011 21.528 ;
     RECT  1.975 22.626 2.011 23.58 ;
     RECT  2.011 24.786 2.047 24.804 ;
     RECT  1.975 39.834 2.047 41.4 ;
     RECT  0.959 12.564 2.083 12.582 ;
     RECT  0.959 29.772 2.119 30.978 ;
     RECT  2.047 39.834 2.119 41.508 ;
     RECT  1.723 42.57 2.119 44.37 ;
     RECT  2.047 24.516 2.155 24.804 ;
     RECT  2.119 39.834 2.155 44.37 ;
     RECT  1.975 50.904 2.155 52.272 ;
     RECT  1.399 53.1 2.155 53.388 ;
     RECT  2.083 12.564 2.16 12.78 ;
     RECT  2.011 16.542 2.16 23.58 ;
     RECT  2.155 24.444 2.16 24.804 ;
     RECT  0.139 25.641 2.16 25.659 ;
     RECT  1.579 27.882 2.16 28.476 ;
     RECT  2.119 29.502 2.16 30.978 ;
     RECT  1.579 32.04 2.16 36.612 ;
     RECT  0.535 37.44 2.16 39.006 ;
     RECT  2.155 39.834 2.16 44.514 ;
     RECT  1.723 47.394 2.16 47.88 ;
     RECT  1.723 49.752 2.16 49.77 ;
     RECT  2.155 50.904 2.16 53.388 ;
     RECT  1.507 54.306 2.16 64.152 ;
     RECT  1.579 65.682 2.16 70.596 ;
     RECT  1.939 71.352 2.16 75.15 ;
     RECT  1.723 76.482 2.16 76.878 ;
     RECT  0.535 77.67 2.16 79.776 ;
     RECT  2.16 2.151 19.44 92.889 ;
     RECT  19.44 27.846 19.679 30.744 ;
     RECT  19.44 31.77 19.895 65.934 ;
     RECT  19.895 31.77 19.931 59.328 ;
     RECT  19.895 60.156 19.931 65.934 ;
     RECT  19.931 36.594 19.967 56.664 ;
     RECT  19.679 28.296 20.003 30.744 ;
     RECT  19.967 36.594 20.003 44.514 ;
     RECT  20.003 36.594 20.039 41.274 ;
     RECT  19.44 67.608 20.255 69.714 ;
     RECT  19.967 45.396 20.471 56.664 ;
     RECT  19.931 60.624 20.471 64.692 ;
     RECT  20.255 67.608 20.471 69.174 ;
     RECT  20.039 36.594 20.507 37.998 ;
     RECT  20.039 38.754 20.507 41.274 ;
     RECT  20.471 45.396 20.507 52.344 ;
     RECT  20.471 53.406 20.507 56.664 ;
     RECT  20.471 67.608 20.507 68.094 ;
     RECT  19.931 31.77 20.543 35.568 ;
     RECT  20.507 36.594 20.543 37.764 ;
     RECT  20.003 42.156 20.543 44.514 ;
     RECT  20.507 50.166 20.543 50.454 ;
     RECT  20.507 53.406 20.543 53.694 ;
     RECT  19.931 57.726 20.543 59.328 ;
     RECT  20.471 61.776 20.543 64.692 ;
     RECT  20.543 32.076 20.579 32.094 ;
     RECT  20.543 36.594 20.579 37.188 ;
     RECT  20.543 58.698 20.579 59.328 ;
     RECT  20.507 46.62 20.615 48.294 ;
     RECT  20.003 30.006 20.687 30.744 ;
     RECT  20.003 28.296 21.443 29.052 ;
     RECT  20.579 36.594 21.443 36.774 ;
     RECT  20.543 57.726 21.443 57.744 ;
     RECT  20.543 62.046 21.443 62.334 ;
     RECT  21.443 28.296 21.479 28.854 ;
     RECT  21.443 36.63 21.479 36.774 ;
     RECT  20.543 42.606 21.479 43.704 ;
     RECT  20.543 44.46 21.479 44.514 ;
     RECT  20.507 49.086 21.479 49.374 ;
     RECT  20.507 51.246 21.479 52.344 ;
     RECT  20.471 60.624 21.479 60.984 ;
     RECT  21.443 62.316 21.479 62.334 ;
     RECT  20.543 63.09 21.479 64.692 ;
     RECT  19.931 65.916 21.487 65.934 ;
     RECT  21.479 28.836 21.515 28.854 ;
     RECT  20.687 30.078 21.515 30.744 ;
     RECT  20.543 33.426 21.515 34.182 ;
     RECT  20.543 35.046 21.515 35.568 ;
     RECT  21.479 36.756 21.515 36.774 ;
     RECT  20.507 38.754 21.515 39.312 ;
     RECT  20.507 40.446 21.515 41.274 ;
     RECT  21.479 42.606 21.515 43.254 ;
     RECT  21.479 44.46 21.515 44.478 ;
     RECT  20.615 46.62 21.515 48.186 ;
     RECT  21.479 49.086 21.515 49.104 ;
     RECT  20.543 50.166 21.515 50.184 ;
     RECT  21.479 51.246 21.515 52.002 ;
     RECT  20.507 54.45 21.515 54.468 ;
     RECT  20.507 55.566 21.515 56.664 ;
     RECT  20.579 59.31 21.515 59.328 ;
     RECT  21.479 60.966 21.515 60.984 ;
     RECT  21.479 63.09 21.515 63.108 ;
     RECT  21.487 65.916 21.515 66.582 ;
     RECT  20.507 68.076 21.515 68.094 ;
     RECT  21.515 66.564 21.587 66.582 ;
     RECT  20.471 69.156 21.587 69.174 ;
    LAYER M3 ;
     RECT  2.415 2.143 2.505 2.413 ;
     RECT  5.115 2.143 5.205 2.413 ;
     RECT  7.815 2.143 7.905 2.413 ;
     RECT  10.515 2.143 10.605 2.413 ;
     RECT  13.215 2.143 13.305 2.413 ;
     RECT  14.112 0.523 14.13 2.413 ;
     RECT  15.915 2.143 16.005 2.413 ;
     RECT  18.615 2.143 18.705 2.413 ;
     RECT  13.215 2.413 14.13 3.029 ;
     RECT  10.515 2.413 10.797 3.181 ;
     RECT  2.415 2.413 2.697 9.211 ;
     RECT  2.304 9.211 2.697 9.355 ;
     RECT  2.052 9.355 2.697 9.499 ;
     RECT  1.512 9.499 2.697 9.931 ;
     RECT  0.9 9.931 2.697 10.123 ;
     RECT  5.115 2.413 5.397 10.939 ;
     RECT  0.144 9.067 0.162 11.083 ;
     RECT  5.04 10.939 5.397 11.515 ;
     RECT  0.108 11.083 0.162 11.659 ;
     RECT  0.9 10.123 2.79 11.659 ;
     RECT  0.108 11.659 2.79 12.811 ;
     RECT  0.108 12.811 3.294 12.901 ;
     RECT  0.108 12.901 3.402 12.991 ;
     RECT  10.224 3.181 10.797 13.441 ;
     RECT  0.072 12.991 3.402 13.627 ;
     RECT  0.072 13.627 3.438 13.667 ;
     RECT  0.072 13.667 3.402 14.611 ;
     RECT  4.824 11.515 5.397 14.791 ;
     RECT  9.54 13.441 10.797 15.449 ;
     RECT  9.54 15.449 9.558 15.565 ;
     RECT  0.072 14.611 3.978 15.835 ;
     RECT  4.824 14.791 5.49 15.835 ;
     RECT  0.072 15.835 5.49 16.555 ;
     RECT  0.072 16.555 5.85 16.681 ;
     RECT  0.072 16.681 6.462 16.835 ;
     RECT  8.856 15.565 9.558 16.879 ;
     RECT  10.515 15.449 10.797 16.879 ;
     RECT  0.072 16.835 5.85 16.943 ;
     RECT  8.856 16.879 10.797 17.491 ;
     RECT  12.276 17.419 12.294 17.887 ;
     RECT  13.215 3.029 13.497 17.887 ;
     RECT  6.804 17.887 6.822 17.987 ;
     RECT  0.072 16.943 5.778 18.769 ;
     RECT  6.804 19.003 6.822 19.103 ;
     RECT  12.276 17.887 13.497 19.579 ;
     RECT  14.4 19.201 14.418 19.579 ;
     RECT  12.276 19.579 14.418 19.615 ;
     RECT  0.036 18.769 5.778 19.757 ;
     RECT  0.828 19.757 5.778 19.885 ;
     RECT  6.768 19.813 6.786 19.885 ;
     RECT  0.828 19.885 6.786 20.083 ;
     RECT  7.815 2.413 8.097 20.083 ;
     RECT  12.276 19.615 14.85 20.155 ;
     RECT  0.828 20.083 8.097 20.219 ;
     RECT  6.912 20.219 8.097 20.353 ;
     RECT  8.856 17.491 11.106 20.353 ;
     RECT  6.912 20.353 11.106 20.417 ;
     RECT  0.036 19.757 0.054 20.776 ;
     RECT  0.828 20.219 6.102 20.776 ;
     RECT  0.036 20.776 6.102 20.885 ;
     RECT  15.915 2.413 16.197 21.271 ;
     RECT  0.108 20.885 6.102 21.485 ;
     RECT  0.864 21.485 6.102 21.533 ;
     RECT  1.296 21.533 6.102 21.541 ;
     RECT  7.092 20.417 11.106 21.541 ;
     RECT  12.276 20.155 14.886 21.703 ;
     RECT  15.696 21.271 16.197 21.703 ;
     RECT  0.324 22.603 0.342 22.781 ;
     RECT  12.276 21.703 16.197 22.981 ;
     RECT  1.296 21.541 11.106 23.117 ;
     RECT  0.108 22.783 0.126 23.501 ;
     RECT  0.828 24.331 0.846 24.475 ;
     RECT  1.584 23.117 11.106 24.475 ;
     RECT  0.828 24.475 11.106 24.763 ;
     RECT  18.615 2.413 18.897 27.985 ;
     RECT  19.656 27.841 19.674 27.985 ;
     RECT  18.615 27.985 19.674 28.453 ;
     RECT  18.615 28.453 19.89 28.795 ;
     RECT  21.456 28.291 21.474 28.831 ;
     RECT  0.108 24.763 11.106 28.921 ;
     RECT  12.24 22.981 16.197 28.921 ;
     RECT  18.576 28.795 19.962 28.921 ;
     RECT  18.576 28.921 20.646 28.957 ;
     RECT  21.456 28.831 21.51 29.029 ;
     RECT  18.396 28.957 20.646 29.227 ;
     RECT  0.108 28.921 16.197 29.371 ;
     RECT  17.712 29.227 20.646 29.371 ;
     RECT  0.108 29.371 16.542 29.795 ;
     RECT  17.46 29.371 20.646 30.001 ;
     RECT  0.144 29.795 16.542 30.181 ;
     RECT  17.46 30.001 20.682 30.181 ;
     RECT  21.42 29.029 21.51 30.557 ;
     RECT  21.492 30.557 21.51 30.749 ;
     RECT  0.144 30.181 20.682 31.721 ;
     RECT  6.264 31.721 20.682 31.853 ;
     RECT  0.144 31.721 5.397 32.107 ;
     RECT  6.264 31.853 20.574 32.285 ;
     RECT  0.108 32.107 5.397 32.881 ;
     RECT  6.264 32.285 20.538 32.881 ;
     RECT  0.108 32.881 20.538 33.149 ;
     RECT  19.908 33.149 20.538 33.293 ;
     RECT  0.108 33.149 19.134 33.889 ;
     RECT  0.108 33.889 19.17 34.267 ;
     RECT  19.908 33.293 19.962 34.267 ;
     RECT  0.108 34.267 19.962 34.555 ;
     RECT  0.108 34.555 20.502 34.655 ;
     RECT  6.516 34.655 20.502 34.699 ;
     RECT  6.516 34.699 20.538 35.021 ;
     RECT  0.108 34.655 5.706 35.195 ;
     RECT  6.516 35.021 19.926 35.231 ;
     RECT  0.144 35.195 5.706 35.261 ;
     RECT  0.216 35.261 5.706 35.465 ;
     RECT  6.516 35.231 17.406 35.465 ;
     RECT  6.516 35.465 6.858 35.537 ;
     RECT  18.18 35.231 19.926 35.609 ;
     RECT  19.908 35.609 19.926 35.851 ;
     RECT  7.815 35.465 17.406 36.005 ;
     RECT  8.82 36.005 17.406 36.121 ;
     RECT  8.82 36.121 17.442 36.211 ;
     RECT  18.18 35.609 19.17 36.211 ;
     RECT  8.82 36.211 19.17 36.239 ;
     RECT  19.908 35.851 20.502 36.419 ;
     RECT  21.492 33.403 21.51 36.427 ;
     RECT  6.516 35.537 6.786 36.545 ;
     RECT  21.456 36.427 21.51 36.571 ;
     RECT  21.42 36.571 21.51 36.749 ;
     RECT  21.492 36.749 21.51 36.779 ;
     RECT  8.82 36.239 19.134 37.049 ;
     RECT  13.14 37.049 19.134 37.129 ;
     RECT  20.448 36.419 20.502 37.165 ;
     RECT  6.516 36.545 6.534 37.291 ;
     RECT  13.14 37.129 19.422 37.579 ;
     RECT  20.448 37.165 20.574 37.579 ;
     RECT  8.82 37.049 12.042 37.769 ;
     RECT  13.14 37.579 20.574 37.901 ;
     RECT  11.52 37.769 12.042 37.967 ;
     RECT  13.14 37.901 20.538 37.975 ;
     RECT  12.348 37.975 20.538 38.621 ;
     RECT  0.216 35.465 5.526 38.705 ;
     RECT  12.348 38.621 19.134 38.705 ;
     RECT  0.54 38.705 5.526 38.749 ;
     RECT  19.908 38.621 20.538 38.909 ;
     RECT  12.492 38.705 19.134 38.939 ;
     RECT  0.54 38.749 5.67 39.289 ;
     RECT  6.516 37.291 6.894 39.289 ;
     RECT  12.492 38.939 19.098 39.451 ;
     RECT  7.815 36.005 8.097 39.523 ;
     RECT  8.82 37.769 10.797 39.523 ;
     RECT  19.908 38.909 20.034 39.659 ;
     RECT  0.54 39.289 6.894 39.829 ;
     RECT  7.815 39.523 10.797 39.829 ;
     RECT  0.54 39.829 10.797 40.055 ;
     RECT  6.84 40.055 8.097 40.127 ;
     RECT  12.348 39.451 19.098 40.171 ;
     RECT  21.492 38.299 21.51 40.171 ;
     RECT  8.82 40.055 10.797 40.261 ;
     RECT  11.52 37.967 11.538 40.261 ;
     RECT  12.276 40.171 19.098 40.333 ;
     RECT  21.42 40.171 21.51 40.397 ;
     RECT  8.82 40.261 11.538 40.405 ;
     RECT  12.276 40.333 19.422 40.405 ;
     RECT  8.82 40.405 19.422 40.433 ;
     RECT  0.54 40.055 5.706 40.459 ;
     RECT  0.144 40.459 5.706 40.589 ;
     RECT  20.484 39.883 20.502 40.675 ;
     RECT  20.484 40.675 20.538 40.747 ;
     RECT  13.068 40.433 19.422 40.925 ;
     RECT  8.82 40.433 12.15 40.937 ;
     RECT  8.82 40.937 12.006 41.009 ;
     RECT  13.068 40.925 19.134 41.099 ;
     RECT  20.196 40.747 20.538 41.179 ;
     RECT  0.54 40.589 5.706 41.251 ;
     RECT  6.912 40.127 8.097 41.251 ;
     RECT  21.492 40.397 21.51 41.279 ;
     RECT  13.068 41.099 19.098 41.341 ;
     RECT  19.944 41.179 20.538 41.357 ;
     RECT  0.54 41.251 8.097 41.645 ;
     RECT  19.944 41.357 20.502 41.645 ;
     RECT  9.576 41.009 12.006 41.659 ;
     RECT  0.828 41.645 8.097 41.675 ;
     RECT  6.804 41.675 8.097 41.755 ;
     RECT  9.576 41.659 12.114 41.755 ;
     RECT  6.804 41.755 8.154 41.791 ;
     RECT  12.924 41.341 19.098 41.899 ;
     RECT  9.288 41.755 12.114 41.909 ;
     RECT  12.924 41.899 19.386 41.917 ;
     RECT  6.804 41.791 8.226 41.945 ;
     RECT  9.972 41.909 11.718 41.981 ;
     RECT  12.564 41.917 19.386 41.981 ;
     RECT  20.448 41.645 20.502 42.151 ;
     RECT  10.515 41.981 11.718 42.173 ;
     RECT  10.515 42.173 11.61 42.179 ;
     RECT  10.515 42.179 11.358 42.215 ;
     RECT  6.804 41.945 6.93 42.323 ;
     RECT  10.515 42.215 10.926 42.323 ;
     RECT  20.448 42.151 20.538 42.365 ;
     RECT  21.492 42.187 21.51 42.475 ;
     RECT  6.84 42.323 6.93 42.485 ;
     RECT  0.828 41.675 5.706 42.565 ;
     RECT  7.815 41.945 8.226 42.565 ;
     RECT  6.84 42.485 6.858 42.593 ;
     RECT  12.564 41.981 19.134 42.799 ;
     RECT  20.448 42.365 20.502 42.907 ;
     RECT  12.564 42.799 19.422 43.033 ;
     RECT  12.132 43.033 19.422 43.141 ;
     RECT  12.06 43.141 19.422 43.229 ;
     RECT  12.06 43.229 19.134 43.231 ;
     RECT  7.815 42.565 8.73 43.295 ;
     RECT  11.916 43.231 19.134 43.303 ;
     RECT  10.515 42.323 10.797 43.411 ;
     RECT  20.412 42.907 20.502 43.411 ;
     RECT  10.515 43.411 10.854 43.537 ;
     RECT  11.808 43.303 19.134 43.537 ;
     RECT  10.515 43.537 19.134 43.565 ;
     RECT  10.515 43.565 11.574 43.673 ;
     RECT  20.412 43.411 20.538 43.771 ;
     RECT  12.348 43.565 19.134 43.805 ;
     RECT  6.912 43.951 6.93 44.177 ;
     RECT  14.508 43.805 19.134 44.185 ;
     RECT  19.908 43.771 20.538 44.185 ;
     RECT  14.508 44.185 20.538 44.237 ;
     RECT  0.54 42.565 5.706 44.311 ;
     RECT  0.54 44.311 5.778 44.347 ;
     RECT  12.348 43.805 13.77 44.375 ;
     RECT  10.515 43.673 10.797 44.383 ;
     RECT  10.26 44.383 10.797 44.455 ;
     RECT  11.556 43.673 11.574 44.455 ;
     RECT  21.456 42.475 21.51 44.483 ;
     RECT  0.504 44.347 5.778 44.491 ;
     RECT  0.324 44.491 5.778 44.519 ;
     RECT  21.456 44.483 21.474 44.519 ;
     RECT  13.104 44.375 13.77 44.581 ;
     RECT  14.508 44.237 20.502 44.581 ;
     RECT  9.756 44.455 11.574 44.587 ;
     RECT  12.348 44.375 12.366 44.587 ;
     RECT  9.756 44.587 12.366 44.645 ;
     RECT  9.756 44.645 11.574 44.717 ;
     RECT  9.756 44.717 10.854 44.725 ;
     RECT  12.348 44.645 12.366 44.915 ;
     RECT  9.684 44.725 10.854 44.951 ;
     RECT  13.104 44.581 20.502 44.951 ;
     RECT  2.268 44.519 5.778 45.265 ;
     RECT  0.324 44.519 1.458 45.355 ;
     RECT  0.144 45.355 1.458 45.485 ;
     RECT  13.104 44.951 18.99 45.571 ;
     RECT  12.888 45.571 18.99 45.581 ;
     RECT  9.684 44.951 10.797 45.599 ;
     RECT  11.808 45.427 11.826 45.733 ;
     RECT  10.26 45.599 10.797 45.761 ;
     RECT  7.815 43.295 8.097 45.805 ;
     RECT  14.4 45.581 18.99 45.805 ;
     RECT  19.836 44.951 20.502 45.805 ;
     RECT  12.888 45.581 13.497 45.931 ;
     RECT  7.815 45.805 8.406 45.959 ;
     RECT  10.515 45.761 10.797 45.967 ;
     RECT  11.808 45.733 11.97 46.123 ;
     RECT  12.744 45.931 13.497 46.123 ;
     RECT  11.808 46.123 13.497 46.157 ;
     RECT  10.515 45.967 10.926 46.345 ;
     RECT  12.06 46.157 13.497 46.345 ;
     RECT  14.4 45.805 20.502 46.345 ;
     RECT  0.828 45.485 1.458 46.363 ;
     RECT  2.268 45.265 5.85 46.363 ;
     RECT  0.828 46.363 5.85 46.409 ;
     RECT  10.515 46.345 10.962 46.571 ;
     RECT  10.515 46.571 10.926 46.643 ;
     RECT  6.804 46.579 6.822 46.679 ;
     RECT  10.515 46.643 10.89 46.679 ;
     RECT  10.515 46.679 10.854 46.841 ;
     RECT  12.06 46.345 20.502 47.083 ;
     RECT  11.916 47.083 20.502 47.219 ;
     RECT  12.06 47.219 20.502 47.405 ;
     RECT  0.828 46.409 5.706 47.417 ;
     RECT  0.828 47.417 1.458 47.515 ;
     RECT  2.304 47.417 5.706 47.579 ;
     RECT  2.304 47.579 4.014 47.615 ;
     RECT  12.06 47.405 19.134 47.615 ;
     RECT  6.84 46.849 6.858 47.623 ;
     RECT  10.515 46.841 10.797 47.623 ;
     RECT  6.804 47.623 6.858 47.759 ;
     RECT  7.815 45.959 8.097 47.857 ;
     RECT  2.304 47.615 3.726 47.885 ;
     RECT  7.416 47.857 8.097 48.001 ;
     RECT  0.144 47.515 1.458 48.221 ;
     RECT  19.908 47.405 20.502 48.229 ;
     RECT  2.304 47.885 3.582 48.235 ;
     RECT  19.908 48.229 20.538 48.271 ;
     RECT  0.828 48.221 1.458 48.379 ;
     RECT  2.268 48.235 3.582 48.379 ;
     RECT  19.908 48.271 20.61 48.413 ;
     RECT  7.416 48.001 8.586 48.425 ;
     RECT  12.06 47.615 19.026 48.469 ;
     RECT  7.416 48.425 8.097 48.505 ;
     RECT  10.515 47.623 10.854 48.505 ;
     RECT  11.628 48.469 19.026 48.505 ;
     RECT  10.515 48.505 19.026 48.541 ;
     RECT  5.115 47.579 5.706 48.667 ;
     RECT  6.912 48.505 8.097 48.667 ;
     RECT  0.828 48.379 3.582 48.703 ;
     RECT  0.828 48.703 3.726 48.739 ;
     RECT  0.828 48.739 4.014 48.775 ;
     RECT  21.492 46.507 21.51 48.811 ;
     RECT  0.828 48.775 4.338 48.929 ;
     RECT  9.432 48.901 9.45 49.009 ;
     RECT  9.432 49.009 9.63 49.045 ;
     RECT  0.828 48.929 4.158 49.073 ;
     RECT  0.828 49.073 4.014 49.099 ;
     RECT  10.515 48.541 19.062 49.099 ;
     RECT  19.908 48.413 20.502 49.099 ;
     RECT  21.456 48.811 21.51 49.109 ;
     RECT  0.144 49.099 4.014 49.229 ;
     RECT  21.456 49.109 21.474 49.379 ;
     RECT  9.036 49.045 9.63 49.477 ;
     RECT  9.036 49.477 9.738 49.505 ;
     RECT  5.115 48.667 8.097 49.711 ;
     RECT  0.828 49.229 4.014 49.775 ;
     RECT  9.576 49.505 9.738 49.891 ;
     RECT  10.515 49.099 20.502 49.891 ;
     RECT  9.576 49.891 20.502 50.045 ;
     RECT  5.115 49.711 8.586 50.125 ;
     RECT  2.304 49.775 4.014 50.161 ;
     RECT  4.752 50.125 8.586 50.161 ;
     RECT  0.828 49.775 1.458 50.251 ;
     RECT  0.144 50.251 1.458 50.381 ;
     RECT  9.936 50.045 20.502 50.431 ;
     RECT  9.936 50.431 20.538 50.573 ;
     RECT  2.304 50.161 8.586 50.791 ;
     RECT  0.828 50.381 1.458 50.899 ;
     RECT  2.304 50.791 8.766 50.899 ;
     RECT  9.936 50.573 20.502 50.971 ;
     RECT  0.828 50.899 8.766 51.161 ;
     RECT  9.648 50.971 20.502 51.439 ;
     RECT  0.828 51.161 8.37 51.475 ;
     RECT  9.252 51.439 20.502 51.485 ;
     RECT  9.684 51.485 20.502 51.538 ;
     RECT  9.684 51.538 20.538 51.584 ;
     RECT  0.54 51.475 8.37 51.629 ;
     RECT  9.684 51.584 20.502 51.899 ;
     RECT  7.815 51.629 8.37 51.907 ;
     RECT  9.684 51.899 19.134 51.935 ;
     RECT  21.492 50.107 21.51 51.979 ;
     RECT  0.54 51.629 7.002 52.007 ;
     RECT  21.456 51.979 21.51 52.007 ;
     RECT  19.908 51.899 20.502 52.043 ;
     RECT  0.54 52.007 6.894 52.079 ;
     RECT  7.815 51.907 8.55 52.079 ;
     RECT  0.54 52.079 6.858 52.157 ;
     RECT  0.828 52.157 6.858 52.205 ;
     RECT  0.828 52.205 6.822 52.277 ;
     RECT  21.456 52.007 21.474 52.349 ;
     RECT  9.684 51.935 18.954 52.511 ;
     RECT  1.44 52.277 6.822 52.951 ;
     RECT  1.44 52.951 6.93 52.987 ;
     RECT  12.996 52.511 18.954 53.059 ;
     RECT  19.944 52.043 20.502 53.059 ;
     RECT  1.44 52.987 7.074 53.095 ;
     RECT  9.684 52.511 11.97 53.285 ;
     RECT  12.996 53.059 20.502 53.309 ;
     RECT  1.404 53.095 7.074 53.329 ;
     RECT  7.815 52.079 8.262 53.329 ;
     RECT  1.404 53.329 8.262 53.365 ;
     RECT  19.908 53.309 20.502 53.401 ;
     RECT  12.996 53.309 19.098 53.555 ;
     RECT  19.908 53.401 20.538 53.591 ;
     RECT  12.996 53.555 19.062 53.599 ;
     RECT  19.944 53.591 20.538 53.741 ;
     RECT  9.936 53.285 11.97 53.941 ;
     RECT  12.888 53.599 19.062 53.941 ;
     RECT  9.936 53.941 19.062 54.059 ;
     RECT  9.936 54.059 12.222 54.095 ;
     RECT  12.96 54.059 19.062 54.095 ;
     RECT  0.144 53.995 0.162 54.301 ;
     RECT  0.9 53.365 8.262 54.301 ;
     RECT  0.144 54.301 8.262 54.445 ;
     RECT  13.068 54.095 18.954 54.859 ;
     RECT  19.944 53.741 20.502 54.859 ;
     RECT  9.936 54.095 12.15 54.949 ;
     RECT  13.068 54.859 20.502 54.949 ;
     RECT  9.936 54.949 20.502 55.049 ;
     RECT  0.108 54.445 8.262 55.181 ;
     RECT  0.144 55.181 8.262 55.255 ;
     RECT  19.908 55.049 20.502 55.481 ;
     RECT  21.492 53.851 21.51 55.579 ;
     RECT  9.936 55.049 19.134 55.679 ;
     RECT  10.008 55.679 19.134 55.867 ;
     RECT  0.144 55.255 8.838 55.921 ;
     RECT  20.448 55.481 20.502 55.949 ;
     RECT  0.036 55.921 9.09 56.497 ;
     RECT  10.008 55.867 19.386 56.497 ;
     RECT  21.456 55.579 21.51 56.587 ;
     RECT  21.42 56.587 21.51 56.669 ;
     RECT  20.484 55.949 20.502 56.875 ;
     RECT  0.036 56.497 19.386 57.163 ;
     RECT  20.448 56.875 20.502 57.163 ;
     RECT  0.036 57.163 20.502 57.479 ;
     RECT  19.872 57.479 20.502 57.713 ;
     RECT  21.42 56.669 21.438 57.749 ;
     RECT  20.448 57.713 20.502 58.261 ;
     RECT  0.036 57.479 19.134 58.459 ;
     RECT  20.448 58.261 20.538 58.459 ;
     RECT  0.036 58.459 20.538 58.559 ;
     RECT  20.52 58.559 20.538 58.693 ;
     RECT  0.036 58.559 19.422 58.757 ;
     RECT  20.52 58.693 20.574 59.069 ;
     RECT  0.072 58.757 19.422 59.297 ;
     RECT  21.492 59.179 21.51 59.333 ;
     RECT  18.216 59.297 19.422 59.459 ;
     RECT  20.52 59.069 20.538 59.501 ;
     RECT  18.252 59.459 19.422 59.611 ;
     RECT  18.252 59.611 20.502 60.179 ;
     RECT  18.252 60.179 19.422 60.221 ;
     RECT  0.072 59.297 17.478 60.241 ;
     RECT  18.252 60.221 19.386 60.241 ;
     RECT  0.072 60.241 19.386 60.547 ;
     RECT  20.412 60.179 20.502 60.809 ;
     RECT  0.036 60.547 19.386 61.151 ;
     RECT  20.412 60.809 20.466 61.339 ;
     RECT  19.872 61.339 20.466 61.529 ;
     RECT  20.412 61.529 20.466 61.771 ;
     RECT  21.456 60.619 21.51 61.915 ;
     RECT  0.036 61.151 18.99 62.005 ;
     RECT  21.42 61.915 21.51 62.069 ;
     RECT  0.036 62.005 19.026 62.203 ;
     RECT  0.036 62.203 19.386 62.347 ;
     RECT  20.412 61.771 20.538 62.347 ;
     RECT  0.036 62.347 20.538 62.957 ;
     RECT  0.036 62.957 20.502 63.779 ;
     RECT  21.456 62.069 21.51 64.507 ;
     RECT  0.108 63.779 20.502 64.589 ;
     RECT  21.42 64.507 21.51 64.637 ;
     RECT  21.456 64.637 21.51 64.697 ;
     RECT  0.108 64.589 20.322 65.659 ;
     RECT  0.108 65.659 20.502 66.523 ;
     RECT  21.492 64.697 21.51 66.559 ;
     RECT  0.072 66.523 20.502 66.631 ;
     RECT  0.036 66.631 20.502 67.631 ;
     RECT  0.036 67.631 20.466 67.667 ;
     RECT  15.264 67.667 20.466 67.829 ;
     RECT  21.492 66.559 21.582 68.099 ;
     RECT  0.036 67.667 14.526 68.135 ;
     RECT  15.3 67.829 16.542 68.279 ;
     RECT  17.388 67.829 20.466 68.369 ;
     RECT  0.036 68.135 14.058 68.405 ;
     RECT  15.696 68.279 16.542 68.405 ;
     RECT  15.915 68.405 16.542 68.639 ;
     RECT  17.784 68.369 20.466 68.819 ;
     RECT  0.036 68.405 14.022 69.053 ;
     RECT  17.784 68.819 20.322 69.089 ;
     RECT  17.784 69.089 20.25 69.179 ;
     RECT  21.564 68.099 21.582 69.179 ;
     RECT  17.856 69.179 20.25 69.251 ;
     RECT  18.252 69.251 20.25 69.359 ;
     RECT  20.196 69.359 20.25 69.449 ;
     RECT  18.252 69.359 19.134 69.485 ;
     RECT  20.232 69.449 20.25 69.719 ;
     RECT  18.504 69.485 19.134 69.755 ;
     RECT  18.504 69.755 18.897 70.025 ;
     RECT  0.036 69.053 8.097 70.367 ;
     RECT  8.82 69.053 14.022 73.913 ;
     RECT  8.82 73.913 11.574 74.219 ;
     RECT  8.82 74.219 11.43 74.723 ;
     RECT  12.42 73.913 14.022 74.849 ;
     RECT  12.42 74.849 13.497 75.119 ;
     RECT  0.036 70.367 6.966 77.189 ;
     RECT  0.036 77.189 5.397 77.279 ;
     RECT  8.82 74.723 10.797 77.819 ;
     RECT  8.856 77.819 10.797 78.359 ;
     RECT  0.036 77.279 4.374 78.509 ;
     RECT  6.408 77.189 6.966 78.629 ;
     RECT  6.408 78.629 6.426 78.899 ;
     RECT  12.744 75.119 13.497 79.169 ;
     RECT  9.396 78.359 10.797 79.709 ;
     RECT  0.036 78.509 2.697 79.717 ;
     RECT  9.396 79.709 9.414 79.979 ;
     RECT  0.036 79.717 2.826 80.381 ;
     RECT  3.708 78.509 4.374 82.301 ;
     RECT  4.356 82.301 4.374 82.541 ;
     RECT  0.036 80.381 2.697 83.981 ;
     RECT  0.036 83.981 1.458 84.125 ;
     RECT  0.036 84.125 0.846 84.413 ;
     RECT  0.036 84.413 0.27 84.641 ;
     RECT  0.108 84.641 0.27 84.701 ;
     RECT  0.108 84.701 0.198 84.845 ;
     RECT  0.108 84.845 0.126 84.989 ;
     RECT  2.415 83.981 2.697 92.627 ;
     RECT  5.115 77.279 5.397 92.627 ;
     RECT  7.815 70.367 8.097 92.627 ;
     RECT  10.515 79.709 10.797 92.627 ;
     RECT  13.215 79.169 13.497 92.627 ;
     RECT  15.915 68.639 16.197 92.627 ;
     RECT  18.615 70.025 18.897 92.627 ;
     RECT  2.415 92.627 2.505 92.897 ;
     RECT  5.115 92.627 5.205 92.897 ;
     RECT  7.815 92.627 7.905 92.897 ;
     RECT  10.515 92.627 10.605 92.897 ;
     RECT  13.215 92.627 13.305 92.897 ;
     RECT  15.915 92.627 16.005 92.897 ;
     RECT  18.615 92.627 18.705 92.897 ;
    LAYER M4 ;
     RECT  0.084 66.672 0.133 66.696 ;
     RECT  0.06 66.696 0.133 66.816 ;
     RECT  0.084 66.816 0.133 66.84 ;
     RECT  0.06 66.84 0.133 66.96 ;
     RECT  0.084 66.96 0.133 66.984 ;
     RECT  0.06 66.984 0.133 67.104 ;
     RECT  0.084 67.104 0.133 67.128 ;
     RECT  0.06 67.128 0.133 67.248 ;
     RECT  0.084 67.248 0.133 67.272 ;
     RECT  0.06 67.272 0.133 67.392 ;
     RECT  0.084 67.392 0.133 67.416 ;
     RECT  0.06 67.416 0.133 67.536 ;
     RECT  0.084 67.536 0.133 67.56 ;
     RECT  0.06 67.56 0.133 67.68 ;
     RECT  0.084 67.68 0.133 67.704 ;
     RECT  0.06 67.704 0.133 67.824 ;
     RECT  0.084 67.824 0.133 67.848 ;
     RECT  0.06 67.848 0.133 67.968 ;
     RECT  0.084 67.968 0.133 67.992 ;
     RECT  0.06 67.992 0.133 68.112 ;
     RECT  0.084 68.112 0.133 68.136 ;
     RECT  0.06 68.136 0.133 68.256 ;
     RECT  0.084 68.256 0.133 68.28 ;
     RECT  0.06 68.28 0.133 68.4 ;
     RECT  0.084 68.4 0.133 68.424 ;
     RECT  0.06 68.424 0.133 68.544 ;
     RECT  0.084 68.544 0.133 68.568 ;
     RECT  0.06 68.568 0.133 68.688 ;
     RECT  0.084 68.688 0.133 68.712 ;
     RECT  0.06 68.712 0.133 68.832 ;
     RECT  0.084 68.832 0.133 68.856 ;
     RECT  0.06 68.856 0.133 68.976 ;
     RECT  0.084 68.976 0.133 69 ;
     RECT  0.06 69 0.133 69.12 ;
     RECT  0.084 69.12 0.133 69.144 ;
     RECT  0.06 69.144 0.133 69.264 ;
     RECT  0.084 69.264 0.133 69.288 ;
     RECT  0.06 69.288 0.133 69.408 ;
     RECT  0.084 69.408 0.133 69.432 ;
     RECT  0.06 69.432 0.133 69.552 ;
     RECT  0.084 69.552 0.133 69.576 ;
     RECT  0.06 69.576 0.133 69.696 ;
     RECT  0.084 69.696 0.133 69.72 ;
     RECT  0.06 69.72 0.133 69.84 ;
     RECT  0.084 69.84 0.133 69.864 ;
     RECT  0.06 69.864 0.133 69.984 ;
     RECT  0.084 69.984 0.133 70.008 ;
     RECT  0.06 70.008 0.133 70.128 ;
     RECT  0.084 70.128 0.133 70.152 ;
     RECT  0.06 70.152 0.133 70.272 ;
     RECT  0.084 70.272 0.133 70.296 ;
     RECT  0.06 70.296 0.133 70.416 ;
     RECT  0.084 70.416 0.133 70.44 ;
     RECT  0.06 70.44 0.133 70.56 ;
     RECT  0.084 70.56 0.133 70.584 ;
     RECT  0.06 70.584 0.133 70.704 ;
     RECT  0.084 70.704 0.133 70.728 ;
     RECT  0.06 70.728 0.133 70.848 ;
     RECT  0.084 70.848 0.133 70.872 ;
     RECT  0.06 70.872 0.133 70.992 ;
     RECT  0.084 70.992 0.133 71.016 ;
     RECT  0.06 71.016 0.133 71.136 ;
     RECT  0.084 71.136 0.133 71.16 ;
     RECT  0.06 71.16 0.133 71.28 ;
     RECT  0.084 71.28 0.133 71.304 ;
     RECT  0.06 71.304 0.133 71.424 ;
     RECT  0.084 71.424 0.133 71.448 ;
     RECT  0.06 71.448 0.133 71.568 ;
     RECT  0.084 71.568 0.133 71.592 ;
     RECT  0.06 71.592 0.133 71.712 ;
     RECT  0.084 71.712 0.133 71.736 ;
     RECT  0.06 71.736 0.133 71.856 ;
     RECT  0.084 71.856 0.133 71.88 ;
     RECT  0.06 71.88 0.133 72 ;
     RECT  0.084 72 0.133 72.024 ;
     RECT  0.06 72.024 0.133 72.144 ;
     RECT  0.084 72.144 0.133 72.168 ;
     RECT  0.06 72.168 0.133 72.288 ;
     RECT  0.084 72.288 0.133 72.312 ;
     RECT  0.06 72.312 0.133 72.432 ;
     RECT  0.084 72.432 0.133 72.456 ;
     RECT  0.06 72.456 0.133 72.576 ;
     RECT  0.084 72.576 0.133 72.6 ;
     RECT  0.06 72.6 0.133 72.72 ;
     RECT  0.084 72.72 0.133 72.744 ;
     RECT  0.06 72.744 0.133 72.864 ;
     RECT  0.084 72.864 0.133 72.888 ;
     RECT  0.06 72.888 0.133 73.008 ;
     RECT  0.084 73.008 0.133 73.032 ;
     RECT  0.06 73.032 0.133 73.152 ;
     RECT  0.084 73.152 0.133 73.176 ;
     RECT  0.06 73.176 0.133 73.296 ;
     RECT  0.084 73.296 0.133 73.32 ;
     RECT  0.06 73.32 0.133 73.44 ;
     RECT  0.084 73.44 0.133 73.464 ;
     RECT  0.06 73.464 0.133 73.584 ;
     RECT  0.084 73.584 0.133 73.608 ;
     RECT  0.06 73.608 0.133 73.728 ;
     RECT  0.084 73.728 0.133 73.752 ;
     RECT  0.06 73.752 0.133 73.872 ;
     RECT  0.084 73.872 0.133 73.896 ;
     RECT  0.06 73.896 0.133 74.016 ;
     RECT  0.084 74.016 0.133 74.04 ;
     RECT  0.06 74.04 0.133 74.16 ;
     RECT  0.084 74.16 0.133 74.184 ;
     RECT  0.06 74.184 0.133 74.304 ;
     RECT  0.084 74.304 0.133 74.328 ;
     RECT  0.06 74.328 0.133 74.448 ;
     RECT  0.084 74.448 0.133 74.472 ;
     RECT  0.06 74.472 0.133 74.592 ;
     RECT  0.084 74.592 0.133 74.616 ;
     RECT  0.06 74.616 0.133 74.736 ;
     RECT  0.084 74.736 0.133 74.76 ;
     RECT  0.06 74.76 0.133 74.88 ;
     RECT  0.084 74.88 0.133 74.904 ;
     RECT  0.06 74.904 0.133 75.024 ;
     RECT  0.084 75.024 0.133 75.048 ;
     RECT  0.06 75.048 0.133 75.168 ;
     RECT  0.084 75.168 0.133 75.192 ;
     RECT  0.06 75.192 0.133 75.312 ;
     RECT  0.084 75.312 0.133 75.336 ;
     RECT  0.06 75.336 0.133 75.456 ;
     RECT  0.084 75.456 0.133 75.48 ;
     RECT  0.06 75.48 0.133 75.6 ;
     RECT  0.084 75.6 0.133 75.624 ;
     RECT  0.06 75.624 0.133 75.744 ;
     RECT  0.084 75.744 0.133 75.768 ;
     RECT  0.06 75.768 0.133 75.888 ;
     RECT  0.084 75.888 0.133 75.912 ;
     RECT  0.06 75.912 0.133 76.032 ;
     RECT  0.084 76.032 0.133 76.056 ;
     RECT  0.06 76.056 0.133 76.176 ;
     RECT  0.084 76.176 0.133 76.2 ;
     RECT  0.06 76.2 0.133 76.32 ;
     RECT  0.084 76.32 0.133 76.344 ;
     RECT  0.06 76.344 0.133 76.464 ;
     RECT  0.084 76.464 0.133 76.488 ;
     RECT  0.06 76.488 0.133 76.608 ;
     RECT  0.084 76.608 0.133 76.632 ;
     RECT  0.06 76.632 0.133 76.752 ;
     RECT  0.084 76.752 0.133 76.776 ;
     RECT  0.06 76.776 0.133 76.896 ;
     RECT  0.084 76.896 0.133 76.92 ;
     RECT  0.06 76.92 0.133 77.04 ;
     RECT  0.084 77.04 0.133 77.064 ;
     RECT  0.06 77.064 0.133 77.184 ;
     RECT  0.084 77.184 0.133 77.208 ;
     RECT  0.06 77.208 0.133 77.328 ;
     RECT  0.084 77.328 0.133 77.352 ;
     RECT  0.06 77.352 0.133 77.472 ;
     RECT  0.084 77.472 0.133 77.496 ;
     RECT  0.06 77.496 0.133 77.616 ;
     RECT  0.084 77.616 0.133 77.64 ;
     RECT  0.06 77.64 0.133 77.76 ;
     RECT  0.084 77.76 0.133 77.784 ;
     RECT  0.06 77.784 0.133 77.904 ;
     RECT  0.084 77.904 0.133 77.928 ;
     RECT  0.06 77.928 0.133 78.048 ;
     RECT  0.084 78.048 0.133 78.072 ;
     RECT  0.06 78.072 0.133 78.192 ;
     RECT  0.084 78.192 0.133 78.216 ;
     RECT  0.06 78.216 0.133 78.336 ;
     RECT  0.084 78.336 0.133 78.36 ;
     RECT  0.06 78.36 0.133 78.48 ;
     RECT  0.084 78.48 0.133 78.504 ;
     RECT  0.06 78.504 0.133 78.624 ;
     RECT  0.084 78.624 0.133 78.648 ;
     RECT  0.06 78.648 0.133 78.768 ;
     RECT  0.084 78.768 0.133 78.792 ;
     RECT  0.06 78.792 0.133 78.912 ;
     RECT  0.084 78.912 0.133 78.936 ;
     RECT  0.06 78.936 0.133 79.056 ;
     RECT  0.084 79.056 0.133 79.08 ;
     RECT  0.06 79.08 0.133 79.2 ;
     RECT  0.084 79.2 0.133 79.224 ;
     RECT  0.06 79.224 0.133 79.344 ;
     RECT  0.084 79.344 0.133 79.368 ;
     RECT  0.06 79.368 0.133 79.488 ;
     RECT  0.084 79.488 0.133 79.512 ;
     RECT  0.06 79.512 0.133 79.632 ;
     RECT  0.084 79.632 0.133 79.656 ;
     RECT  0.06 79.656 0.133 79.776 ;
     RECT  0.084 79.776 0.133 79.8 ;
     RECT  0.06 79.8 0.133 79.92 ;
     RECT  0.084 79.92 0.133 79.944 ;
     RECT  0.06 79.944 0.133 80.064 ;
     RECT  0.084 80.064 0.133 80.088 ;
     RECT  0.06 80.088 0.133 80.208 ;
     RECT  0.084 80.208 0.133 80.232 ;
     RECT  0.06 80.232 0.133 80.352 ;
     RECT  0.084 80.352 0.133 80.376 ;
     RECT  0.06 80.376 0.133 80.496 ;
     RECT  0.084 80.496 0.133 80.52 ;
     RECT  0.06 80.52 0.133 80.64 ;
     RECT  0.084 80.64 0.133 80.664 ;
     RECT  0.06 80.664 0.133 80.784 ;
     RECT  0.084 80.784 0.133 80.808 ;
     RECT  0.06 80.808 0.133 80.928 ;
     RECT  0.084 80.928 0.133 80.952 ;
     RECT  0.06 80.952 0.133 81.072 ;
     RECT  0.084 81.072 0.133 81.096 ;
     RECT  0.06 81.096 0.133 81.216 ;
     RECT  0.084 81.216 0.133 81.24 ;
     RECT  0.06 81.24 0.133 81.36 ;
     RECT  0.084 81.36 0.133 81.384 ;
     RECT  0.06 81.384 0.133 81.504 ;
     RECT  0.084 81.504 0.133 81.528 ;
     RECT  0.06 81.528 0.133 81.648 ;
     RECT  0.084 81.648 0.133 81.672 ;
     RECT  0.06 81.672 0.133 81.792 ;
     RECT  0.084 81.792 0.133 81.816 ;
     RECT  0.06 81.816 0.133 81.936 ;
     RECT  0.084 81.936 0.133 81.96 ;
     RECT  0.06 81.96 0.133 82.08 ;
     RECT  0.084 82.08 0.133 82.104 ;
     RECT  0.06 82.104 0.133 82.224 ;
     RECT  0.084 82.224 0.133 82.248 ;
     RECT  0.06 82.248 0.133 82.368 ;
     RECT  0.084 82.368 0.133 82.392 ;
     RECT  0.06 82.392 0.133 82.512 ;
     RECT  0.084 82.512 0.133 82.536 ;
     RECT  0.06 82.536 0.133 82.656 ;
     RECT  0.084 82.656 0.133 82.68 ;
     RECT  0.06 82.68 0.133 82.8 ;
     RECT  0.084 82.8 0.133 82.824 ;
     RECT  0.06 82.824 0.133 82.944 ;
     RECT  0.084 82.944 0.133 82.968 ;
     RECT  0.06 82.968 0.133 83.088 ;
     RECT  0.084 83.088 0.133 83.112 ;
     RECT  0.06 83.112 0.133 83.232 ;
     RECT  0.084 83.232 0.133 83.256 ;
     RECT  0.06 83.256 0.133 83.376 ;
     RECT  0.084 83.376 0.133 83.4 ;
     RECT  0.06 83.4 0.133 83.52 ;
     RECT  0.084 83.52 0.133 83.544 ;
     RECT  0.06 83.544 0.133 83.664 ;
     RECT  0.084 83.664 0.133 83.688 ;
     RECT  0.06 83.688 0.133 83.808 ;
     RECT  0.084 83.808 0.133 83.832 ;
     RECT  0.06 83.832 0.133 83.952 ;
     RECT  0.084 83.952 0.133 83.976 ;
     RECT  0.06 83.976 0.133 84.096 ;
     RECT  0.084 84.096 0.133 84.12 ;
     RECT  0.06 84.12 0.133 84.24 ;
     RECT  0.084 84.24 0.133 84.264 ;
     RECT  0.06 84.264 0.133 84.384 ;
     RECT  0.084 84.384 0.133 84.408 ;
     RECT  0.06 84.408 0.133 84.528 ;
     RECT  0.084 84.528 0.133 84.552 ;
     RECT  0.06 84.552 0.133 84.672 ;
     RECT  0.084 84.672 0.133 84.696 ;
     RECT  0.06 84.696 0.133 84.816 ;
     RECT  0.084 84.816 0.133 84.84 ;
     RECT  0.06 84.84 0.133 84.96 ;
     RECT  0.084 84.96 0.133 84.984 ;
     RECT  0.133 66.576 0.137 84.984 ;
     RECT  0.084 9.072 0.173 9.096 ;
     RECT  0.06 9.096 0.173 9.216 ;
     RECT  0.084 9.216 0.173 9.24 ;
     RECT  0.06 9.24 0.173 9.36 ;
     RECT  0.084 9.36 0.173 9.384 ;
     RECT  0.06 9.384 0.173 9.504 ;
     RECT  0.084 9.504 0.173 9.528 ;
     RECT  0.06 9.528 0.173 9.648 ;
     RECT  0.084 9.648 0.173 9.672 ;
     RECT  0.06 9.672 0.173 9.792 ;
     RECT  0.084 9.792 0.173 9.816 ;
     RECT  0.06 9.816 0.173 9.936 ;
     RECT  0.084 9.936 0.173 9.96 ;
     RECT  0.06 9.96 0.173 10.08 ;
     RECT  0.084 10.08 0.173 10.104 ;
     RECT  0.06 10.104 0.173 10.224 ;
     RECT  0.084 10.224 0.173 10.248 ;
     RECT  0.06 10.248 0.173 10.368 ;
     RECT  0.084 10.368 0.173 10.392 ;
     RECT  0.06 10.392 0.173 10.512 ;
     RECT  0.084 10.512 0.173 10.536 ;
     RECT  0.06 10.536 0.173 10.656 ;
     RECT  0.084 10.656 0.173 10.68 ;
     RECT  0.06 10.68 0.173 10.8 ;
     RECT  0.084 10.8 0.173 10.824 ;
     RECT  0.06 10.824 0.173 10.944 ;
     RECT  0.084 10.944 0.173 10.968 ;
     RECT  0.06 10.968 0.173 11.088 ;
     RECT  0.084 11.088 0.173 11.112 ;
     RECT  0.06 11.112 0.173 11.232 ;
     RECT  0.084 11.232 0.173 11.256 ;
     RECT  0.06 11.256 0.173 11.376 ;
     RECT  0.084 11.376 0.173 11.4 ;
     RECT  0.06 11.4 0.173 11.52 ;
     RECT  0.084 11.52 0.173 11.544 ;
     RECT  0.06 11.544 0.173 11.664 ;
     RECT  0.084 11.664 0.173 11.688 ;
     RECT  0.06 11.688 0.173 11.808 ;
     RECT  0.084 11.808 0.173 11.832 ;
     RECT  0.06 11.832 0.173 11.952 ;
     RECT  0.084 11.952 0.173 11.976 ;
     RECT  0.06 11.976 0.173 12.096 ;
     RECT  0.084 12.096 0.173 12.12 ;
     RECT  0.06 12.12 0.173 12.24 ;
     RECT  0.084 12.24 0.173 12.264 ;
     RECT  0.06 12.264 0.173 12.384 ;
     RECT  0.084 12.384 0.173 12.408 ;
     RECT  0.06 12.408 0.173 12.528 ;
     RECT  0.084 12.528 0.173 12.552 ;
     RECT  0.06 12.552 0.173 12.672 ;
     RECT  0.084 12.672 0.173 12.696 ;
     RECT  0.06 12.696 0.173 12.816 ;
     RECT  0.084 12.816 0.173 12.84 ;
     RECT  0.06 12.84 0.173 12.96 ;
     RECT  0.084 12.96 0.173 12.984 ;
     RECT  0.06 12.984 0.173 13.104 ;
     RECT  0.084 13.104 0.173 13.128 ;
     RECT  0.06 13.128 0.173 13.248 ;
     RECT  0.084 13.248 0.173 13.272 ;
     RECT  0.06 13.272 0.173 13.392 ;
     RECT  0.084 13.392 0.173 13.416 ;
     RECT  0.06 13.416 0.173 13.536 ;
     RECT  0.084 13.536 0.173 13.56 ;
     RECT  0.06 13.56 0.173 13.68 ;
     RECT  0.084 13.68 0.173 13.704 ;
     RECT  0.06 13.704 0.173 13.824 ;
     RECT  0.084 13.824 0.173 13.848 ;
     RECT  0.06 13.848 0.173 13.968 ;
     RECT  0.084 13.968 0.173 13.992 ;
     RECT  0.06 13.992 0.173 14.112 ;
     RECT  0.084 14.112 0.173 14.136 ;
     RECT  0.06 14.136 0.173 14.256 ;
     RECT  0.084 14.256 0.173 14.28 ;
     RECT  0.06 14.28 0.173 14.4 ;
     RECT  0.084 14.4 0.173 14.424 ;
     RECT  0.06 14.424 0.173 14.544 ;
     RECT  0.084 14.544 0.173 14.568 ;
     RECT  0.06 14.568 0.173 14.688 ;
     RECT  0.084 14.688 0.173 14.712 ;
     RECT  0.06 14.712 0.173 14.832 ;
     RECT  0.084 14.832 0.173 14.856 ;
     RECT  0.06 14.856 0.173 14.976 ;
     RECT  0.084 14.976 0.173 15 ;
     RECT  0.06 15 0.173 15.12 ;
     RECT  0.084 15.12 0.173 15.144 ;
     RECT  0.06 15.144 0.173 15.264 ;
     RECT  0.084 15.264 0.173 15.288 ;
     RECT  0.06 15.288 0.173 15.408 ;
     RECT  0.084 15.408 0.173 15.432 ;
     RECT  0.06 15.432 0.173 15.552 ;
     RECT  0.084 15.552 0.173 15.576 ;
     RECT  0.06 15.576 0.173 15.696 ;
     RECT  0.084 15.696 0.173 15.72 ;
     RECT  0.06 15.72 0.173 15.84 ;
     RECT  0.084 15.84 0.173 15.864 ;
     RECT  0.06 15.864 0.173 15.984 ;
     RECT  0.084 15.984 0.173 16.008 ;
     RECT  0.06 16.008 0.173 16.128 ;
     RECT  0.084 16.128 0.173 16.152 ;
     RECT  0.06 16.152 0.173 16.272 ;
     RECT  0.084 16.272 0.173 16.296 ;
     RECT  0.06 16.296 0.173 16.416 ;
     RECT  0.084 16.416 0.173 16.44 ;
     RECT  0.06 16.44 0.173 16.56 ;
     RECT  0.084 16.56 0.173 16.584 ;
     RECT  0.06 16.584 0.173 16.704 ;
     RECT  0.084 16.704 0.173 16.728 ;
     RECT  0.06 16.728 0.173 16.848 ;
     RECT  0.084 16.848 0.173 16.872 ;
     RECT  0.06 16.872 0.173 16.992 ;
     RECT  0.084 16.992 0.173 17.016 ;
     RECT  0.06 17.016 0.173 17.136 ;
     RECT  0.084 17.136 0.173 17.16 ;
     RECT  0.06 17.16 0.173 17.28 ;
     RECT  0.084 17.28 0.173 17.304 ;
     RECT  0.06 17.304 0.173 17.424 ;
     RECT  0.084 17.424 0.173 17.448 ;
     RECT  0.06 17.448 0.173 17.568 ;
     RECT  0.084 17.568 0.173 17.592 ;
     RECT  0.06 17.592 0.173 17.712 ;
     RECT  0.084 17.712 0.173 17.736 ;
     RECT  0.06 17.736 0.173 17.856 ;
     RECT  0.084 17.856 0.173 17.88 ;
     RECT  0.06 17.88 0.173 18 ;
     RECT  0.084 18 0.173 18.024 ;
     RECT  0.06 18.024 0.173 18.144 ;
     RECT  0.084 18.144 0.173 18.168 ;
     RECT  0.06 18.168 0.173 18.288 ;
     RECT  0.084 18.288 0.173 18.312 ;
     RECT  0.06 18.312 0.173 18.432 ;
     RECT  0.084 18.432 0.173 18.456 ;
     RECT  0.06 18.456 0.173 18.576 ;
     RECT  0.084 18.576 0.173 18.6 ;
     RECT  0.06 18.6 0.173 18.72 ;
     RECT  0.084 18.72 0.173 18.744 ;
     RECT  0.06 18.744 0.173 18.864 ;
     RECT  0.084 18.864 0.173 18.888 ;
     RECT  0.06 18.888 0.173 19.008 ;
     RECT  0.084 19.008 0.173 19.032 ;
     RECT  0.06 19.032 0.173 19.152 ;
     RECT  0.084 19.152 0.173 19.176 ;
     RECT  0.06 19.176 0.173 19.296 ;
     RECT  0.084 19.296 0.173 19.32 ;
     RECT  0.06 19.32 0.173 19.44 ;
     RECT  0.084 19.44 0.173 19.464 ;
     RECT  0.06 19.464 0.173 19.584 ;
     RECT  0.084 19.584 0.173 19.608 ;
     RECT  0.06 19.608 0.173 19.728 ;
     RECT  0.084 19.728 0.173 19.752 ;
     RECT  0.06 19.752 0.173 19.872 ;
     RECT  0.084 19.872 0.173 19.896 ;
     RECT  0.06 19.896 0.173 20.016 ;
     RECT  0.084 20.016 0.173 20.04 ;
     RECT  0.06 20.04 0.173 20.16 ;
     RECT  0.084 20.16 0.173 20.184 ;
     RECT  0.06 20.184 0.173 20.304 ;
     RECT  0.084 20.304 0.173 20.328 ;
     RECT  0.06 20.328 0.173 20.448 ;
     RECT  0.084 20.448 0.173 20.472 ;
     RECT  0.06 20.472 0.173 20.592 ;
     RECT  0.084 20.592 0.173 20.616 ;
     RECT  0.06 20.616 0.173 20.736 ;
     RECT  0.084 20.736 0.173 20.76 ;
     RECT  0.06 20.76 0.173 20.88 ;
     RECT  0.084 20.88 0.173 20.904 ;
     RECT  0.06 20.904 0.173 21.024 ;
     RECT  0.084 21.024 0.173 21.048 ;
     RECT  0.06 21.048 0.173 21.168 ;
     RECT  0.084 21.168 0.173 21.192 ;
     RECT  0.06 21.192 0.173 21.312 ;
     RECT  0.084 21.312 0.173 21.336 ;
     RECT  0.06 21.336 0.173 21.456 ;
     RECT  0.084 21.456 0.173 21.48 ;
     RECT  0.06 21.48 0.173 21.6 ;
     RECT  0.084 21.6 0.173 21.624 ;
     RECT  0.06 21.624 0.173 21.744 ;
     RECT  0.084 21.744 0.173 21.768 ;
     RECT  0.06 21.768 0.173 21.888 ;
     RECT  0.084 21.888 0.173 21.912 ;
     RECT  0.06 21.912 0.173 22.032 ;
     RECT  0.084 22.032 0.173 22.056 ;
     RECT  0.06 22.056 0.173 22.176 ;
     RECT  0.084 22.176 0.173 22.2 ;
     RECT  0.06 22.2 0.173 22.32 ;
     RECT  0.084 22.32 0.173 22.344 ;
     RECT  0.06 22.344 0.173 22.464 ;
     RECT  0.084 22.464 0.173 22.488 ;
     RECT  0.06 22.488 0.173 22.608 ;
     RECT  0.084 22.608 0.173 22.632 ;
     RECT  0.06 22.632 0.173 22.752 ;
     RECT  0.084 22.752 0.173 22.776 ;
     RECT  0.06 22.776 0.173 22.896 ;
     RECT  0.084 22.896 0.173 22.92 ;
     RECT  0.06 22.92 0.173 23.04 ;
     RECT  0.084 23.04 0.173 23.064 ;
     RECT  0.06 23.064 0.173 23.184 ;
     RECT  0.084 23.184 0.173 23.208 ;
     RECT  0.06 23.208 0.173 23.328 ;
     RECT  0.084 23.328 0.173 23.352 ;
     RECT  0.06 23.352 0.173 23.472 ;
     RECT  0.084 23.472 0.173 23.496 ;
     RECT  0.06 23.496 0.173 23.616 ;
     RECT  0.084 23.616 0.173 23.64 ;
     RECT  0.06 23.64 0.173 23.76 ;
     RECT  0.084 23.76 0.173 23.784 ;
     RECT  0.06 23.784 0.173 23.904 ;
     RECT  0.084 23.904 0.173 23.928 ;
     RECT  0.06 23.928 0.173 24.048 ;
     RECT  0.084 24.048 0.173 24.072 ;
     RECT  0.06 24.072 0.173 24.192 ;
     RECT  0.084 24.192 0.173 24.216 ;
     RECT  0.06 24.216 0.173 24.336 ;
     RECT  0.084 24.336 0.173 24.36 ;
     RECT  0.06 24.36 0.173 24.48 ;
     RECT  0.084 24.48 0.173 24.504 ;
     RECT  0.06 24.504 0.173 24.624 ;
     RECT  0.084 24.624 0.173 24.648 ;
     RECT  0.06 24.648 0.173 24.768 ;
     RECT  0.084 24.768 0.173 24.792 ;
     RECT  0.06 24.792 0.173 24.912 ;
     RECT  0.084 24.912 0.173 24.936 ;
     RECT  0.06 24.936 0.173 25.056 ;
     RECT  0.084 25.056 0.173 25.08 ;
     RECT  0.06 25.08 0.173 25.2 ;
     RECT  0.084 25.2 0.173 25.224 ;
     RECT  0.06 25.224 0.173 25.344 ;
     RECT  0.084 25.344 0.173 25.368 ;
     RECT  0.06 25.368 0.173 25.488 ;
     RECT  0.084 25.488 0.173 25.512 ;
     RECT  0.06 25.512 0.173 25.632 ;
     RECT  0.084 25.632 0.173 25.656 ;
     RECT  0.06 25.656 0.173 25.776 ;
     RECT  0.084 25.776 0.173 25.8 ;
     RECT  0.06 25.8 0.173 25.92 ;
     RECT  0.084 25.92 0.173 25.944 ;
     RECT  0.06 25.944 0.173 26.064 ;
     RECT  0.084 26.064 0.173 26.088 ;
     RECT  0.06 26.088 0.173 26.208 ;
     RECT  0.084 26.208 0.173 26.232 ;
     RECT  0.06 26.232 0.173 26.352 ;
     RECT  0.084 26.352 0.173 26.376 ;
     RECT  0.06 26.376 0.173 26.496 ;
     RECT  0.084 26.496 0.173 26.52 ;
     RECT  0.06 26.52 0.173 26.64 ;
     RECT  0.084 26.64 0.173 26.664 ;
     RECT  0.06 26.664 0.173 26.784 ;
     RECT  0.084 26.784 0.173 26.808 ;
     RECT  0.06 26.808 0.173 26.928 ;
     RECT  0.084 26.928 0.173 26.952 ;
     RECT  0.06 26.952 0.173 27.072 ;
     RECT  0.084 27.072 0.173 27.096 ;
     RECT  0.06 27.096 0.173 27.216 ;
     RECT  0.084 27.216 0.173 27.24 ;
     RECT  0.06 27.24 0.173 27.36 ;
     RECT  0.084 27.36 0.173 27.384 ;
     RECT  0.06 27.384 0.173 27.504 ;
     RECT  0.084 27.504 0.173 27.528 ;
     RECT  0.06 27.528 0.173 27.648 ;
     RECT  0.084 27.648 0.173 27.672 ;
     RECT  0.06 27.672 0.173 27.792 ;
     RECT  0.084 27.792 0.173 27.816 ;
     RECT  0.06 27.816 0.173 27.936 ;
     RECT  0.084 27.936 0.173 27.96 ;
     RECT  0.06 27.96 0.173 28.08 ;
     RECT  0.084 28.08 0.173 28.104 ;
     RECT  0.06 28.104 0.173 28.224 ;
     RECT  0.084 28.224 0.173 28.248 ;
     RECT  0.06 28.248 0.173 28.368 ;
     RECT  0.084 28.368 0.173 28.392 ;
     RECT  0.06 28.392 0.173 28.512 ;
     RECT  0.084 28.512 0.173 28.536 ;
     RECT  0.06 28.536 0.173 28.656 ;
     RECT  0.084 28.656 0.173 28.68 ;
     RECT  0.06 28.68 0.173 28.8 ;
     RECT  0.084 28.8 0.173 28.824 ;
     RECT  0.06 28.824 0.173 28.944 ;
     RECT  0.084 28.944 0.173 28.968 ;
     RECT  0.06 28.968 0.173 29.088 ;
     RECT  0.084 29.088 0.173 29.112 ;
     RECT  0.06 29.112 0.173 29.232 ;
     RECT  0.084 29.232 0.173 29.256 ;
     RECT  0.06 29.256 0.173 29.376 ;
     RECT  0.084 29.376 0.173 29.4 ;
     RECT  0.06 29.4 0.173 29.52 ;
     RECT  0.084 29.52 0.173 29.544 ;
     RECT  0.06 29.544 0.173 29.664 ;
     RECT  0.084 29.664 0.173 29.688 ;
     RECT  0.06 29.688 0.173 29.808 ;
     RECT  0.084 29.808 0.173 29.832 ;
     RECT  0.06 29.832 0.173 29.952 ;
     RECT  0.084 29.952 0.173 29.976 ;
     RECT  0.06 29.976 0.173 30.096 ;
     RECT  0.084 30.096 0.173 30.12 ;
     RECT  0.06 30.12 0.173 30.24 ;
     RECT  0.084 30.24 0.173 30.264 ;
     RECT  0.06 30.264 0.173 30.384 ;
     RECT  0.084 30.384 0.173 30.408 ;
     RECT  0.06 30.408 0.173 30.528 ;
     RECT  0.084 30.528 0.173 30.552 ;
     RECT  0.06 30.552 0.173 30.672 ;
     RECT  0.084 30.672 0.173 30.696 ;
     RECT  0.06 30.696 0.173 30.816 ;
     RECT  0.084 30.816 0.173 30.84 ;
     RECT  0.06 30.84 0.173 30.96 ;
     RECT  0.084 30.96 0.173 30.984 ;
     RECT  0.06 30.984 0.173 31.104 ;
     RECT  0.084 31.104 0.173 31.128 ;
     RECT  0.06 31.128 0.173 31.248 ;
     RECT  0.084 31.248 0.173 31.272 ;
     RECT  0.06 31.272 0.173 31.392 ;
     RECT  0.084 31.392 0.173 31.416 ;
     RECT  0.06 31.416 0.173 31.536 ;
     RECT  0.084 31.536 0.173 31.56 ;
     RECT  0.06 31.56 0.173 31.68 ;
     RECT  0.084 31.68 0.173 31.704 ;
     RECT  0.06 31.704 0.173 31.824 ;
     RECT  0.084 31.824 0.173 31.848 ;
     RECT  0.06 31.848 0.173 31.968 ;
     RECT  0.084 31.968 0.173 31.992 ;
     RECT  0.06 31.992 0.173 32.112 ;
     RECT  0.084 32.112 0.173 32.136 ;
     RECT  0.06 32.136 0.173 32.256 ;
     RECT  0.084 32.256 0.173 32.28 ;
     RECT  0.06 32.28 0.173 32.4 ;
     RECT  0.084 32.4 0.173 32.424 ;
     RECT  0.06 32.424 0.173 32.544 ;
     RECT  0.084 32.544 0.173 32.568 ;
     RECT  0.06 32.568 0.173 32.688 ;
     RECT  0.084 32.688 0.173 32.712 ;
     RECT  0.06 32.712 0.173 32.832 ;
     RECT  0.084 32.832 0.173 32.856 ;
     RECT  0.06 32.856 0.173 32.976 ;
     RECT  0.084 32.976 0.173 33 ;
     RECT  0.06 33 0.173 33.12 ;
     RECT  0.084 33.12 0.173 33.144 ;
     RECT  0.06 33.144 0.173 33.264 ;
     RECT  0.084 33.264 0.173 33.288 ;
     RECT  0.06 33.288 0.173 33.408 ;
     RECT  0.084 33.408 0.173 33.432 ;
     RECT  0.06 33.432 0.173 33.552 ;
     RECT  0.084 33.552 0.173 33.576 ;
     RECT  0.06 33.576 0.173 33.696 ;
     RECT  0.084 33.696 0.173 33.72 ;
     RECT  0.06 33.72 0.173 33.84 ;
     RECT  0.084 33.84 0.173 33.864 ;
     RECT  0.06 33.864 0.173 33.984 ;
     RECT  0.084 33.984 0.173 34.008 ;
     RECT  0.06 34.008 0.173 34.128 ;
     RECT  0.084 34.128 0.173 34.152 ;
     RECT  0.06 34.152 0.173 34.272 ;
     RECT  0.084 34.272 0.173 34.296 ;
     RECT  0.06 34.296 0.173 34.416 ;
     RECT  0.084 34.416 0.173 34.44 ;
     RECT  0.06 34.44 0.173 34.56 ;
     RECT  0.084 34.56 0.173 34.584 ;
     RECT  0.06 34.584 0.173 34.704 ;
     RECT  0.084 34.704 0.173 34.728 ;
     RECT  0.06 34.728 0.173 34.848 ;
     RECT  0.084 34.848 0.173 34.872 ;
     RECT  0.06 34.872 0.173 34.992 ;
     RECT  0.084 34.992 0.173 35.016 ;
     RECT  0.06 35.016 0.173 35.136 ;
     RECT  0.084 35.136 0.173 35.16 ;
     RECT  0.06 35.16 0.173 35.28 ;
     RECT  0.084 35.28 0.173 35.304 ;
     RECT  0.06 35.304 0.173 35.424 ;
     RECT  0.084 35.424 0.173 35.448 ;
     RECT  0.06 35.448 0.173 35.568 ;
     RECT  0.084 35.568 0.173 35.592 ;
     RECT  0.06 35.592 0.173 35.712 ;
     RECT  0.084 35.712 0.173 35.736 ;
     RECT  0.06 35.736 0.173 35.856 ;
     RECT  0.084 35.856 0.173 35.88 ;
     RECT  0.06 35.88 0.173 36 ;
     RECT  0.084 36 0.173 36.024 ;
     RECT  0.06 36.024 0.173 36.144 ;
     RECT  0.084 36.144 0.173 36.168 ;
     RECT  0.06 36.168 0.173 36.288 ;
     RECT  0.084 36.288 0.173 36.312 ;
     RECT  0.06 36.312 0.173 36.432 ;
     RECT  0.084 36.432 0.173 36.456 ;
     RECT  0.06 36.456 0.173 36.576 ;
     RECT  0.084 36.576 0.173 36.6 ;
     RECT  0.06 36.6 0.173 37.296 ;
     RECT  0.084 37.296 0.173 37.32 ;
     RECT  0.06 37.32 0.173 37.44 ;
     RECT  0.084 37.44 0.173 37.464 ;
     RECT  0.06 37.464 0.173 37.584 ;
     RECT  0.084 37.584 0.173 37.608 ;
     RECT  0.06 37.608 0.173 37.728 ;
     RECT  0.084 37.728 0.173 37.752 ;
     RECT  0.06 37.752 0.173 37.872 ;
     RECT  0.084 37.872 0.173 37.896 ;
     RECT  0.06 37.896 0.173 38.016 ;
     RECT  0.084 38.016 0.173 38.04 ;
     RECT  0.06 38.04 0.173 38.16 ;
     RECT  0.084 38.16 0.173 38.184 ;
     RECT  0.06 38.184 0.173 38.304 ;
     RECT  0.084 38.304 0.173 38.328 ;
     RECT  0.06 38.328 0.173 38.448 ;
     RECT  0.084 38.448 0.173 38.472 ;
     RECT  0.06 38.472 0.173 38.592 ;
     RECT  0.084 38.592 0.173 38.616 ;
     RECT  0.06 38.616 0.173 38.736 ;
     RECT  0.084 38.736 0.173 38.76 ;
     RECT  0.06 38.76 0.173 38.88 ;
     RECT  0.084 38.88 0.173 38.904 ;
     RECT  0.06 38.904 0.173 39.024 ;
     RECT  0.084 39.024 0.173 39.048 ;
     RECT  0.06 39.048 0.173 39.168 ;
     RECT  0.084 39.168 0.173 39.192 ;
     RECT  0.06 39.192 0.173 39.312 ;
     RECT  0.084 39.312 0.173 39.336 ;
     RECT  0.06 39.336 0.173 39.456 ;
     RECT  0.084 39.456 0.173 39.48 ;
     RECT  0.06 39.48 0.173 39.6 ;
     RECT  0.084 39.6 0.173 39.624 ;
     RECT  0.06 39.624 0.173 39.744 ;
     RECT  0.084 39.744 0.173 39.768 ;
     RECT  0.06 39.768 0.173 39.888 ;
     RECT  0.084 39.888 0.173 39.912 ;
     RECT  0.06 39.912 0.173 40.032 ;
     RECT  0.084 40.032 0.173 40.056 ;
     RECT  0.06 40.056 0.173 40.176 ;
     RECT  0.084 40.176 0.173 40.2 ;
     RECT  0.06 40.2 0.173 40.32 ;
     RECT  0.084 40.32 0.173 40.344 ;
     RECT  0.06 40.344 0.173 40.464 ;
     RECT  0.084 40.464 0.173 40.488 ;
     RECT  0.06 40.488 0.173 40.608 ;
     RECT  0.084 40.608 0.173 40.632 ;
     RECT  0.06 40.632 0.173 40.752 ;
     RECT  0.084 40.752 0.173 40.776 ;
     RECT  0.06 40.776 0.173 40.896 ;
     RECT  0.084 40.896 0.173 40.92 ;
     RECT  0.06 40.92 0.173 41.04 ;
     RECT  0.084 41.04 0.173 41.064 ;
     RECT  0.06 41.064 0.173 41.184 ;
     RECT  0.084 41.184 0.173 41.208 ;
     RECT  0.06 41.208 0.173 41.328 ;
     RECT  0.084 41.328 0.173 41.352 ;
     RECT  0.06 41.352 0.173 41.472 ;
     RECT  0.084 41.472 0.173 41.496 ;
     RECT  0.06 41.496 0.173 41.616 ;
     RECT  0.084 41.616 0.173 41.64 ;
     RECT  0.06 41.64 0.173 41.76 ;
     RECT  0.084 41.76 0.173 41.784 ;
     RECT  0.06 41.784 0.173 41.904 ;
     RECT  0.084 41.904 0.173 41.928 ;
     RECT  0.06 41.928 0.173 42.048 ;
     RECT  0.084 42.048 0.173 42.072 ;
     RECT  0.06 42.072 0.173 42.192 ;
     RECT  0.084 42.192 0.173 42.216 ;
     RECT  0.06 42.216 0.173 42.336 ;
     RECT  0.084 42.336 0.173 42.36 ;
     RECT  0.06 42.36 0.173 42.48 ;
     RECT  0.084 42.48 0.173 42.504 ;
     RECT  0.06 42.504 0.173 42.624 ;
     RECT  0.084 42.624 0.173 42.648 ;
     RECT  0.06 42.648 0.173 42.768 ;
     RECT  0.084 42.768 0.173 42.792 ;
     RECT  0.06 42.792 0.173 42.912 ;
     RECT  0.084 42.912 0.173 42.936 ;
     RECT  0.06 42.936 0.173 43.056 ;
     RECT  0.084 43.056 0.173 43.08 ;
     RECT  0.06 43.08 0.173 43.2 ;
     RECT  0.084 43.2 0.173 43.224 ;
     RECT  0.06 43.224 0.173 43.344 ;
     RECT  0.084 43.344 0.173 43.368 ;
     RECT  0.06 43.368 0.173 43.488 ;
     RECT  0.084 43.488 0.173 43.512 ;
     RECT  0.06 43.512 0.173 43.632 ;
     RECT  0.084 43.632 0.173 43.656 ;
     RECT  0.06 43.656 0.173 43.776 ;
     RECT  0.084 43.776 0.173 43.8 ;
     RECT  0.06 43.8 0.173 43.92 ;
     RECT  0.084 43.92 0.173 43.944 ;
     RECT  0.06 43.944 0.173 44.064 ;
     RECT  0.084 44.064 0.173 44.088 ;
     RECT  0.06 44.088 0.173 44.208 ;
     RECT  0.084 44.208 0.173 44.232 ;
     RECT  0.06 44.232 0.173 44.352 ;
     RECT  0.084 44.352 0.173 44.376 ;
     RECT  0.06 44.376 0.173 44.496 ;
     RECT  0.084 44.496 0.173 44.52 ;
     RECT  0.06 44.52 0.173 44.64 ;
     RECT  0.084 44.64 0.173 44.664 ;
     RECT  0.06 44.664 0.173 44.784 ;
     RECT  0.084 44.784 0.173 44.808 ;
     RECT  0.06 44.808 0.173 44.928 ;
     RECT  0.084 44.928 0.173 44.952 ;
     RECT  0.06 44.952 0.173 45.072 ;
     RECT  0.084 45.072 0.173 45.096 ;
     RECT  0.06 45.096 0.173 45.216 ;
     RECT  0.084 45.216 0.173 45.24 ;
     RECT  0.06 45.24 0.173 45.36 ;
     RECT  0.084 45.36 0.173 45.384 ;
     RECT  0.06 45.384 0.173 45.504 ;
     RECT  0.084 45.504 0.173 45.528 ;
     RECT  0.06 45.528 0.173 45.648 ;
     RECT  0.084 45.648 0.173 45.672 ;
     RECT  0.06 45.672 0.173 45.792 ;
     RECT  0.084 45.792 0.173 45.816 ;
     RECT  0.06 45.816 0.173 45.936 ;
     RECT  0.084 45.936 0.173 45.96 ;
     RECT  0.06 45.96 0.173 46.08 ;
     RECT  0.084 46.08 0.173 46.104 ;
     RECT  0.06 46.104 0.173 46.224 ;
     RECT  0.084 46.224 0.173 46.248 ;
     RECT  0.06 46.248 0.173 46.368 ;
     RECT  0.084 46.368 0.173 46.392 ;
     RECT  0.06 46.392 0.173 46.512 ;
     RECT  0.084 46.512 0.173 46.536 ;
     RECT  0.06 46.536 0.173 46.656 ;
     RECT  0.084 46.656 0.173 46.68 ;
     RECT  0.06 46.68 0.173 46.8 ;
     RECT  0.084 46.8 0.173 46.824 ;
     RECT  0.06 46.824 0.173 46.944 ;
     RECT  0.084 46.944 0.173 46.968 ;
     RECT  0.06 46.968 0.173 47.088 ;
     RECT  0.084 47.088 0.173 47.112 ;
     RECT  0.06 47.112 0.173 47.232 ;
     RECT  0.084 47.232 0.173 47.256 ;
     RECT  0.06 47.256 0.173 47.376 ;
     RECT  0.084 47.376 0.173 47.4 ;
     RECT  0.06 47.4 0.173 47.52 ;
     RECT  0.084 47.52 0.173 47.544 ;
     RECT  0.06 47.544 0.173 47.664 ;
     RECT  0.084 47.664 0.173 47.688 ;
     RECT  0.06 47.688 0.173 47.808 ;
     RECT  0.084 47.808 0.173 47.832 ;
     RECT  0.06 47.832 0.173 47.952 ;
     RECT  0.084 47.952 0.173 47.976 ;
     RECT  0.06 47.976 0.173 48.096 ;
     RECT  0.084 48.096 0.173 48.12 ;
     RECT  0.06 48.12 0.173 48.24 ;
     RECT  0.084 48.24 0.173 48.264 ;
     RECT  0.06 48.264 0.173 48.384 ;
     RECT  0.084 48.384 0.173 48.408 ;
     RECT  0.06 48.408 0.173 48.528 ;
     RECT  0.084 48.528 0.173 48.552 ;
     RECT  0.06 48.552 0.173 48.672 ;
     RECT  0.084 48.672 0.173 48.696 ;
     RECT  0.06 48.696 0.173 48.816 ;
     RECT  0.084 48.816 0.173 48.84 ;
     RECT  0.06 48.84 0.173 48.96 ;
     RECT  0.084 48.96 0.173 48.984 ;
     RECT  0.06 48.984 0.173 49.104 ;
     RECT  0.084 49.104 0.173 49.128 ;
     RECT  0.06 49.128 0.173 49.248 ;
     RECT  0.084 49.248 0.173 49.272 ;
     RECT  0.06 49.272 0.173 49.392 ;
     RECT  0.084 49.392 0.173 49.416 ;
     RECT  0.06 49.416 0.173 49.536 ;
     RECT  0.084 49.536 0.173 49.56 ;
     RECT  0.06 49.56 0.173 49.68 ;
     RECT  0.084 49.68 0.173 49.704 ;
     RECT  0.06 49.704 0.173 49.824 ;
     RECT  0.084 49.824 0.173 49.848 ;
     RECT  0.06 49.848 0.173 49.968 ;
     RECT  0.084 49.968 0.173 49.992 ;
     RECT  0.06 49.992 0.173 50.112 ;
     RECT  0.084 50.112 0.173 50.136 ;
     RECT  0.06 50.136 0.173 50.256 ;
     RECT  0.084 50.256 0.173 50.28 ;
     RECT  0.06 50.28 0.173 50.4 ;
     RECT  0.084 50.4 0.173 50.424 ;
     RECT  0.06 50.424 0.173 50.544 ;
     RECT  0.084 50.544 0.173 50.568 ;
     RECT  0.06 50.568 0.173 50.688 ;
     RECT  0.084 50.688 0.173 50.712 ;
     RECT  0.06 50.712 0.173 50.832 ;
     RECT  0.084 50.832 0.173 50.856 ;
     RECT  0.06 50.856 0.173 50.976 ;
     RECT  0.084 50.976 0.173 51 ;
     RECT  0.06 51 0.173 51.12 ;
     RECT  0.084 51.12 0.173 51.144 ;
     RECT  0.06 51.144 0.173 51.264 ;
     RECT  0.084 51.264 0.173 51.288 ;
     RECT  0.06 51.288 0.173 51.408 ;
     RECT  0.084 51.408 0.173 51.432 ;
     RECT  0.06 51.432 0.173 51.552 ;
     RECT  0.084 51.552 0.173 51.576 ;
     RECT  0.06 51.576 0.173 51.696 ;
     RECT  0.084 51.696 0.173 51.72 ;
     RECT  0.06 51.72 0.173 51.84 ;
     RECT  0.084 51.84 0.173 51.864 ;
     RECT  0.06 51.864 0.173 51.984 ;
     RECT  0.084 51.984 0.173 52.008 ;
     RECT  0.06 52.008 0.173 52.128 ;
     RECT  0.084 52.128 0.173 52.152 ;
     RECT  0.06 52.152 0.173 52.272 ;
     RECT  0.084 52.272 0.173 52.296 ;
     RECT  0.06 52.296 0.173 52.416 ;
     RECT  0.084 52.416 0.173 52.44 ;
     RECT  0.06 52.44 0.173 52.56 ;
     RECT  0.084 52.56 0.173 52.584 ;
     RECT  0.06 52.584 0.173 52.704 ;
     RECT  0.084 52.704 0.173 52.728 ;
     RECT  0.06 52.728 0.173 52.848 ;
     RECT  0.084 52.848 0.173 52.872 ;
     RECT  0.06 52.872 0.173 52.992 ;
     RECT  0.084 52.992 0.173 53.016 ;
     RECT  0.06 53.016 0.173 53.136 ;
     RECT  0.084 53.136 0.173 53.16 ;
     RECT  0.06 53.16 0.173 53.28 ;
     RECT  0.084 53.28 0.173 53.304 ;
     RECT  0.06 53.304 0.173 53.424 ;
     RECT  0.084 53.424 0.173 53.448 ;
     RECT  0.06 53.448 0.173 53.568 ;
     RECT  0.084 53.568 0.173 53.592 ;
     RECT  0.06 53.592 0.173 53.712 ;
     RECT  0.084 53.712 0.173 53.736 ;
     RECT  0.06 53.736 0.173 53.856 ;
     RECT  0.084 53.856 0.173 53.88 ;
     RECT  0.06 53.88 0.173 54 ;
     RECT  0.084 54 0.173 54.024 ;
     RECT  0.06 54.024 0.173 54.144 ;
     RECT  0.084 54.144 0.173 54.168 ;
     RECT  0.06 54.168 0.173 54.288 ;
     RECT  0.084 54.288 0.173 54.312 ;
     RECT  0.06 54.312 0.173 54.432 ;
     RECT  0.084 54.432 0.173 54.456 ;
     RECT  0.06 54.456 0.173 54.576 ;
     RECT  0.084 54.576 0.173 54.6 ;
     RECT  0.06 54.6 0.173 54.72 ;
     RECT  0.084 54.72 0.173 54.744 ;
     RECT  0.06 54.744 0.173 54.864 ;
     RECT  0.084 54.864 0.173 54.888 ;
     RECT  0.06 54.888 0.173 55.008 ;
     RECT  0.084 55.008 0.173 55.032 ;
     RECT  0.06 55.032 0.173 55.152 ;
     RECT  0.084 55.152 0.173 55.176 ;
     RECT  0.06 55.176 0.173 55.296 ;
     RECT  0.084 55.296 0.173 55.32 ;
     RECT  0.06 55.32 0.173 55.44 ;
     RECT  0.084 55.44 0.173 55.464 ;
     RECT  0.06 55.464 0.173 55.584 ;
     RECT  0.084 55.584 0.173 55.608 ;
     RECT  0.06 55.608 0.173 55.728 ;
     RECT  0.084 55.728 0.173 55.752 ;
     RECT  0.06 55.752 0.173 55.872 ;
     RECT  0.084 55.872 0.173 55.896 ;
     RECT  0.06 55.896 0.173 56.016 ;
     RECT  0.084 56.016 0.173 56.04 ;
     RECT  0.06 56.04 0.173 56.16 ;
     RECT  0.084 56.16 0.173 56.184 ;
     RECT  0.06 56.184 0.173 56.304 ;
     RECT  0.084 56.304 0.173 56.328 ;
     RECT  0.06 56.328 0.173 56.448 ;
     RECT  0.084 56.448 0.173 56.472 ;
     RECT  0.06 56.472 0.173 56.592 ;
     RECT  0.084 56.592 0.173 56.616 ;
     RECT  0.06 56.616 0.173 56.736 ;
     RECT  0.084 56.736 0.173 56.76 ;
     RECT  0.06 56.76 0.173 56.88 ;
     RECT  0.084 56.88 0.173 56.904 ;
     RECT  0.06 56.904 0.173 57.024 ;
     RECT  0.084 57.024 0.173 57.048 ;
     RECT  0.06 57.048 0.173 57.168 ;
     RECT  0.084 57.168 0.173 57.192 ;
     RECT  0.06 57.192 0.173 57.312 ;
     RECT  0.084 57.312 0.173 57.336 ;
     RECT  0.06 57.336 0.173 57.456 ;
     RECT  0.084 57.456 0.173 57.48 ;
     RECT  0.06 57.48 0.173 57.6 ;
     RECT  0.084 57.6 0.173 57.624 ;
     RECT  0.06 57.624 0.173 57.744 ;
     RECT  0.084 57.744 0.173 57.768 ;
     RECT  0.06 57.768 0.173 57.888 ;
     RECT  0.084 57.888 0.173 57.912 ;
     RECT  0.06 57.912 0.173 58.032 ;
     RECT  0.084 58.032 0.173 58.056 ;
     RECT  0.06 58.056 0.173 58.176 ;
     RECT  0.084 58.176 0.173 58.2 ;
     RECT  0.06 58.2 0.173 58.32 ;
     RECT  0.084 58.32 0.173 58.344 ;
     RECT  0.06 58.344 0.173 58.464 ;
     RECT  0.084 58.464 0.173 58.488 ;
     RECT  0.06 58.488 0.173 58.608 ;
     RECT  0.084 58.608 0.173 58.632 ;
     RECT  0.06 58.632 0.173 58.752 ;
     RECT  0.084 58.752 0.173 58.776 ;
     RECT  0.06 58.776 0.173 58.896 ;
     RECT  0.084 58.896 0.173 58.92 ;
     RECT  0.06 58.92 0.173 59.04 ;
     RECT  0.084 59.04 0.173 59.064 ;
     RECT  0.06 59.064 0.173 59.184 ;
     RECT  0.084 59.184 0.173 59.208 ;
     RECT  0.06 59.208 0.173 59.328 ;
     RECT  0.084 59.328 0.173 59.352 ;
     RECT  0.06 59.352 0.173 59.472 ;
     RECT  0.084 59.472 0.173 59.496 ;
     RECT  0.06 59.496 0.173 59.616 ;
     RECT  0.084 59.616 0.173 59.64 ;
     RECT  0.06 59.64 0.173 59.76 ;
     RECT  0.084 59.76 0.173 59.784 ;
     RECT  0.06 59.784 0.173 59.904 ;
     RECT  0.084 59.904 0.173 59.928 ;
     RECT  0.06 59.928 0.173 60.048 ;
     RECT  0.084 60.048 0.173 60.072 ;
     RECT  0.06 60.072 0.173 60.192 ;
     RECT  0.084 60.192 0.173 60.216 ;
     RECT  0.06 60.216 0.173 60.336 ;
     RECT  0.084 60.336 0.173 60.36 ;
     RECT  0.06 60.36 0.173 60.48 ;
     RECT  0.084 60.48 0.173 60.504 ;
     RECT  0.06 60.504 0.173 60.624 ;
     RECT  0.084 60.624 0.173 60.648 ;
     RECT  0.06 60.648 0.173 60.768 ;
     RECT  0.084 60.768 0.173 60.792 ;
     RECT  0.06 60.792 0.173 60.912 ;
     RECT  0.084 60.912 0.173 60.936 ;
     RECT  0.06 60.936 0.173 61.056 ;
     RECT  0.084 61.056 0.173 61.08 ;
     RECT  0.06 61.08 0.173 61.2 ;
     RECT  0.084 61.2 0.173 61.224 ;
     RECT  0.06 61.224 0.173 61.344 ;
     RECT  0.084 61.344 0.173 61.368 ;
     RECT  0.06 61.368 0.173 61.488 ;
     RECT  0.084 61.488 0.173 61.512 ;
     RECT  0.06 61.512 0.173 61.632 ;
     RECT  0.084 61.632 0.173 61.656 ;
     RECT  0.06 61.656 0.173 61.776 ;
     RECT  0.084 61.776 0.173 61.8 ;
     RECT  0.06 61.8 0.173 61.92 ;
     RECT  0.084 61.92 0.173 61.944 ;
     RECT  0.06 61.944 0.173 62.064 ;
     RECT  0.084 62.064 0.173 62.088 ;
     RECT  0.06 62.088 0.173 62.208 ;
     RECT  0.084 62.208 0.173 62.232 ;
     RECT  0.06 62.232 0.173 62.352 ;
     RECT  0.084 62.352 0.173 62.376 ;
     RECT  0.06 62.376 0.173 62.496 ;
     RECT  0.084 62.496 0.173 62.52 ;
     RECT  0.06 62.52 0.173 62.64 ;
     RECT  0.084 62.64 0.173 62.664 ;
     RECT  0.06 62.664 0.173 62.784 ;
     RECT  0.084 62.784 0.173 62.808 ;
     RECT  0.06 62.808 0.173 62.928 ;
     RECT  0.084 62.928 0.173 62.952 ;
     RECT  0.06 62.952 0.173 63.072 ;
     RECT  0.084 63.072 0.173 63.096 ;
     RECT  0.06 63.096 0.173 63.216 ;
     RECT  0.084 63.216 0.173 63.24 ;
     RECT  0.06 63.24 0.173 63.36 ;
     RECT  0.084 63.36 0.173 63.384 ;
     RECT  0.06 63.384 0.173 63.504 ;
     RECT  0.084 63.504 0.173 63.528 ;
     RECT  0.06 63.528 0.173 63.648 ;
     RECT  0.084 63.648 0.173 63.672 ;
     RECT  0.06 63.672 0.173 63.792 ;
     RECT  0.084 63.792 0.173 63.816 ;
     RECT  0.06 63.816 0.173 63.936 ;
     RECT  0.084 63.936 0.173 63.96 ;
     RECT  0.06 63.96 0.173 64.08 ;
     RECT  0.084 64.08 0.173 64.104 ;
     RECT  0.06 64.104 0.173 64.224 ;
     RECT  0.084 64.224 0.173 64.248 ;
     RECT  0.06 64.248 0.173 64.368 ;
     RECT  0.084 64.368 0.173 64.392 ;
     RECT  0.06 64.392 0.173 64.512 ;
     RECT  0.084 64.512 0.173 64.536 ;
     RECT  0.06 64.536 0.173 64.656 ;
     RECT  0.084 64.656 0.173 64.68 ;
     RECT  0.06 64.68 0.173 64.8 ;
     RECT  0.084 64.8 0.173 64.824 ;
     RECT  0.06 64.824 0.173 64.944 ;
     RECT  0.084 64.944 0.173 64.968 ;
     RECT  0.06 64.968 0.173 65.088 ;
     RECT  0.084 65.088 0.173 65.112 ;
     RECT  0.06 65.112 0.173 65.232 ;
     RECT  0.084 65.232 0.173 65.256 ;
     RECT  0.06 65.256 0.173 65.376 ;
     RECT  0.084 65.376 0.173 65.4 ;
     RECT  0.173 9.216 0.181 65.4 ;
     RECT  0.137 66.576 0.181 84.84 ;
     RECT  0.181 9.216 0.209 84.84 ;
     RECT  0.209 9.216 0.281 84.696 ;
     RECT  0.281 9.216 0.389 84.408 ;
     RECT  0.389 79.632 0.461 84.408 ;
     RECT  0.461 79.776 0.533 84.408 ;
     RECT  0.533 80.064 0.569 84.408 ;
     RECT  0.569 80.112 0.857 84.408 ;
     RECT  0.389 9.216 1.181 78.648 ;
     RECT  1.181 9.216 2.408 78.504 ;
     RECT  0.857 80.112 2.408 84.12 ;
     RECT  2.408 2.148 2.512 92.892 ;
     RECT  2.512 2.418 2.704 92.622 ;
     RECT  2.704 60.576 2.729 73.896 ;
     RECT  2.704 32.352 2.765 35.304 ;
     RECT  2.704 52.992 2.765 54.168 ;
     RECT  2.704 55.248 2.819 59.208 ;
     RECT  2.729 73.392 2.837 73.896 ;
     RECT  2.704 76.32 2.837 78.504 ;
     RECT  2.704 80.112 2.837 80.376 ;
     RECT  2.704 12.816 2.873 23.928 ;
     RECT  2.729 60.576 2.873 72.408 ;
     RECT  2.837 76.512 2.873 78.504 ;
     RECT  2.765 32.352 2.909 35.256 ;
     RECT  2.873 66.768 2.917 72.408 ;
     RECT  2.704 36.768 2.945 51.576 ;
     RECT  2.917 70.56 2.945 72.408 ;
     RECT  2.819 57.6 3.017 59.208 ;
     RECT  2.873 12.816 3.053 23.544 ;
     RECT  2.945 36.768 3.089 51.432 ;
     RECT  3.017 58.512 3.089 59.208 ;
     RECT  2.873 76.752 3.089 78.504 ;
     RECT  3.053 12.816 3.155 14.952 ;
     RECT  3.053 16.272 3.161 23.544 ;
     RECT  2.704 25.104 3.233 30.984 ;
     RECT  3.089 36.768 3.269 49.56 ;
     RECT  3.089 76.752 3.277 78.216 ;
     RECT  3.155 12.816 3.305 13.656 ;
     RECT  2.917 66.768 3.305 69.576 ;
     RECT  2.873 60.576 3.341 65.688 ;
     RECT  3.155 14.928 3.377 14.952 ;
     RECT  3.089 58.512 3.377 58.536 ;
     RECT  3.233 25.104 3.395 30.504 ;
     RECT  3.395 28.464 3.413 30.504 ;
     RECT  3.277 76.752 3.413 76.776 ;
     RECT  3.277 77.904 3.413 78.216 ;
     RECT  3.341 60.576 3.421 65.592 ;
     RECT  2.819 55.488 3.449 56.376 ;
     RECT  3.305 13.632 3.493 13.656 ;
     RECT  3.269 36.768 3.521 49.512 ;
     RECT  2.765 53.904 3.521 53.928 ;
     RECT  3.421 61.104 3.521 65.592 ;
     RECT  3.305 69.504 3.521 69.576 ;
     RECT  2.945 70.56 3.521 72.024 ;
     RECT  2.909 32.352 3.539 34.632 ;
     RECT  3.395 25.104 3.557 27.192 ;
     RECT  3.305 66.768 3.557 68.52 ;
     RECT  3.413 28.464 3.593 30.408 ;
     RECT  3.539 32.352 3.629 34.152 ;
     RECT  3.521 36.768 3.629 47.88 ;
     RECT  3.593 28.512 3.665 30.408 ;
     RECT  3.521 69.552 3.665 69.576 ;
     RECT  3.521 62.688 3.673 65.592 ;
     RECT  3.629 39.264 3.737 47.88 ;
     RECT  3.673 63.072 3.737 65.592 ;
     RECT  3.521 71.376 3.773 72.024 ;
     RECT  3.413 77.904 3.773 77.928 ;
     RECT  2.837 80.112 3.773 80.136 ;
     RECT  3.629 36.768 3.809 37.848 ;
     RECT  3.521 61.104 3.809 61.608 ;
     RECT  3.161 16.272 3.845 22.392 ;
     RECT  3.773 71.376 3.845 71.448 ;
     RECT  3.845 16.272 3.881 22.296 ;
     RECT  3.809 36.768 3.881 36.936 ;
     RECT  3.737 63.072 3.881 64.392 ;
     RECT  3.881 36.768 3.917 36.792 ;
     RECT  3.161 23.52 3.923 23.544 ;
     RECT  3.845 71.376 3.989 71.4 ;
     RECT  3.629 32.544 4.025 34.152 ;
     RECT  3.737 39.264 4.025 47.352 ;
     RECT  3.881 63.072 4.025 64.152 ;
     RECT  3.737 65.568 4.061 65.592 ;
     RECT  3.881 17.712 4.097 22.296 ;
     RECT  3.557 66.768 4.453 68.232 ;
     RECT  3.809 61.104 4.525 61.176 ;
     RECT  4.489 75.936 4.525 75.96 ;
     RECT  3.733 60 4.669 60.024 ;
     RECT  3.089 50.544 4.777 51.432 ;
     RECT  4.669 59.52 4.885 60.024 ;
     RECT  4.885 59.184 4.957 60.024 ;
     RECT  4.525 61.056 4.957 61.176 ;
     RECT  4.025 63.072 5.101 63.72 ;
     RECT  2.704 10.08 5.108 11.544 ;
     RECT  3.881 16.272 5.108 16.584 ;
     RECT  4.097 17.712 5.108 18.696 ;
     RECT  4.097 19.92 5.108 22.296 ;
     RECT  4.213 23.568 5.108 23.592 ;
     RECT  3.557 25.2 5.108 27.192 ;
     RECT  3.665 28.512 5.108 29.784 ;
     RECT  4.025 32.784 5.108 34.152 ;
     RECT  4.025 39.264 5.108 41.688 ;
     RECT  4.025 42.864 5.108 47.352 ;
     RECT  3.521 48.912 5.108 49.512 ;
     RECT  4.777 50.544 5.108 51.48 ;
     RECT  3.913 52.464 5.108 52.488 ;
     RECT  3.449 55.488 5.108 55.512 ;
     RECT  4.129 57.072 5.108 57.096 ;
     RECT  4.957 59.184 5.108 61.176 ;
     RECT  5.101 62.544 5.108 63.72 ;
     RECT  4.453 66.72 5.108 68.232 ;
     RECT  2.837 73.392 5.108 73.512 ;
     RECT  4.525 75.408 5.108 75.96 ;
     RECT  2.704 81.648 5.108 82.536 ;
     RECT  5.108 2.148 5.212 92.892 ;
     RECT  5.212 2.418 5.404 92.622 ;
     RECT  5.404 58.224 5.717 63.48 ;
     RECT  5.404 68.208 5.789 68.232 ;
     RECT  5.404 16.56 5.861 16.584 ;
     RECT  5.404 55.392 5.939 57.24 ;
     RECT  5.404 75.408 5.939 75.96 ;
     RECT  5.404 51.12 6.179 51.528 ;
     RECT  5.404 66.768 6.179 66.792 ;
     RECT  5.717 58.224 6.329 63.384 ;
     RECT  5.939 55.392 6.371 56.856 ;
     RECT  5.404 72.912 6.371 72.936 ;
     RECT  6.397 66.624 6.509 66.648 ;
     RECT  6.329 58.416 6.515 63.384 ;
     RECT  5.939 75.936 6.515 75.96 ;
     RECT  6.515 58.704 6.761 63.384 ;
     RECT  5.404 49.488 6.829 49.512 ;
     RECT  5.404 23.568 7.808 23.592 ;
     RECT  5.404 25.2 7.808 26.088 ;
     RECT  6.829 49.488 7.808 49.656 ;
     RECT  6.179 51.12 7.808 51.48 ;
     RECT  6.371 55.392 7.808 55.512 ;
     RECT  6.371 56.592 7.808 56.856 ;
     RECT  6.761 58.704 7.808 62.664 ;
     RECT  7.808 2.148 7.912 92.892 ;
     RECT  7.912 2.418 8.104 92.622 ;
     RECT  8.104 58.656 8.201 60.072 ;
     RECT  8.104 51.12 8.309 51.72 ;
     RECT  8.309 51.12 8.633 51.48 ;
     RECT  8.104 23.568 8.741 23.736 ;
     RECT  8.104 25.2 9.109 25.656 ;
     RECT  8.633 51.456 9.281 51.48 ;
     RECT  9.169 36.816 9.389 36.84 ;
     RECT  9.673 33.264 9.781 33.288 ;
     RECT  9.997 34.8 10.069 34.824 ;
     RECT  8.741 23.712 10.508 23.736 ;
     RECT  9.74 24.816 10.508 24.84 ;
     RECT  8.104 29.328 10.508 29.352 ;
     RECT  8.104 31.632 10.508 31.656 ;
     RECT  9.781 33.264 10.508 33.528 ;
     RECT  10.069 34.8 10.508 35.736 ;
     RECT  9.817 41.424 10.508 41.448 ;
     RECT  8.104 49.488 10.508 49.512 ;
     RECT  10.177 52.032 10.508 52.056 ;
     RECT  8.104 55.488 10.508 55.512 ;
     RECT  8.201 59.184 10.508 60.072 ;
     RECT  8.104 61.152 10.508 61.176 ;
     RECT  10.285 66.768 10.508 66.792 ;
     RECT  10.508 2.148 10.612 92.892 ;
     RECT  10.612 2.418 10.804 92.622 ;
     RECT  10.804 35.472 11.333 35.496 ;
     RECT  10.804 32.304 11.441 32.328 ;
     RECT  10.804 58.752 11.441 63.24 ;
     RECT  11.441 58.752 11.549 61.992 ;
     RECT  11.549 61.584 11.621 61.992 ;
     RECT  10.804 65.424 11.657 65.448 ;
     RECT  10.804 48.528 11.797 52.296 ;
     RECT  10.804 57.648 11.797 57.768 ;
     RECT  10.804 54.624 11.852 55.512 ;
     RECT  11.852 54.336 11.877 55.512 ;
     RECT  11.797 57.36 11.893 57.768 ;
     RECT  11.549 58.752 11.893 60.408 ;
     RECT  11.869 43.392 11.905 43.416 ;
     RECT  11.797 47.904 11.905 52.296 ;
     RECT  11.877 53.76 11.905 55.512 ;
     RECT  10.804 41.424 11.939 42.168 ;
     RECT  10.804 66.768 12.013 66.792 ;
     RECT  11.939 41.424 12.017 41.688 ;
     RECT  12.013 66.768 12.121 66.888 ;
     RECT  12.017 41.664 12.125 41.688 ;
     RECT  11.905 47.904 12.133 55.512 ;
     RECT  11.893 44.592 12.337 44.616 ;
     RECT  12.133 47.904 12.373 55.896 ;
     RECT  11.893 57.168 12.373 60.408 ;
     RECT  10.804 29.328 12.409 29.352 ;
     RECT  12.337 32.208 12.409 32.232 ;
     RECT  12.121 35.28 12.409 35.304 ;
     RECT  12.121 66.768 12.409 67.32 ;
     RECT  11.905 43.296 12.445 43.416 ;
     RECT  12.337 44.592 12.445 44.664 ;
     RECT  12.445 43.296 12.509 44.664 ;
     RECT  12.373 47.904 12.517 60.408 ;
     RECT  11.621 61.584 12.517 61.704 ;
     RECT  12.121 64.368 12.517 64.392 ;
     RECT  12.409 66.768 12.517 67.608 ;
     RECT  12.409 35.28 12.661 35.88 ;
     RECT  12.284 37.008 12.661 37.032 ;
     RECT  12.517 64.368 12.913 65.304 ;
     RECT  12.517 66.72 12.913 67.608 ;
     RECT  12.517 47.904 13.057 61.704 ;
     RECT  12.949 63.216 13.057 63.24 ;
     RECT  13.021 41.376 13.093 41.4 ;
     RECT  12.509 42.72 13.093 44.664 ;
     RECT  12.409 29.328 13.208 29.496 ;
     RECT  12.409 32.208 13.208 33.096 ;
     RECT  12.445 34.176 13.208 34.2 ;
     RECT  12.661 35.28 13.208 37.032 ;
     RECT  12.325 38.64 13.208 39.48 ;
     RECT  13.093 40.56 13.208 44.664 ;
     RECT  11.797 46.128 13.208 46.152 ;
     RECT  13.057 47.904 13.208 63.24 ;
     RECT  12.913 64.368 13.208 67.608 ;
     RECT  13.208 2.148 13.312 92.892 ;
     RECT  13.312 2.418 13.504 92.622 ;
     RECT  13.504 29.328 13.673 29.352 ;
     RECT  13.504 40.56 13.715 41.256 ;
     RECT  13.504 36.576 13.781 39.384 ;
     RECT  13.504 67.584 13.853 67.608 ;
     RECT  13.504 42.288 13.889 42.312 ;
     RECT  13.781 36.816 14.051 39.384 ;
     RECT  13.504 43.296 14.051 44.088 ;
     RECT  13.504 55.872 14.051 55.896 ;
     RECT  14.06 0.528 14.147 0.552 ;
     RECT  13.504 45.552 14.243 51.384 ;
     RECT  13.504 52.416 14.243 53.208 ;
     RECT  13.504 64.368 14.285 65.544 ;
     RECT  13.504 33.024 14.291 34.344 ;
     RECT  14.243 46.176 14.321 51.384 ;
     RECT  13.504 59.472 14.339 63.288 ;
     RECT  14.285 65.52 14.573 65.544 ;
     RECT  14.321 46.176 14.579 47.352 ;
     RECT  14.321 48.624 14.579 51.384 ;
     RECT  13.504 54.72 14.605 54.744 ;
     RECT  14.339 59.472 14.605 62.472 ;
     RECT  14.285 64.368 14.609 64.392 ;
     RECT  14.605 54.384 14.639 54.744 ;
     RECT  14.243 52.464 14.677 53.208 ;
     RECT  14.639 54.384 14.677 54.936 ;
     RECT  14.605 59.232 14.681 62.472 ;
     RECT  13.715 40.56 14.713 41.064 ;
     RECT  14.713 40.368 14.749 41.064 ;
     RECT  14.579 48.96 14.753 51.384 ;
     RECT  14.681 59.232 14.753 60.984 ;
     RECT  14.579 47.28 14.789 47.352 ;
     RECT  14.753 49.488 14.819 51.384 ;
     RECT  14.051 36.816 14.821 37.944 ;
     RECT  13.504 57.024 14.821 57.576 ;
     RECT  14.789 47.28 14.861 47.304 ;
     RECT  14.753 59.472 14.861 60.984 ;
     RECT  14.051 39.312 14.905 39.384 ;
     RECT  14.821 56.16 14.905 58.104 ;
     RECT  14.051 43.776 14.929 44.088 ;
     RECT  14.749 40.368 15.001 41.928 ;
     RECT  14.291 33.024 15.109 33.048 ;
     RECT  15.001 40.368 15.145 42.168 ;
     RECT  14.579 46.176 15.212 46.2 ;
     RECT  14.291 34.224 15.253 34.344 ;
     RECT  14.569 35.424 15.253 35.448 ;
     RECT  14.821 36.528 15.301 37.944 ;
     RECT  13.504 31.872 15.325 31.896 ;
     RECT  15.109 32.976 15.325 33.048 ;
     RECT  14.681 62.448 15.325 62.472 ;
     RECT  15.145 63.504 15.325 63.528 ;
     RECT  14.677 52.464 15.356 54.936 ;
     RECT  15.325 31.872 15.397 33.048 ;
     RECT  15.253 34.224 15.397 35.448 ;
     RECT  15.356 52.464 15.5 55.464 ;
     RECT  15.301 36.528 15.649 38.184 ;
     RECT  15.145 39.888 15.793 42.168 ;
     RECT  15.397 31.872 15.908 35.448 ;
     RECT  15.649 36.528 15.908 38.76 ;
     RECT  15.793 39.888 15.908 42.6 ;
     RECT  14.929 43.776 15.908 44.472 ;
     RECT  15.212 45.552 15.908 46.2 ;
     RECT  14.819 49.488 15.908 49.512 ;
     RECT  14.819 50.784 15.908 50.808 ;
     RECT  15.5 52.416 15.908 55.464 ;
     RECT  14.905 56.448 15.908 58.104 ;
     RECT  14.861 59.472 15.908 60.6 ;
     RECT  15.325 62.448 15.908 63.528 ;
     RECT  15.308 64.56 15.908 64.584 ;
     RECT  14.929 66.096 15.908 66.12 ;
     RECT  15.908 2.148 16.012 92.892 ;
     RECT  16.012 2.418 16.204 92.622 ;
     RECT  16.204 46.224 16.409 48.792 ;
     RECT  16.409 46.224 16.553 48.696 ;
     RECT  16.204 62.544 16.553 62.568 ;
     RECT  16.204 50.256 16.697 50.28 ;
     RECT  16.204 38.688 17.093 41.064 ;
     RECT  16.204 36.816 17.233 36.84 ;
     RECT  16.204 42.576 17.269 44.376 ;
     RECT  16.204 52.272 17.305 52.296 ;
     RECT  16.204 53.28 17.305 55.704 ;
     RECT  17.305 52.272 17.489 55.704 ;
     RECT  17.629 50.4 17.665 50.424 ;
     RECT  16.553 46.608 17.917 48.696 ;
     RECT  17.917 46.608 18.025 49.272 ;
     RECT  17.093 38.688 18.205 40.92 ;
     RECT  18.025 45.984 18.241 49.272 ;
     RECT  17.665 50.304 18.241 50.424 ;
     RECT  17.233 36.816 18.313 37.08 ;
     RECT  18.205 38.448 18.313 40.92 ;
     RECT  18.241 34.848 18.421 34.872 ;
     RECT  17.377 31.968 18.608 31.992 ;
     RECT  18.421 34.848 18.608 35.544 ;
     RECT  18.313 36.816 18.608 40.92 ;
     RECT  17.269 42.144 18.608 44.376 ;
     RECT  18.241 45.984 18.608 50.424 ;
     RECT  17.489 52.272 18.608 54.744 ;
     RECT  17.521 58.08 18.608 58.104 ;
     RECT  17.665 62.496 18.608 62.52 ;
     RECT  18.608 2.148 18.712 92.892 ;
     RECT  18.712 2.418 18.904 92.622 ;
     RECT  18.904 29.52 18.929 40.92 ;
     RECT  18.904 54.624 18.965 57.336 ;
     RECT  18.929 29.52 19.897 35.784 ;
     RECT  18.904 43.2 19.897 47.4 ;
     RECT  18.904 49.104 19.897 51.144 ;
     RECT  18.904 52.416 19.897 53.304 ;
     RECT  18.904 58.608 19.897 67.272 ;
     RECT  18.929 37.152 19.933 40.92 ;
     RECT  18.904 41.904 19.933 41.928 ;
     RECT  18.965 54.864 19.933 57.336 ;
     RECT  19.897 43.2 20.401 53.448 ;
     RECT  19.933 54.576 20.401 57.336 ;
     RECT  19.897 29.52 20.437 36.168 ;
     RECT  19.933 37.152 20.437 41.928 ;
     RECT  20.401 42.912 20.437 53.448 ;
     RECT  20.401 54.432 20.437 57.336 ;
     RECT  19.897 58.464 20.437 67.272 ;
     RECT  20.437 58.464 20.509 67.416 ;
     RECT  20.437 29.52 21.516 29.544 ;
     RECT  20.437 29.544 21.564 29.664 ;
     RECT  20.437 29.664 21.516 29.688 ;
     RECT  20.437 29.688 21.564 29.808 ;
     RECT  20.437 29.808 21.516 29.832 ;
     RECT  20.437 29.832 21.564 29.952 ;
     RECT  20.437 29.952 21.516 29.976 ;
     RECT  20.437 29.976 21.564 30.096 ;
     RECT  20.437 30.096 21.516 30.12 ;
     RECT  20.437 30.12 21.564 30.24 ;
     RECT  20.437 30.24 21.516 30.264 ;
     RECT  20.437 30.264 21.564 30.384 ;
     RECT  20.437 30.384 21.516 30.408 ;
     RECT  20.437 30.408 21.564 30.528 ;
     RECT  20.437 30.528 21.516 30.552 ;
     RECT  20.437 30.552 21.564 30.672 ;
     RECT  20.437 30.672 21.516 30.696 ;
     RECT  20.437 30.696 21.564 30.816 ;
     RECT  20.437 30.816 21.516 30.84 ;
     RECT  20.437 30.84 21.564 30.96 ;
     RECT  20.437 30.96 21.516 30.984 ;
     RECT  20.437 30.984 21.564 31.104 ;
     RECT  20.437 31.104 21.516 31.128 ;
     RECT  20.437 31.128 21.564 31.248 ;
     RECT  20.437 31.248 21.516 31.272 ;
     RECT  20.437 31.272 21.564 31.392 ;
     RECT  20.437 31.392 21.516 31.416 ;
     RECT  20.437 31.416 21.564 31.536 ;
     RECT  20.437 31.536 21.516 31.56 ;
     RECT  20.437 31.56 21.564 31.68 ;
     RECT  20.437 31.68 21.516 31.704 ;
     RECT  20.437 31.704 21.564 31.824 ;
     RECT  20.437 31.824 21.516 31.848 ;
     RECT  20.437 31.848 21.564 31.968 ;
     RECT  20.437 31.968 21.516 31.992 ;
     RECT  20.437 31.992 21.564 32.112 ;
     RECT  20.437 32.112 21.516 32.136 ;
     RECT  20.437 32.136 21.564 32.256 ;
     RECT  20.437 32.256 21.516 32.28 ;
     RECT  20.437 32.28 21.564 32.4 ;
     RECT  20.437 32.4 21.516 32.424 ;
     RECT  20.437 32.424 21.564 32.544 ;
     RECT  20.437 32.544 21.516 32.568 ;
     RECT  20.437 32.568 21.564 32.688 ;
     RECT  20.437 32.688 21.516 32.712 ;
     RECT  20.437 32.712 21.564 32.832 ;
     RECT  20.437 32.832 21.516 32.856 ;
     RECT  20.437 32.856 21.564 32.976 ;
     RECT  20.437 32.976 21.516 33 ;
     RECT  20.437 33 21.564 33.12 ;
     RECT  20.437 33.12 21.516 33.144 ;
     RECT  20.437 33.144 21.564 33.264 ;
     RECT  20.437 33.264 21.516 33.288 ;
     RECT  20.437 33.288 21.564 33.408 ;
     RECT  20.437 33.408 21.516 33.432 ;
     RECT  20.437 33.432 21.564 33.552 ;
     RECT  20.437 33.552 21.516 33.576 ;
     RECT  20.437 33.576 21.564 33.696 ;
     RECT  20.437 33.696 21.516 33.72 ;
     RECT  20.437 33.72 21.564 33.84 ;
     RECT  20.437 33.84 21.516 33.864 ;
     RECT  20.437 33.864 21.564 33.984 ;
     RECT  20.437 33.984 21.516 34.008 ;
     RECT  20.437 34.008 21.564 34.128 ;
     RECT  20.437 34.128 21.516 34.152 ;
     RECT  20.437 34.152 21.564 34.272 ;
     RECT  20.437 34.272 21.516 34.296 ;
     RECT  20.437 34.296 21.564 34.416 ;
     RECT  20.437 34.416 21.516 34.44 ;
     RECT  20.437 34.44 21.564 34.56 ;
     RECT  20.437 34.56 21.516 34.584 ;
     RECT  20.437 34.584 21.564 34.704 ;
     RECT  20.437 34.704 21.516 34.728 ;
     RECT  20.437 34.728 21.564 34.848 ;
     RECT  20.437 34.848 21.516 34.872 ;
     RECT  20.437 34.872 21.564 34.992 ;
     RECT  20.437 34.992 21.516 35.016 ;
     RECT  20.437 35.016 21.564 35.136 ;
     RECT  20.437 35.136 21.516 35.16 ;
     RECT  20.437 35.16 21.564 35.28 ;
     RECT  20.437 35.28 21.516 35.304 ;
     RECT  20.437 35.304 21.564 35.424 ;
     RECT  20.437 35.424 21.516 35.448 ;
     RECT  20.437 35.448 21.564 35.568 ;
     RECT  20.437 35.568 21.516 35.592 ;
     RECT  20.437 35.592 21.564 35.712 ;
     RECT  20.437 35.712 21.516 35.736 ;
     RECT  20.437 35.736 21.564 35.856 ;
     RECT  20.437 35.856 21.516 35.88 ;
     RECT  20.437 35.88 21.564 36 ;
     RECT  20.437 36 21.516 36.024 ;
     RECT  20.437 36.024 21.564 36.144 ;
     RECT  20.437 36.144 21.516 36.168 ;
     RECT  20.437 36.168 21.564 36.288 ;
     RECT  20.437 36.288 21.516 36.312 ;
     RECT  20.437 36.312 21.564 36.432 ;
     RECT  20.437 36.432 21.516 36.456 ;
     RECT  20.437 36.456 21.564 36.576 ;
     RECT  20.437 36.576 21.516 36.6 ;
     RECT  20.437 36.6 21.564 36.72 ;
     RECT  20.437 36.72 21.516 36.744 ;
     RECT  20.437 36.744 21.564 36.864 ;
     RECT  20.437 36.864 21.516 36.888 ;
     RECT  20.437 36.888 21.564 37.008 ;
     RECT  20.437 37.008 21.516 37.032 ;
     RECT  20.437 37.032 21.564 37.152 ;
     RECT  20.437 37.152 21.516 37.176 ;
     RECT  20.437 37.176 21.564 37.296 ;
     RECT  20.437 37.296 21.516 37.32 ;
     RECT  20.437 37.32 21.564 37.44 ;
     RECT  20.437 37.44 21.516 37.464 ;
     RECT  20.437 37.464 21.564 37.584 ;
     RECT  20.437 37.584 21.516 37.608 ;
     RECT  20.437 37.608 21.564 37.728 ;
     RECT  20.437 37.728 21.516 37.752 ;
     RECT  20.437 37.752 21.564 37.872 ;
     RECT  20.437 37.872 21.516 37.896 ;
     RECT  20.437 37.896 21.564 38.016 ;
     RECT  20.437 38.016 21.516 38.04 ;
     RECT  20.437 38.04 21.564 38.16 ;
     RECT  20.437 38.16 21.516 38.184 ;
     RECT  20.437 38.184 21.564 38.304 ;
     RECT  20.437 38.304 21.516 38.328 ;
     RECT  20.437 38.328 21.564 38.448 ;
     RECT  20.437 38.448 21.516 38.472 ;
     RECT  20.437 38.472 21.564 38.592 ;
     RECT  20.437 38.592 21.516 38.616 ;
     RECT  20.437 38.616 21.564 38.736 ;
     RECT  20.437 38.736 21.516 38.76 ;
     RECT  20.437 38.76 21.564 38.88 ;
     RECT  20.437 38.88 21.516 38.904 ;
     RECT  20.437 38.904 21.564 39.024 ;
     RECT  20.437 39.024 21.516 39.048 ;
     RECT  20.437 39.048 21.564 39.168 ;
     RECT  20.437 39.168 21.516 39.192 ;
     RECT  20.437 39.192 21.564 39.312 ;
     RECT  20.437 39.312 21.516 39.336 ;
     RECT  20.437 39.336 21.564 39.456 ;
     RECT  20.437 39.456 21.516 39.48 ;
     RECT  20.437 39.48 21.564 39.6 ;
     RECT  20.437 39.6 21.516 39.624 ;
     RECT  20.437 39.624 21.564 39.744 ;
     RECT  20.437 39.744 21.516 39.768 ;
     RECT  20.437 39.768 21.564 39.888 ;
     RECT  20.437 39.888 21.516 39.912 ;
     RECT  20.437 39.912 21.564 40.032 ;
     RECT  20.437 40.032 21.516 40.056 ;
     RECT  20.437 40.056 21.564 40.176 ;
     RECT  20.437 40.176 21.516 40.2 ;
     RECT  20.437 40.2 21.564 40.32 ;
     RECT  20.437 40.32 21.516 40.344 ;
     RECT  20.437 40.344 21.564 40.464 ;
     RECT  20.437 40.464 21.516 40.488 ;
     RECT  20.437 40.488 21.564 40.608 ;
     RECT  20.437 40.608 21.516 40.632 ;
     RECT  20.437 40.632 21.564 40.752 ;
     RECT  20.437 40.752 21.516 40.776 ;
     RECT  20.437 40.776 21.564 40.896 ;
     RECT  20.437 40.896 21.516 40.92 ;
     RECT  20.437 40.92 21.564 41.04 ;
     RECT  20.437 41.04 21.516 41.064 ;
     RECT  20.437 41.064 21.564 41.184 ;
     RECT  20.437 41.184 21.516 41.208 ;
     RECT  20.437 41.208 21.564 41.328 ;
     RECT  20.437 41.328 21.516 41.352 ;
     RECT  20.437 41.352 21.564 41.472 ;
     RECT  20.437 41.472 21.516 41.496 ;
     RECT  20.437 41.496 21.564 41.616 ;
     RECT  20.437 41.616 21.516 41.64 ;
     RECT  20.437 41.64 21.564 41.76 ;
     RECT  20.437 41.76 21.516 41.784 ;
     RECT  20.437 41.784 21.564 41.904 ;
     RECT  20.437 41.904 21.516 41.928 ;
     RECT  20.437 41.928 21.564 42.048 ;
     RECT  20.437 42.048 21.516 42.072 ;
     RECT  20.437 42.072 21.564 42.192 ;
     RECT  20.437 42.192 21.516 42.216 ;
     RECT  20.437 42.216 21.564 42.336 ;
     RECT  20.437 42.336 21.516 42.36 ;
     RECT  20.437 42.36 21.564 42.48 ;
     RECT  20.437 42.48 21.516 42.504 ;
     RECT  20.437 42.504 21.564 42.624 ;
     RECT  20.437 42.624 21.516 42.648 ;
     RECT  20.437 42.648 21.564 42.768 ;
     RECT  20.437 42.768 21.516 42.792 ;
     RECT  20.437 42.792 21.564 42.912 ;
     RECT  20.437 42.912 21.516 42.936 ;
     RECT  20.437 42.936 21.564 43.056 ;
     RECT  20.437 43.056 21.516 43.08 ;
     RECT  20.437 43.08 21.564 43.2 ;
     RECT  20.437 43.2 21.516 43.224 ;
     RECT  20.437 43.224 21.564 43.344 ;
     RECT  20.437 43.344 21.516 43.368 ;
     RECT  20.437 43.368 21.564 43.488 ;
     RECT  20.437 43.488 21.516 43.512 ;
     RECT  20.437 43.512 21.564 43.632 ;
     RECT  20.437 43.632 21.516 43.656 ;
     RECT  20.437 43.656 21.564 43.776 ;
     RECT  20.437 43.776 21.516 43.8 ;
     RECT  20.437 43.8 21.564 43.92 ;
     RECT  20.437 43.92 21.516 43.944 ;
     RECT  20.437 43.944 21.564 44.064 ;
     RECT  20.437 44.064 21.516 44.088 ;
     RECT  20.437 44.088 21.564 44.208 ;
     RECT  20.437 44.208 21.516 44.232 ;
     RECT  20.437 44.232 21.564 44.352 ;
     RECT  20.437 44.352 21.516 44.376 ;
     RECT  20.437 44.376 21.564 44.496 ;
     RECT  20.437 44.496 21.516 44.52 ;
     RECT  20.437 44.52 21.564 44.64 ;
     RECT  20.437 44.64 21.516 44.664 ;
     RECT  20.437 44.664 21.564 44.784 ;
     RECT  20.437 44.784 21.516 44.808 ;
     RECT  20.437 44.808 21.564 44.928 ;
     RECT  20.437 44.928 21.516 44.952 ;
     RECT  20.437 44.952 21.564 45.072 ;
     RECT  20.437 45.072 21.516 45.096 ;
     RECT  20.437 45.096 21.564 45.216 ;
     RECT  20.437 45.216 21.516 45.24 ;
     RECT  20.437 45.24 21.564 45.36 ;
     RECT  20.437 45.36 21.516 45.384 ;
     RECT  20.437 45.384 21.564 45.504 ;
     RECT  20.437 45.504 21.516 45.528 ;
     RECT  20.437 45.528 21.564 45.648 ;
     RECT  20.437 45.648 21.516 45.672 ;
     RECT  20.437 45.672 21.564 45.792 ;
     RECT  20.437 45.792 21.516 45.816 ;
     RECT  20.437 45.816 21.564 45.936 ;
     RECT  20.437 45.936 21.516 45.96 ;
     RECT  20.437 45.96 21.564 46.08 ;
     RECT  20.437 46.08 21.516 46.104 ;
     RECT  20.437 46.104 21.564 46.224 ;
     RECT  20.437 46.224 21.516 46.248 ;
     RECT  20.437 46.248 21.564 46.368 ;
     RECT  20.437 46.368 21.516 46.392 ;
     RECT  20.437 46.392 21.564 46.512 ;
     RECT  20.437 46.512 21.516 46.536 ;
     RECT  20.437 46.536 21.564 46.656 ;
     RECT  20.437 46.656 21.516 46.68 ;
     RECT  20.437 46.68 21.564 46.8 ;
     RECT  20.437 46.8 21.516 46.824 ;
     RECT  20.437 46.824 21.564 46.944 ;
     RECT  20.437 46.944 21.516 46.968 ;
     RECT  20.437 46.968 21.564 47.088 ;
     RECT  20.437 47.088 21.516 47.112 ;
     RECT  20.437 47.112 21.564 47.232 ;
     RECT  20.437 47.232 21.516 47.256 ;
     RECT  20.437 47.256 21.564 47.376 ;
     RECT  20.437 47.376 21.516 47.4 ;
     RECT  20.437 47.4 21.564 47.52 ;
     RECT  20.437 47.52 21.516 47.544 ;
     RECT  20.437 47.544 21.564 47.664 ;
     RECT  20.437 47.664 21.516 47.688 ;
     RECT  20.437 47.688 21.564 47.808 ;
     RECT  20.437 47.808 21.516 47.832 ;
     RECT  20.437 47.832 21.564 47.952 ;
     RECT  20.437 47.952 21.516 47.976 ;
     RECT  20.437 47.976 21.564 48.096 ;
     RECT  20.437 48.096 21.516 48.12 ;
     RECT  20.437 48.12 21.564 48.24 ;
     RECT  20.437 48.24 21.516 48.264 ;
     RECT  20.437 48.264 21.564 48.384 ;
     RECT  20.437 48.384 21.516 48.408 ;
     RECT  20.437 48.408 21.564 48.528 ;
     RECT  20.437 48.528 21.516 48.552 ;
     RECT  20.437 48.552 21.564 48.672 ;
     RECT  20.437 48.672 21.516 48.696 ;
     RECT  20.437 48.696 21.564 48.816 ;
     RECT  20.437 48.816 21.516 48.84 ;
     RECT  20.437 48.84 21.564 48.96 ;
     RECT  20.437 48.96 21.516 48.984 ;
     RECT  20.437 48.984 21.564 49.104 ;
     RECT  20.437 49.104 21.516 49.128 ;
     RECT  20.437 49.128 21.564 49.248 ;
     RECT  20.437 49.248 21.516 49.272 ;
     RECT  20.437 49.272 21.564 49.392 ;
     RECT  20.437 49.392 21.516 49.416 ;
     RECT  20.437 49.416 21.564 49.536 ;
     RECT  20.437 49.536 21.516 49.56 ;
     RECT  20.437 49.56 21.564 49.68 ;
     RECT  20.437 49.68 21.516 49.704 ;
     RECT  20.437 49.704 21.564 49.824 ;
     RECT  20.437 49.824 21.516 49.848 ;
     RECT  20.437 49.848 21.564 49.968 ;
     RECT  20.437 49.968 21.516 49.992 ;
     RECT  20.437 49.992 21.564 50.112 ;
     RECT  20.437 50.112 21.516 50.136 ;
     RECT  20.437 50.136 21.564 50.256 ;
     RECT  20.437 50.256 21.516 50.28 ;
     RECT  20.437 50.28 21.564 50.4 ;
     RECT  20.437 50.4 21.516 50.424 ;
     RECT  20.437 50.424 21.564 50.544 ;
     RECT  20.437 50.544 21.516 50.568 ;
     RECT  20.437 50.568 21.564 50.688 ;
     RECT  20.437 50.688 21.516 50.712 ;
     RECT  20.437 50.712 21.564 50.832 ;
     RECT  20.437 50.832 21.516 50.856 ;
     RECT  20.437 50.856 21.564 50.976 ;
     RECT  20.437 50.976 21.516 51 ;
     RECT  20.437 51 21.564 51.12 ;
     RECT  20.437 51.12 21.516 51.144 ;
     RECT  20.437 51.144 21.564 51.264 ;
     RECT  20.437 51.264 21.516 51.288 ;
     RECT  20.437 51.288 21.564 51.408 ;
     RECT  20.437 51.408 21.516 51.432 ;
     RECT  20.437 51.432 21.564 51.552 ;
     RECT  20.437 51.552 21.516 51.576 ;
     RECT  20.437 51.576 21.564 51.696 ;
     RECT  20.437 51.696 21.516 51.72 ;
     RECT  20.437 51.72 21.564 51.84 ;
     RECT  20.437 51.84 21.516 51.864 ;
     RECT  20.437 51.864 21.564 51.984 ;
     RECT  20.437 51.984 21.516 52.008 ;
     RECT  20.437 52.008 21.564 52.128 ;
     RECT  20.437 52.128 21.516 52.152 ;
     RECT  20.437 52.152 21.564 52.272 ;
     RECT  20.437 52.272 21.516 52.296 ;
     RECT  20.437 52.296 21.564 52.416 ;
     RECT  20.437 52.416 21.516 52.44 ;
     RECT  20.437 52.44 21.564 52.56 ;
     RECT  20.437 52.56 21.516 52.584 ;
     RECT  20.437 52.584 21.564 52.704 ;
     RECT  20.437 52.704 21.516 52.728 ;
     RECT  20.437 52.728 21.564 52.848 ;
     RECT  20.437 52.848 21.516 52.872 ;
     RECT  20.437 52.872 21.564 52.992 ;
     RECT  20.437 52.992 21.516 53.016 ;
     RECT  20.437 53.016 21.564 53.136 ;
     RECT  20.437 53.136 21.516 53.16 ;
     RECT  20.437 53.16 21.564 53.28 ;
     RECT  20.437 53.28 21.516 53.304 ;
     RECT  20.437 53.304 21.564 53.424 ;
     RECT  20.437 53.424 21.516 53.448 ;
     RECT  20.437 53.448 21.564 53.568 ;
     RECT  20.437 53.568 21.516 53.592 ;
     RECT  20.437 53.592 21.564 53.712 ;
     RECT  20.437 53.712 21.516 53.736 ;
     RECT  20.437 53.736 21.564 53.856 ;
     RECT  20.437 53.856 21.516 53.88 ;
     RECT  20.437 53.88 21.564 54 ;
     RECT  20.437 54 21.516 54.024 ;
     RECT  20.437 54.024 21.564 54.144 ;
     RECT  20.437 54.144 21.516 54.168 ;
     RECT  20.437 54.168 21.564 54.288 ;
     RECT  20.437 54.288 21.516 54.312 ;
     RECT  20.437 54.312 21.564 54.432 ;
     RECT  20.437 54.432 21.516 54.456 ;
     RECT  20.437 54.456 21.564 54.576 ;
     RECT  20.437 54.576 21.516 54.6 ;
     RECT  20.437 54.6 21.564 54.72 ;
     RECT  20.437 54.72 21.516 54.744 ;
     RECT  20.437 54.744 21.564 54.864 ;
     RECT  20.437 54.864 21.516 54.888 ;
     RECT  20.437 54.888 21.564 55.008 ;
     RECT  20.437 55.008 21.516 55.032 ;
     RECT  20.437 55.032 21.564 55.152 ;
     RECT  20.437 55.152 21.516 55.176 ;
     RECT  20.437 55.176 21.564 55.296 ;
     RECT  20.437 55.296 21.516 55.32 ;
     RECT  20.437 55.32 21.564 55.44 ;
     RECT  20.437 55.44 21.516 55.464 ;
     RECT  20.437 55.464 21.564 55.584 ;
     RECT  20.437 55.584 21.516 55.608 ;
     RECT  20.437 55.608 21.564 55.728 ;
     RECT  20.437 55.728 21.516 55.752 ;
     RECT  20.437 55.752 21.564 55.872 ;
     RECT  20.437 55.872 21.516 55.896 ;
     RECT  20.437 55.896 21.564 56.016 ;
     RECT  20.437 56.016 21.516 56.04 ;
     RECT  20.437 56.04 21.564 56.16 ;
     RECT  20.437 56.16 21.516 56.184 ;
     RECT  20.437 56.184 21.564 56.304 ;
     RECT  20.437 56.304 21.516 56.328 ;
     RECT  20.437 56.328 21.564 56.448 ;
     RECT  20.437 56.448 21.516 56.472 ;
     RECT  20.437 56.472 21.564 56.592 ;
     RECT  20.437 56.592 21.516 56.616 ;
     RECT  20.437 56.616 21.564 56.736 ;
     RECT  20.437 56.736 21.516 56.76 ;
     RECT  20.437 56.76 21.564 56.88 ;
     RECT  20.437 56.88 21.516 56.904 ;
     RECT  20.437 56.904 21.564 57.024 ;
     RECT  20.437 57.024 21.516 57.048 ;
     RECT  20.437 57.048 21.564 57.168 ;
     RECT  20.437 57.168 21.516 57.192 ;
     RECT  20.437 57.192 21.564 57.312 ;
     RECT  20.437 57.312 21.516 57.336 ;
     RECT  20.509 58.32 21.516 58.344 ;
     RECT  20.509 58.344 21.564 58.464 ;
     RECT  20.509 58.464 21.516 58.488 ;
     RECT  20.509 58.488 21.564 58.608 ;
     RECT  20.509 58.608 21.516 58.632 ;
     RECT  20.509 58.632 21.564 58.752 ;
     RECT  20.509 58.752 21.516 58.776 ;
     RECT  20.509 58.776 21.564 58.896 ;
     RECT  20.509 58.896 21.516 58.92 ;
     RECT  20.509 58.92 21.564 59.04 ;
     RECT  20.509 59.04 21.516 59.064 ;
     RECT  20.509 59.064 21.564 59.184 ;
     RECT  20.509 59.184 21.516 59.208 ;
     RECT  20.509 59.208 21.564 59.328 ;
     RECT  20.509 59.328 21.516 59.352 ;
     RECT  20.509 59.352 21.564 59.472 ;
     RECT  20.509 59.472 21.516 59.496 ;
     RECT  20.509 59.496 21.564 59.616 ;
     RECT  20.509 59.616 21.516 59.64 ;
     RECT  20.509 59.64 21.564 59.76 ;
     RECT  20.509 59.76 21.516 59.784 ;
     RECT  20.509 59.784 21.564 59.904 ;
     RECT  20.509 59.904 21.516 59.928 ;
     RECT  20.509 59.928 21.564 60.048 ;
     RECT  20.509 60.048 21.516 60.072 ;
     RECT  20.509 60.072 21.564 60.192 ;
     RECT  20.509 60.192 21.516 60.216 ;
     RECT  20.509 60.216 21.564 60.336 ;
     RECT  20.509 60.336 21.516 60.36 ;
     RECT  20.509 60.36 21.564 60.48 ;
     RECT  20.509 60.48 21.516 60.504 ;
     RECT  20.509 60.504 21.564 60.624 ;
     RECT  20.509 60.624 21.516 60.648 ;
     RECT  20.509 60.648 21.564 60.768 ;
     RECT  20.509 60.768 21.516 60.792 ;
     RECT  20.509 60.792 21.564 60.912 ;
     RECT  20.509 60.912 21.516 60.936 ;
     RECT  20.509 60.936 21.564 61.056 ;
     RECT  20.509 61.056 21.516 61.08 ;
     RECT  20.509 61.08 21.564 61.2 ;
     RECT  20.509 61.2 21.516 61.224 ;
     RECT  20.509 61.224 21.564 61.344 ;
     RECT  20.509 61.344 21.516 61.368 ;
     RECT  20.509 61.368 21.564 61.488 ;
     RECT  20.509 61.488 21.516 61.512 ;
     RECT  20.509 61.512 21.564 61.632 ;
     RECT  20.509 61.632 21.516 61.656 ;
     RECT  20.509 61.656 21.564 61.776 ;
     RECT  20.509 61.776 21.516 61.8 ;
     RECT  20.509 61.8 21.564 61.92 ;
     RECT  20.509 61.92 21.516 61.944 ;
     RECT  20.509 61.944 21.564 62.064 ;
     RECT  20.509 62.064 21.516 62.088 ;
     RECT  20.509 62.088 21.564 62.208 ;
     RECT  20.509 62.208 21.516 62.232 ;
     RECT  20.509 62.232 21.564 62.352 ;
     RECT  20.509 62.352 21.516 62.376 ;
     RECT  20.509 62.376 21.564 62.496 ;
     RECT  20.509 62.496 21.516 62.52 ;
     RECT  20.509 62.52 21.564 62.64 ;
     RECT  20.509 62.64 21.516 62.664 ;
     RECT  20.509 62.664 21.564 62.784 ;
     RECT  20.509 62.784 21.516 62.808 ;
     RECT  20.509 62.808 21.564 62.928 ;
     RECT  20.509 62.928 21.516 62.952 ;
     RECT  20.509 62.952 21.564 63.072 ;
     RECT  20.509 63.072 21.516 63.096 ;
     RECT  20.509 63.096 21.564 63.216 ;
     RECT  20.509 63.216 21.516 63.24 ;
     RECT  20.509 63.24 21.564 63.36 ;
     RECT  20.509 63.36 21.516 63.384 ;
     RECT  20.509 63.384 21.564 63.504 ;
     RECT  20.509 63.504 21.516 63.528 ;
     RECT  20.509 63.528 21.564 63.648 ;
     RECT  20.509 63.648 21.516 63.672 ;
     RECT  20.509 63.672 21.564 63.792 ;
     RECT  20.509 63.792 21.516 63.816 ;
     RECT  20.509 63.816 21.564 63.936 ;
     RECT  20.509 63.936 21.516 63.96 ;
     RECT  20.509 63.96 21.564 64.08 ;
     RECT  20.509 64.08 21.516 64.104 ;
     RECT  20.509 64.104 21.564 64.224 ;
     RECT  20.509 64.224 21.516 64.248 ;
     RECT  20.509 64.248 21.564 64.368 ;
     RECT  20.509 64.368 21.516 64.392 ;
     RECT  20.509 64.392 21.564 64.512 ;
     RECT  20.509 64.512 21.516 64.536 ;
     RECT  20.509 64.536 21.564 64.656 ;
     RECT  20.509 64.656 21.516 64.68 ;
     RECT  20.509 64.68 21.564 64.8 ;
     RECT  20.509 64.8 21.516 64.824 ;
     RECT  20.509 64.824 21.564 64.944 ;
     RECT  20.509 64.944 21.516 64.968 ;
     RECT  20.509 64.968 21.564 65.088 ;
     RECT  20.509 65.088 21.516 65.112 ;
     RECT  20.509 65.112 21.564 65.232 ;
     RECT  20.509 65.232 21.516 65.256 ;
     RECT  20.509 65.256 21.564 65.376 ;
     RECT  20.509 65.376 21.516 65.4 ;
     RECT  20.509 65.4 21.564 65.52 ;
     RECT  20.509 65.52 21.516 65.544 ;
     RECT  20.509 65.544 21.564 65.664 ;
     RECT  20.509 65.664 21.516 65.688 ;
     RECT  20.509 65.688 21.564 65.808 ;
     RECT  20.509 65.808 21.516 65.832 ;
     RECT  20.509 65.832 21.564 65.952 ;
     RECT  20.509 65.952 21.516 65.976 ;
     RECT  20.509 65.976 21.564 66.096 ;
     RECT  20.509 66.096 21.516 66.12 ;
     RECT  20.509 66.12 21.564 66.24 ;
     RECT  20.509 66.24 21.516 66.264 ;
     RECT  20.509 66.264 21.564 66.384 ;
     RECT  20.509 66.384 21.516 66.408 ;
     RECT  20.509 66.408 21.564 66.528 ;
     RECT  20.509 66.528 21.516 66.552 ;
     RECT  20.509 66.552 21.564 66.672 ;
     RECT  20.509 66.672 21.516 66.696 ;
     RECT  20.509 66.696 21.564 66.816 ;
     RECT  20.509 66.816 21.516 66.84 ;
     RECT  20.509 66.84 21.564 66.96 ;
     RECT  20.509 66.96 21.516 66.984 ;
     RECT  20.509 66.984 21.564 67.104 ;
     RECT  20.509 67.104 21.516 67.128 ;
     RECT  20.509 67.128 21.564 67.248 ;
     RECT  20.509 67.248 21.516 67.272 ;
     RECT  20.509 67.272 21.564 67.392 ;
     RECT  20.509 67.392 21.516 67.416 ;
    LAYER M5 ;
     RECT  2.4 2.137 2.52 2.151 ;
     RECT  5.1 2.137 5.22 2.151 ;
     RECT  7.8 2.137 7.92 2.151 ;
     RECT  10.5 2.137 10.62 2.151 ;
     RECT  13.2 2.137 13.32 2.151 ;
     RECT  15.9 2.137 16.02 2.151 ;
     RECT  18.6 2.137 18.72 2.151 ;
     RECT  0.24 10.357 0.264 12.229 ;
     RECT  0.144 12.229 0.264 13.045 ;
     RECT  2.4 2.151 2.712 13.621 ;
     RECT  0.144 13.045 0.312 14.291 ;
     RECT  0.144 14.291 0.264 14.867 ;
     RECT  0.144 14.867 0.216 16.357 ;
     RECT  0.144 16.357 0.36 17.077 ;
     RECT  0.144 17.077 1.176 17.219 ;
     RECT  0.144 17.219 0.36 17.315 ;
     RECT  0.144 17.315 0.264 17.747 ;
     RECT  2.4 13.621 3.48 18.469 ;
     RECT  2.304 18.469 3.912 18.661 ;
     RECT  5.1 2.151 5.412 18.661 ;
     RECT  0.144 17.747 0.216 19.573 ;
     RECT  0.144 19.573 0.312 20.581 ;
     RECT  0.144 20.581 0.552 21.155 ;
     RECT  0.192 21.155 0.552 21.203 ;
     RECT  0.192 21.203 0.216 21.683 ;
     RECT  0.144 22.549 0.168 22.787 ;
     RECT  2.304 18.661 5.412 22.835 ;
     RECT  10.5 2.151 10.812 23.701 ;
     RECT  7.8 2.151 8.112 25.621 ;
     RECT  9.792 23.701 10.812 25.621 ;
     RECT  0.144 25.813 0.168 26.099 ;
     RECT  2.4 22.835 5.412 28.547 ;
     RECT  0.144 29.221 0.168 29.363 ;
     RECT  7.8 25.621 10.812 29.363 ;
     RECT  2.4 28.547 3.336 29.699 ;
     RECT  15.9 2.151 16.212 32.437 ;
     RECT  13.2 2.151 13.512 33.013 ;
     RECT  0.528 32.293 0.552 33.155 ;
     RECT  9.792 29.363 10.812 33.539 ;
     RECT  2.4 29.699 3.096 33.589 ;
     RECT  13.2 33.013 14.28 34.355 ;
     RECT  2.4 33.589 3.768 34.405 ;
     RECT  0.144 33.493 0.168 34.451 ;
     RECT  15.408 32.437 16.212 35.171 ;
     RECT  13.2 34.355 13.944 36.997 ;
     RECT  11.808 36.997 13.944 37.141 ;
     RECT  11.808 37.141 14.28 37.859 ;
     RECT  2.304 34.405 3.768 38.003 ;
     RECT  15.9 35.171 16.212 38.149 ;
     RECT  11.808 37.859 14.04 39.301 ;
     RECT  15.312 38.149 16.212 39.301 ;
     RECT  11.808 39.301 16.212 39.491 ;
     RECT  13.2 39.491 16.212 40.549 ;
     RECT  13.104 40.549 16.212 41.603 ;
     RECT  11.808 39.491 11.832 42.133 ;
     RECT  11.808 42.133 11.928 42.709 ;
     RECT  13.104 41.603 14.04 42.709 ;
     RECT  2.4 38.003 3.768 42.853 ;
     RECT  2.4 42.853 3.864 43.043 ;
     RECT  11.808 42.709 14.04 43.811 ;
     RECT  2.4 43.043 3.528 44.147 ;
     RECT  15.36 41.603 16.212 44.483 ;
     RECT  11.808 43.811 11.928 44.627 ;
     RECT  0.144 44.629 0.168 44.771 ;
     RECT  13.2 43.811 14.04 45.541 ;
     RECT  15.9 44.483 16.212 45.541 ;
     RECT  15.264 45.541 16.212 46.211 ;
     RECT  13.2 45.541 14.232 46.357 ;
     RECT  11.808 44.627 11.832 47.939 ;
     RECT  13.2 46.357 14.568 48.421 ;
     RECT  12.624 48.421 14.568 48.659 ;
     RECT  12.624 48.659 14.04 50.245 ;
     RECT  5.1 28.547 5.412 51.109 ;
     RECT  12.624 50.245 14.808 51.395 ;
     RECT  4.464 51.109 5.412 51.493 ;
     RECT  15.9 46.211 16.212 52.405 ;
     RECT  12.624 51.395 14.232 53.509 ;
     RECT  15.552 52.405 16.212 53.509 ;
     RECT  12.624 53.509 16.212 53.749 ;
     RECT  2.4 44.147 2.712 53.893 ;
     RECT  11.904 53.749 16.212 54.179 ;
     RECT  11.904 54.179 14.856 54.371 ;
     RECT  12.144 54.371 14.856 54.755 ;
     RECT  0.144 53.125 0.168 54.995 ;
     RECT  2.304 53.893 2.712 55.237 ;
     RECT  13.2 54.755 14.856 55.237 ;
     RECT  15.9 54.179 16.212 55.237 ;
     RECT  2.304 55.237 2.808 55.477 ;
     RECT  4.464 51.493 6.168 55.813 ;
     RECT  12.144 54.755 12.168 55.907 ;
     RECT  13.2 55.237 16.212 55.907 ;
     RECT  14.832 55.907 16.212 56.483 ;
     RECT  13.2 55.907 13.512 56.533 ;
     RECT  0.288 56.581 0.312 56.725 ;
     RECT  0.288 56.725 0.552 57.683 ;
     RECT  14.832 56.483 14.856 58.069 ;
     RECT  15.9 56.483 16.212 58.069 ;
     RECT  14.832 58.069 16.212 58.115 ;
     RECT  13.104 56.533 13.512 58.163 ;
     RECT  4.464 55.813 6.36 58.405 ;
     RECT  11.904 57.157 11.928 58.931 ;
     RECT  13.2 58.163 13.512 59.461 ;
     RECT  0.144 58.453 0.168 59.893 ;
     RECT  2.304 55.477 3.24 59.989 ;
     RECT  4.464 58.405 6.504 59.989 ;
     RECT  15.36 58.115 16.212 60.563 ;
     RECT  12.528 59.461 13.512 61.477 ;
     RECT  12.528 61.477 14.328 61.619 ;
     RECT  15.9 60.563 16.212 62.629 ;
     RECT  0.144 59.893 0.264 62.771 ;
     RECT  13.2 61.619 14.328 63.011 ;
     RECT  0.192 62.771 0.264 63.157 ;
     RECT  13.2 63.011 13.512 63.205 ;
     RECT  0.192 63.157 0.552 64.213 ;
     RECT  12.96 63.205 13.512 64.403 ;
     RECT  15.36 62.629 16.212 64.595 ;
     RECT  0.144 64.213 0.552 65.027 ;
     RECT  0.192 65.027 0.552 65.123 ;
     RECT  0.192 65.123 0.504 65.411 ;
     RECT  0.192 65.411 0.216 65.699 ;
     RECT  2.304 59.989 6.504 66.755 ;
     RECT  2.304 66.755 3.768 67.283 ;
     RECT  0.192 67.189 0.216 67.381 ;
     RECT  0.144 67.381 0.216 67.715 ;
     RECT  2.304 67.283 3.432 68.435 ;
     RECT  2.304 68.435 3.24 73.283 ;
     RECT  0.144 67.715 0.168 73.333 ;
     RECT  0.144 73.333 0.216 74.053 ;
     RECT  0.144 74.053 0.264 74.339 ;
     RECT  5.1 66.755 6.504 75.443 ;
     RECT  6.48 75.443 6.504 75.971 ;
     RECT  2.4 73.283 3.24 76.979 ;
     RECT  2.4 76.979 2.712 78.181 ;
     RECT  1.824 78.181 2.712 78.371 ;
     RECT  0.144 74.339 0.216 79.379 ;
     RECT  0.144 79.379 0.168 83.699 ;
     RECT  2.4 78.371 2.712 92.889 ;
     RECT  5.1 75.443 5.412 92.889 ;
     RECT  7.8 29.363 8.112 92.889 ;
     RECT  10.5 33.539 10.812 92.889 ;
     RECT  13.2 64.403 13.512 92.889 ;
     RECT  15.9 64.595 16.212 92.889 ;
     RECT  18.6 2.151 18.912 92.889 ;
     RECT  2.4 92.889 2.52 92.903 ;
     RECT  5.1 92.889 5.22 92.903 ;
     RECT  7.8 92.889 7.92 92.903 ;
     RECT  10.5 92.889 10.62 92.903 ;
     RECT  13.2 92.889 13.32 92.903 ;
     RECT  15.9 92.889 16.02 92.903 ;
     RECT  18.6 92.889 18.72 92.903 ;
     RECT  0.216 14.867 0.264 16.357 ;
     RECT  1.176 17.077 2.4 17.219 ;
     RECT  2.304 17.219 2.4 18.469 ;
     RECT  3.912 18.469 5.1 18.661 ;
     RECT  0.144 21.155 0.192 21.683 ;
     RECT  0.144 21.683 0.168 22.549 ;
     RECT  14.28 33.013 15.408 34.355 ;
     RECT  3.768 33.589 5.1 42.853 ;
     RECT  13.944 34.355 15.408 35.171 ;
     RECT  10.812 36.997 11.76 37.045 ;
     RECT  10.812 37.045 11.808 47.939 ;
     RECT  14.04 37.859 14.28 38.149 ;
     RECT  14.04 38.149 15.312 39.301 ;
     RECT  11.832 39.491 13.2 40.549 ;
     RECT  11.832 40.549 13.104 42.133 ;
     RECT  14.04 41.603 15.36 44.483 ;
     RECT  11.928 42.133 13.104 42.709 ;
     RECT  3.864 42.853 5.1 43.043 ;
     RECT  11.928 43.811 13.2 44.627 ;
     RECT  14.04 44.483 15.9 45.541 ;
     RECT  11.832 44.627 13.2 47.939 ;
     RECT  14.232 45.541 15.264 46.211 ;
     RECT  14.232 46.211 15.9 46.357 ;
     RECT  14.568 46.357 15.9 48.659 ;
     RECT  12.624 47.939 13.2 48.421 ;
     RECT  14.808 50.245 15.9 51.395 ;
     RECT  14.232 51.395 15.9 52.405 ;
     RECT  14.232 52.405 15.552 53.509 ;
     RECT  10.812 53.749 11.904 54.371 ;
     RECT  14.856 54.179 15.9 55.237 ;
     RECT  10.812 54.371 12.144 55.907 ;
     RECT  12.168 54.755 13.2 55.907 ;
     RECT  3.24 55.477 4.464 59.989 ;
     RECT  6.36 55.813 7.8 58.405 ;
     RECT  10.812 55.907 13.2 56.533 ;
     RECT  13.512 55.907 14.832 58.115 ;
     RECT  14.856 56.483 15.9 58.069 ;
     RECT  10.812 56.533 13.104 57.157 ;
     RECT  10.812 57.157 11.904 58.931 ;
     RECT  11.928 57.157 13.104 58.163 ;
     RECT  11.928 58.163 13.2 58.931 ;
     RECT  6.504 58.405 7.8 75.971 ;
     RECT  12.528 58.931 13.2 59.461 ;
     RECT  14.328 62.629 15.36 63.011 ;
     RECT  0.144 62.771 0.192 64.213 ;
     RECT  0.192 65.699 0.216 67.189 ;
     RECT  3.768 66.755 5.1 67.283 ;
     RECT  5.412 75.443 6.48 75.971 ;
  END
END qkd_rlyi_258
END LIBRARY
